VERSION 5.8 ;
BUSBITCHARS "[]" ;
DIVIDERCHAR "/" ;
UNITS
    DATABASE MICRONS 1000 ;
END UNITS

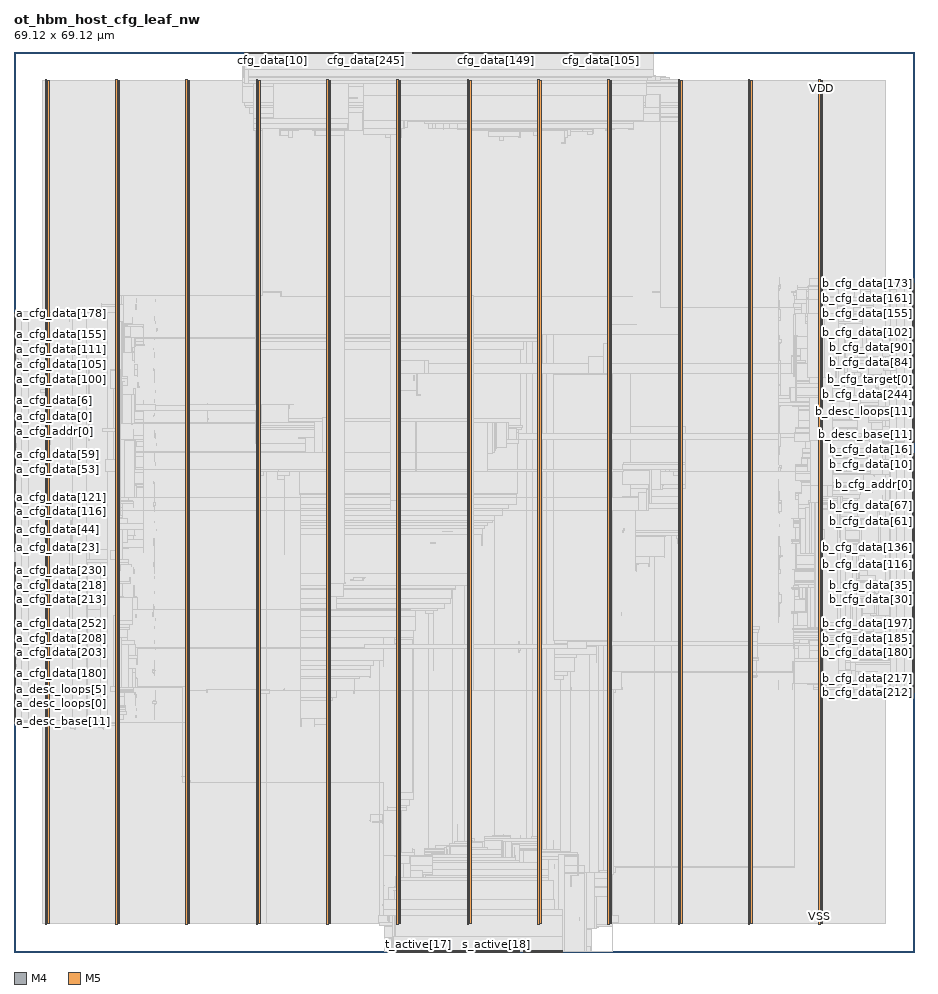
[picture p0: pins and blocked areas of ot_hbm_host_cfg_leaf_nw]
MACRO ot_hbm_host_cfg_leaf_nw
  FOREIGN ot_hbm_host_cfg_leaf_nw 0 0 ;
  CLASS BLOCK ;
  SIZE 69.12 BY 69.12 ;
  PIN a_cfg_addr[0]
    DIRECTION OUTPUT ;
    USE SIGNAL ;
    PORT
      LAYER M4 ;
        RECT  0 39.984 0.084 40.008 ;
    END
  END a_cfg_addr[0]
  PIN a_cfg_addr[10]
    DIRECTION OUTPUT ;
    USE SIGNAL ;
    PORT
      LAYER M4 ;
        RECT  0 40.944 0.084 40.968 ;
    END
  END a_cfg_addr[10]
  PIN a_cfg_addr[11]
    DIRECTION OUTPUT ;
    USE SIGNAL ;
    PORT
      LAYER M4 ;
        RECT  0 41.04 0.084 41.064 ;
    END
  END a_cfg_addr[11]
  PIN a_cfg_addr[1]
    DIRECTION OUTPUT ;
    USE SIGNAL ;
    PORT
      LAYER M4 ;
        RECT  0 40.08 0.084 40.104 ;
    END
  END a_cfg_addr[1]
  PIN a_cfg_addr[2]
    DIRECTION OUTPUT ;
    USE SIGNAL ;
    PORT
      LAYER M4 ;
        RECT  0 40.176 0.084 40.2 ;
    END
  END a_cfg_addr[2]
  PIN a_cfg_addr[3]
    DIRECTION OUTPUT ;
    USE SIGNAL ;
    PORT
      LAYER M4 ;
        RECT  0 40.272 0.084 40.296 ;
    END
  END a_cfg_addr[3]
  PIN a_cfg_addr[4]
    DIRECTION OUTPUT ;
    USE SIGNAL ;
    PORT
      LAYER M4 ;
        RECT  0 40.368 0.084 40.392 ;
    END
  END a_cfg_addr[4]
  PIN a_cfg_addr[5]
    DIRECTION OUTPUT ;
    USE SIGNAL ;
    PORT
      LAYER M4 ;
        RECT  0 40.464 0.084 40.488 ;
    END
  END a_cfg_addr[5]
  PIN a_cfg_addr[6]
    DIRECTION OUTPUT ;
    USE SIGNAL ;
    PORT
      LAYER M4 ;
        RECT  0 40.56 0.084 40.584 ;
    END
  END a_cfg_addr[6]
  PIN a_cfg_addr[7]
    DIRECTION OUTPUT ;
    USE SIGNAL ;
    PORT
      LAYER M4 ;
        RECT  0 40.656 0.084 40.68 ;
    END
  END a_cfg_addr[7]
  PIN a_cfg_addr[8]
    DIRECTION OUTPUT ;
    USE SIGNAL ;
    PORT
      LAYER M4 ;
        RECT  0 40.752 0.084 40.776 ;
    END
  END a_cfg_addr[8]
  PIN a_cfg_addr[9]
    DIRECTION OUTPUT ;
    USE SIGNAL ;
    PORT
      LAYER M4 ;
        RECT  0 40.848 0.084 40.872 ;
    END
  END a_cfg_addr[9]
  PIN a_cfg_data[0]
    DIRECTION OUTPUT ;
    USE SIGNAL ;
    PORT
      LAYER M4 ;
        RECT  0 41.136 0.084 41.16 ;
    END
  END a_cfg_data[0]
  PIN a_cfg_data[100]
    DIRECTION OUTPUT ;
    USE SIGNAL ;
    PORT
      LAYER M4 ;
        RECT  0 44.592 0.084 44.616 ;
    END
  END a_cfg_data[100]
  PIN a_cfg_data[101]
    DIRECTION OUTPUT ;
    USE SIGNAL ;
    PORT
      LAYER M4 ;
        RECT  0 44.688 0.084 44.712 ;
    END
  END a_cfg_data[101]
  PIN a_cfg_data[102]
    DIRECTION OUTPUT ;
    USE SIGNAL ;
    PORT
      LAYER M4 ;
        RECT  0 44.784 0.084 44.808 ;
    END
  END a_cfg_data[102]
  PIN a_cfg_data[103]
    DIRECTION OUTPUT ;
    USE SIGNAL ;
    PORT
      LAYER M4 ;
        RECT  0 44.88 0.084 44.904 ;
    END
  END a_cfg_data[103]
  PIN a_cfg_data[104]
    DIRECTION OUTPUT ;
    USE SIGNAL ;
    PORT
      LAYER M4 ;
        RECT  0 44.976 0.084 45 ;
    END
  END a_cfg_data[104]
  PIN a_cfg_data[105]
    DIRECTION OUTPUT ;
    USE SIGNAL ;
    PORT
      LAYER M4 ;
        RECT  0 45.072 0.084 45.096 ;
    END
  END a_cfg_data[105]
  PIN a_cfg_data[106]
    DIRECTION OUTPUT ;
    USE SIGNAL ;
    PORT
      LAYER M4 ;
        RECT  0 45.168 0.084 45.192 ;
    END
  END a_cfg_data[106]
  PIN a_cfg_data[107]
    DIRECTION OUTPUT ;
    USE SIGNAL ;
    PORT
      LAYER M4 ;
        RECT  0 45.264 0.084 45.288 ;
    END
  END a_cfg_data[107]
  PIN a_cfg_data[108]
    DIRECTION OUTPUT ;
    USE SIGNAL ;
    PORT
      LAYER M4 ;
        RECT  0 45.36 0.084 45.384 ;
    END
  END a_cfg_data[108]
  PIN a_cfg_data[109]
    DIRECTION OUTPUT ;
    USE SIGNAL ;
    PORT
      LAYER M4 ;
        RECT  0 45.456 0.084 45.48 ;
    END
  END a_cfg_data[109]
  PIN a_cfg_data[10]
    DIRECTION OUTPUT ;
    USE SIGNAL ;
    PORT
      LAYER M4 ;
        RECT  0 42.096 0.084 42.12 ;
    END
  END a_cfg_data[10]
  PIN a_cfg_data[110]
    DIRECTION OUTPUT ;
    USE SIGNAL ;
    PORT
      LAYER M4 ;
        RECT  0 45.552 0.084 45.576 ;
    END
  END a_cfg_data[110]
  PIN a_cfg_data[111]
    DIRECTION OUTPUT ;
    USE SIGNAL ;
    PORT
      LAYER M4 ;
        RECT  0 45.648 0.084 45.672 ;
    END
  END a_cfg_data[111]
  PIN a_cfg_data[112]
    DIRECTION OUTPUT ;
    USE SIGNAL ;
    PORT
      LAYER M4 ;
        RECT  0 45.744 0.084 45.768 ;
    END
  END a_cfg_data[112]
  PIN a_cfg_data[113]
    DIRECTION OUTPUT ;
    USE SIGNAL ;
    PORT
      LAYER M4 ;
        RECT  0 45.84 0.084 45.864 ;
    END
  END a_cfg_data[113]
  PIN a_cfg_data[114]
    DIRECTION OUTPUT ;
    USE SIGNAL ;
    PORT
      LAYER M4 ;
        RECT  0 45.936 0.084 45.96 ;
    END
  END a_cfg_data[114]
  PIN a_cfg_data[115]
    DIRECTION OUTPUT ;
    USE SIGNAL ;
    PORT
      LAYER M4 ;
        RECT  0 46.032 0.084 46.056 ;
    END
  END a_cfg_data[115]
  PIN a_cfg_data[116]
    DIRECTION OUTPUT ;
    USE SIGNAL ;
    PORT
      LAYER M4 ;
        RECT  0 33.84 0.084 33.864 ;
    END
  END a_cfg_data[116]
  PIN a_cfg_data[117]
    DIRECTION OUTPUT ;
    USE SIGNAL ;
    PORT
      LAYER M4 ;
        RECT  0 33.936 0.084 33.96 ;
    END
  END a_cfg_data[117]
  PIN a_cfg_data[118]
    DIRECTION OUTPUT ;
    USE SIGNAL ;
    PORT
      LAYER M4 ;
        RECT  0 34.032 0.084 34.056 ;
    END
  END a_cfg_data[118]
  PIN a_cfg_data[119]
    DIRECTION OUTPUT ;
    USE SIGNAL ;
    PORT
      LAYER M4 ;
        RECT  0 34.128 0.084 34.152 ;
    END
  END a_cfg_data[119]
  PIN a_cfg_data[11]
    DIRECTION OUTPUT ;
    USE SIGNAL ;
    PORT
      LAYER M4 ;
        RECT  0 42.192 0.084 42.216 ;
    END
  END a_cfg_data[11]
  PIN a_cfg_data[120]
    DIRECTION OUTPUT ;
    USE SIGNAL ;
    PORT
      LAYER M4 ;
        RECT  0 34.224 0.084 34.248 ;
    END
  END a_cfg_data[120]
  PIN a_cfg_data[121]
    DIRECTION OUTPUT ;
    USE SIGNAL ;
    PORT
      LAYER M4 ;
        RECT  0 34.32 0.084 34.344 ;
    END
  END a_cfg_data[121]
  PIN a_cfg_data[122]
    DIRECTION OUTPUT ;
    USE SIGNAL ;
    PORT
      LAYER M4 ;
        RECT  0 34.416 0.084 34.44 ;
    END
  END a_cfg_data[122]
  PIN a_cfg_data[123]
    DIRECTION OUTPUT ;
    USE SIGNAL ;
    PORT
      LAYER M4 ;
        RECT  0 34.512 0.084 34.536 ;
    END
  END a_cfg_data[123]
  PIN a_cfg_data[124]
    DIRECTION OUTPUT ;
    USE SIGNAL ;
    PORT
      LAYER M4 ;
        RECT  0 34.608 0.084 34.632 ;
    END
  END a_cfg_data[124]
  PIN a_cfg_data[125]
    DIRECTION OUTPUT ;
    USE SIGNAL ;
    PORT
      LAYER M4 ;
        RECT  0 34.704 0.084 34.728 ;
    END
  END a_cfg_data[125]
  PIN a_cfg_data[126]
    DIRECTION OUTPUT ;
    USE SIGNAL ;
    PORT
      LAYER M4 ;
        RECT  0 34.8 0.084 34.824 ;
    END
  END a_cfg_data[126]
  PIN a_cfg_data[127]
    DIRECTION OUTPUT ;
    USE SIGNAL ;
    PORT
      LAYER M4 ;
        RECT  0 34.896 0.084 34.92 ;
    END
  END a_cfg_data[127]
  PIN a_cfg_data[128]
    DIRECTION OUTPUT ;
    USE SIGNAL ;
    PORT
      LAYER M4 ;
        RECT  0 34.992 0.084 35.016 ;
    END
  END a_cfg_data[128]
  PIN a_cfg_data[129]
    DIRECTION OUTPUT ;
    USE SIGNAL ;
    PORT
      LAYER M4 ;
        RECT  0 35.088 0.084 35.112 ;
    END
  END a_cfg_data[129]
  PIN a_cfg_data[12]
    DIRECTION OUTPUT ;
    USE SIGNAL ;
    PORT
      LAYER M4 ;
        RECT  0 42.288 0.084 42.312 ;
    END
  END a_cfg_data[12]
  PIN a_cfg_data[130]
    DIRECTION OUTPUT ;
    USE SIGNAL ;
    PORT
      LAYER M4 ;
        RECT  0 35.184 0.084 35.208 ;
    END
  END a_cfg_data[130]
  PIN a_cfg_data[131]
    DIRECTION OUTPUT ;
    USE SIGNAL ;
    PORT
      LAYER M4 ;
        RECT  0 35.28 0.084 35.304 ;
    END
  END a_cfg_data[131]
  PIN a_cfg_data[132]
    DIRECTION OUTPUT ;
    USE SIGNAL ;
    PORT
      LAYER M4 ;
        RECT  0 35.376 0.084 35.4 ;
    END
  END a_cfg_data[132]
  PIN a_cfg_data[133]
    DIRECTION OUTPUT ;
    USE SIGNAL ;
    PORT
      LAYER M4 ;
        RECT  0 35.472 0.084 35.496 ;
    END
  END a_cfg_data[133]
  PIN a_cfg_data[134]
    DIRECTION OUTPUT ;
    USE SIGNAL ;
    PORT
      LAYER M4 ;
        RECT  0 35.568 0.084 35.592 ;
    END
  END a_cfg_data[134]
  PIN a_cfg_data[135]
    DIRECTION OUTPUT ;
    USE SIGNAL ;
    PORT
      LAYER M4 ;
        RECT  0 35.664 0.084 35.688 ;
    END
  END a_cfg_data[135]
  PIN a_cfg_data[136]
    DIRECTION OUTPUT ;
    USE SIGNAL ;
    PORT
      LAYER M4 ;
        RECT  0 35.76 0.084 35.784 ;
    END
  END a_cfg_data[136]
  PIN a_cfg_data[137]
    DIRECTION OUTPUT ;
    USE SIGNAL ;
    PORT
      LAYER M4 ;
        RECT  0 35.856 0.084 35.88 ;
    END
  END a_cfg_data[137]
  PIN a_cfg_data[138]
    DIRECTION OUTPUT ;
    USE SIGNAL ;
    PORT
      LAYER M4 ;
        RECT  0 35.952 0.084 35.976 ;
    END
  END a_cfg_data[138]
  PIN a_cfg_data[139]
    DIRECTION OUTPUT ;
    USE SIGNAL ;
    PORT
      LAYER M4 ;
        RECT  0 36.048 0.084 36.072 ;
    END
  END a_cfg_data[139]
  PIN a_cfg_data[13]
    DIRECTION OUTPUT ;
    USE SIGNAL ;
    PORT
      LAYER M4 ;
        RECT  0 42.384 0.084 42.408 ;
    END
  END a_cfg_data[13]
  PIN a_cfg_data[140]
    DIRECTION OUTPUT ;
    USE SIGNAL ;
    PORT
      LAYER M4 ;
        RECT  0 36.144 0.084 36.168 ;
    END
  END a_cfg_data[140]
  PIN a_cfg_data[141]
    DIRECTION OUTPUT ;
    USE SIGNAL ;
    PORT
      LAYER M4 ;
        RECT  0 36.24 0.084 36.264 ;
    END
  END a_cfg_data[141]
  PIN a_cfg_data[142]
    DIRECTION OUTPUT ;
    USE SIGNAL ;
    PORT
      LAYER M4 ;
        RECT  0 36.336 0.084 36.36 ;
    END
  END a_cfg_data[142]
  PIN a_cfg_data[143]
    DIRECTION OUTPUT ;
    USE SIGNAL ;
    PORT
      LAYER M4 ;
        RECT  0 36.432 0.084 36.456 ;
    END
  END a_cfg_data[143]
  PIN a_cfg_data[144]
    DIRECTION OUTPUT ;
    USE SIGNAL ;
    PORT
      LAYER M4 ;
        RECT  0 36.528 0.084 36.552 ;
    END
  END a_cfg_data[144]
  PIN a_cfg_data[145]
    DIRECTION OUTPUT ;
    USE SIGNAL ;
    PORT
      LAYER M4 ;
        RECT  0 36.624 0.084 36.648 ;
    END
  END a_cfg_data[145]
  PIN a_cfg_data[146]
    DIRECTION OUTPUT ;
    USE SIGNAL ;
    PORT
      LAYER M4 ;
        RECT  0 36.72 0.084 36.744 ;
    END
  END a_cfg_data[146]
  PIN a_cfg_data[147]
    DIRECTION OUTPUT ;
    USE SIGNAL ;
    PORT
      LAYER M4 ;
        RECT  0 36.816 0.084 36.84 ;
    END
  END a_cfg_data[147]
  PIN a_cfg_data[148]
    DIRECTION OUTPUT ;
    USE SIGNAL ;
    PORT
      LAYER M4 ;
        RECT  0 46.128 0.084 46.152 ;
    END
  END a_cfg_data[148]
  PIN a_cfg_data[149]
    DIRECTION OUTPUT ;
    USE SIGNAL ;
    PORT
      LAYER M4 ;
        RECT  0 46.224 0.084 46.248 ;
    END
  END a_cfg_data[149]
  PIN a_cfg_data[14]
    DIRECTION OUTPUT ;
    USE SIGNAL ;
    PORT
      LAYER M4 ;
        RECT  0 42.48 0.084 42.504 ;
    END
  END a_cfg_data[14]
  PIN a_cfg_data[150]
    DIRECTION OUTPUT ;
    USE SIGNAL ;
    PORT
      LAYER M4 ;
        RECT  0 46.32 0.084 46.344 ;
    END
  END a_cfg_data[150]
  PIN a_cfg_data[151]
    DIRECTION OUTPUT ;
    USE SIGNAL ;
    PORT
      LAYER M4 ;
        RECT  0 46.416 0.084 46.44 ;
    END
  END a_cfg_data[151]
  PIN a_cfg_data[152]
    DIRECTION OUTPUT ;
    USE SIGNAL ;
    PORT
      LAYER M4 ;
        RECT  0 46.512 0.084 46.536 ;
    END
  END a_cfg_data[152]
  PIN a_cfg_data[153]
    DIRECTION OUTPUT ;
    USE SIGNAL ;
    PORT
      LAYER M4 ;
        RECT  0 46.608 0.084 46.632 ;
    END
  END a_cfg_data[153]
  PIN a_cfg_data[154]
    DIRECTION OUTPUT ;
    USE SIGNAL ;
    PORT
      LAYER M4 ;
        RECT  0 46.704 0.084 46.728 ;
    END
  END a_cfg_data[154]
  PIN a_cfg_data[155]
    DIRECTION OUTPUT ;
    USE SIGNAL ;
    PORT
      LAYER M4 ;
        RECT  0 46.8 0.084 46.824 ;
    END
  END a_cfg_data[155]
  PIN a_cfg_data[156]
    DIRECTION OUTPUT ;
    USE SIGNAL ;
    PORT
      LAYER M4 ;
        RECT  0 46.896 0.084 46.92 ;
    END
  END a_cfg_data[156]
  PIN a_cfg_data[157]
    DIRECTION OUTPUT ;
    USE SIGNAL ;
    PORT
      LAYER M4 ;
        RECT  0 46.992 0.084 47.016 ;
    END
  END a_cfg_data[157]
  PIN a_cfg_data[158]
    DIRECTION OUTPUT ;
    USE SIGNAL ;
    PORT
      LAYER M4 ;
        RECT  0 47.088 0.084 47.112 ;
    END
  END a_cfg_data[158]
  PIN a_cfg_data[159]
    DIRECTION OUTPUT ;
    USE SIGNAL ;
    PORT
      LAYER M4 ;
        RECT  0 47.184 0.084 47.208 ;
    END
  END a_cfg_data[159]
  PIN a_cfg_data[15]
    DIRECTION OUTPUT ;
    USE SIGNAL ;
    PORT
      LAYER M4 ;
        RECT  0 42.576 0.084 42.6 ;
    END
  END a_cfg_data[15]
  PIN a_cfg_data[160]
    DIRECTION OUTPUT ;
    USE SIGNAL ;
    PORT
      LAYER M4 ;
        RECT  0 47.28 0.084 47.304 ;
    END
  END a_cfg_data[160]
  PIN a_cfg_data[161]
    DIRECTION OUTPUT ;
    USE SIGNAL ;
    PORT
      LAYER M4 ;
        RECT  0 47.376 0.084 47.4 ;
    END
  END a_cfg_data[161]
  PIN a_cfg_data[162]
    DIRECTION OUTPUT ;
    USE SIGNAL ;
    PORT
      LAYER M4 ;
        RECT  0 47.472 0.084 47.496 ;
    END
  END a_cfg_data[162]
  PIN a_cfg_data[163]
    DIRECTION OUTPUT ;
    USE SIGNAL ;
    PORT
      LAYER M4 ;
        RECT  0 47.568 0.084 47.592 ;
    END
  END a_cfg_data[163]
  PIN a_cfg_data[164]
    DIRECTION OUTPUT ;
    USE SIGNAL ;
    PORT
      LAYER M4 ;
        RECT  0 47.664 0.084 47.688 ;
    END
  END a_cfg_data[164]
  PIN a_cfg_data[165]
    DIRECTION OUTPUT ;
    USE SIGNAL ;
    PORT
      LAYER M4 ;
        RECT  0 47.76 0.084 47.784 ;
    END
  END a_cfg_data[165]
  PIN a_cfg_data[166]
    DIRECTION OUTPUT ;
    USE SIGNAL ;
    PORT
      LAYER M4 ;
        RECT  0 47.856 0.084 47.88 ;
    END
  END a_cfg_data[166]
  PIN a_cfg_data[167]
    DIRECTION OUTPUT ;
    USE SIGNAL ;
    PORT
      LAYER M4 ;
        RECT  0 47.952 0.084 47.976 ;
    END
  END a_cfg_data[167]
  PIN a_cfg_data[168]
    DIRECTION OUTPUT ;
    USE SIGNAL ;
    PORT
      LAYER M4 ;
        RECT  0 48.048 0.084 48.072 ;
    END
  END a_cfg_data[168]
  PIN a_cfg_data[169]
    DIRECTION OUTPUT ;
    USE SIGNAL ;
    PORT
      LAYER M4 ;
        RECT  0 48.144 0.084 48.168 ;
    END
  END a_cfg_data[169]
  PIN a_cfg_data[16]
    DIRECTION OUTPUT ;
    USE SIGNAL ;
    PORT
      LAYER M4 ;
        RECT  0 42.672 0.084 42.696 ;
    END
  END a_cfg_data[16]
  PIN a_cfg_data[170]
    DIRECTION OUTPUT ;
    USE SIGNAL ;
    PORT
      LAYER M4 ;
        RECT  0 48.24 0.084 48.264 ;
    END
  END a_cfg_data[170]
  PIN a_cfg_data[171]
    DIRECTION OUTPUT ;
    USE SIGNAL ;
    PORT
      LAYER M4 ;
        RECT  0 48.336 0.084 48.36 ;
    END
  END a_cfg_data[171]
  PIN a_cfg_data[172]
    DIRECTION OUTPUT ;
    USE SIGNAL ;
    PORT
      LAYER M4 ;
        RECT  0 48.432 0.084 48.456 ;
    END
  END a_cfg_data[172]
  PIN a_cfg_data[173]
    DIRECTION OUTPUT ;
    USE SIGNAL ;
    PORT
      LAYER M4 ;
        RECT  0 48.528 0.084 48.552 ;
    END
  END a_cfg_data[173]
  PIN a_cfg_data[174]
    DIRECTION OUTPUT ;
    USE SIGNAL ;
    PORT
      LAYER M4 ;
        RECT  0 48.624 0.084 48.648 ;
    END
  END a_cfg_data[174]
  PIN a_cfg_data[175]
    DIRECTION OUTPUT ;
    USE SIGNAL ;
    PORT
      LAYER M4 ;
        RECT  0 48.72 0.084 48.744 ;
    END
  END a_cfg_data[175]
  PIN a_cfg_data[176]
    DIRECTION OUTPUT ;
    USE SIGNAL ;
    PORT
      LAYER M4 ;
        RECT  0 48.816 0.084 48.84 ;
    END
  END a_cfg_data[176]
  PIN a_cfg_data[177]
    DIRECTION OUTPUT ;
    USE SIGNAL ;
    PORT
      LAYER M4 ;
        RECT  0 48.912 0.084 48.936 ;
    END
  END a_cfg_data[177]
  PIN a_cfg_data[178]
    DIRECTION OUTPUT ;
    USE SIGNAL ;
    PORT
      LAYER M4 ;
        RECT  0 49.008 0.084 49.032 ;
    END
  END a_cfg_data[178]
  PIN a_cfg_data[179]
    DIRECTION OUTPUT ;
    USE SIGNAL ;
    PORT
      LAYER M4 ;
        RECT  0 49.104 0.084 49.128 ;
    END
  END a_cfg_data[179]
  PIN a_cfg_data[17]
    DIRECTION OUTPUT ;
    USE SIGNAL ;
    PORT
      LAYER M4 ;
        RECT  0 42.768 0.084 42.792 ;
    END
  END a_cfg_data[17]
  PIN a_cfg_data[180]
    DIRECTION OUTPUT ;
    USE SIGNAL ;
    PORT
      LAYER M4 ;
        RECT  0 20.784 0.084 20.808 ;
    END
  END a_cfg_data[180]
  PIN a_cfg_data[181]
    DIRECTION OUTPUT ;
    USE SIGNAL ;
    PORT
      LAYER M4 ;
        RECT  0 20.88 0.084 20.904 ;
    END
  END a_cfg_data[181]
  PIN a_cfg_data[182]
    DIRECTION OUTPUT ;
    USE SIGNAL ;
    PORT
      LAYER M4 ;
        RECT  0 20.976 0.084 21 ;
    END
  END a_cfg_data[182]
  PIN a_cfg_data[183]
    DIRECTION OUTPUT ;
    USE SIGNAL ;
    PORT
      LAYER M4 ;
        RECT  0 21.072 0.084 21.096 ;
    END
  END a_cfg_data[183]
  PIN a_cfg_data[184]
    DIRECTION OUTPUT ;
    USE SIGNAL ;
    PORT
      LAYER M4 ;
        RECT  0 21.168 0.084 21.192 ;
    END
  END a_cfg_data[184]
  PIN a_cfg_data[185]
    DIRECTION OUTPUT ;
    USE SIGNAL ;
    PORT
      LAYER M4 ;
        RECT  0 21.264 0.084 21.288 ;
    END
  END a_cfg_data[185]
  PIN a_cfg_data[186]
    DIRECTION OUTPUT ;
    USE SIGNAL ;
    PORT
      LAYER M4 ;
        RECT  0 21.36 0.084 21.384 ;
    END
  END a_cfg_data[186]
  PIN a_cfg_data[187]
    DIRECTION OUTPUT ;
    USE SIGNAL ;
    PORT
      LAYER M4 ;
        RECT  0 21.456 0.084 21.48 ;
    END
  END a_cfg_data[187]
  PIN a_cfg_data[188]
    DIRECTION OUTPUT ;
    USE SIGNAL ;
    PORT
      LAYER M4 ;
        RECT  0 21.552 0.084 21.576 ;
    END
  END a_cfg_data[188]
  PIN a_cfg_data[189]
    DIRECTION OUTPUT ;
    USE SIGNAL ;
    PORT
      LAYER M4 ;
        RECT  0 21.648 0.084 21.672 ;
    END
  END a_cfg_data[189]
  PIN a_cfg_data[18]
    DIRECTION OUTPUT ;
    USE SIGNAL ;
    PORT
      LAYER M4 ;
        RECT  0 42.864 0.084 42.888 ;
    END
  END a_cfg_data[18]
  PIN a_cfg_data[190]
    DIRECTION OUTPUT ;
    USE SIGNAL ;
    PORT
      LAYER M4 ;
        RECT  0 21.744 0.084 21.768 ;
    END
  END a_cfg_data[190]
  PIN a_cfg_data[191]
    DIRECTION OUTPUT ;
    USE SIGNAL ;
    PORT
      LAYER M4 ;
        RECT  0 21.84 0.084 21.864 ;
    END
  END a_cfg_data[191]
  PIN a_cfg_data[192]
    DIRECTION OUTPUT ;
    USE SIGNAL ;
    PORT
      LAYER M4 ;
        RECT  0 21.936 0.084 21.96 ;
    END
  END a_cfg_data[192]
  PIN a_cfg_data[193]
    DIRECTION OUTPUT ;
    USE SIGNAL ;
    PORT
      LAYER M4 ;
        RECT  0 22.032 0.084 22.056 ;
    END
  END a_cfg_data[193]
  PIN a_cfg_data[194]
    DIRECTION OUTPUT ;
    USE SIGNAL ;
    PORT
      LAYER M4 ;
        RECT  0 22.128 0.084 22.152 ;
    END
  END a_cfg_data[194]
  PIN a_cfg_data[195]
    DIRECTION OUTPUT ;
    USE SIGNAL ;
    PORT
      LAYER M4 ;
        RECT  0 22.224 0.084 22.248 ;
    END
  END a_cfg_data[195]
  PIN a_cfg_data[196]
    DIRECTION OUTPUT ;
    USE SIGNAL ;
    PORT
      LAYER M4 ;
        RECT  0 22.32 0.084 22.344 ;
    END
  END a_cfg_data[196]
  PIN a_cfg_data[197]
    DIRECTION OUTPUT ;
    USE SIGNAL ;
    PORT
      LAYER M4 ;
        RECT  0 22.416 0.084 22.44 ;
    END
  END a_cfg_data[197]
  PIN a_cfg_data[198]
    DIRECTION OUTPUT ;
    USE SIGNAL ;
    PORT
      LAYER M4 ;
        RECT  0 22.512 0.084 22.536 ;
    END
  END a_cfg_data[198]
  PIN a_cfg_data[199]
    DIRECTION OUTPUT ;
    USE SIGNAL ;
    PORT
      LAYER M4 ;
        RECT  0 22.608 0.084 22.632 ;
    END
  END a_cfg_data[199]
  PIN a_cfg_data[19]
    DIRECTION OUTPUT ;
    USE SIGNAL ;
    PORT
      LAYER M4 ;
        RECT  0 42.96 0.084 42.984 ;
    END
  END a_cfg_data[19]
  PIN a_cfg_data[1]
    DIRECTION OUTPUT ;
    USE SIGNAL ;
    PORT
      LAYER M4 ;
        RECT  0 41.232 0.084 41.256 ;
    END
  END a_cfg_data[1]
  PIN a_cfg_data[200]
    DIRECTION OUTPUT ;
    USE SIGNAL ;
    PORT
      LAYER M4 ;
        RECT  0 22.704 0.084 22.728 ;
    END
  END a_cfg_data[200]
  PIN a_cfg_data[201]
    DIRECTION OUTPUT ;
    USE SIGNAL ;
    PORT
      LAYER M4 ;
        RECT  0 22.8 0.084 22.824 ;
    END
  END a_cfg_data[201]
  PIN a_cfg_data[202]
    DIRECTION OUTPUT ;
    USE SIGNAL ;
    PORT
      LAYER M4 ;
        RECT  0 22.896 0.084 22.92 ;
    END
  END a_cfg_data[202]
  PIN a_cfg_data[203]
    DIRECTION OUTPUT ;
    USE SIGNAL ;
    PORT
      LAYER M4 ;
        RECT  0 22.992 0.084 23.016 ;
    END
  END a_cfg_data[203]
  PIN a_cfg_data[204]
    DIRECTION OUTPUT ;
    USE SIGNAL ;
    PORT
      LAYER M4 ;
        RECT  0 23.088 0.084 23.112 ;
    END
  END a_cfg_data[204]
  PIN a_cfg_data[205]
    DIRECTION OUTPUT ;
    USE SIGNAL ;
    PORT
      LAYER M4 ;
        RECT  0 23.184 0.084 23.208 ;
    END
  END a_cfg_data[205]
  PIN a_cfg_data[206]
    DIRECTION OUTPUT ;
    USE SIGNAL ;
    PORT
      LAYER M4 ;
        RECT  0 23.28 0.084 23.304 ;
    END
  END a_cfg_data[206]
  PIN a_cfg_data[207]
    DIRECTION OUTPUT ;
    USE SIGNAL ;
    PORT
      LAYER M4 ;
        RECT  0 23.376 0.084 23.4 ;
    END
  END a_cfg_data[207]
  PIN a_cfg_data[208]
    DIRECTION OUTPUT ;
    USE SIGNAL ;
    PORT
      LAYER M4 ;
        RECT  0 23.472 0.084 23.496 ;
    END
  END a_cfg_data[208]
  PIN a_cfg_data[209]
    DIRECTION OUTPUT ;
    USE SIGNAL ;
    PORT
      LAYER M4 ;
        RECT  0 23.568 0.084 23.592 ;
    END
  END a_cfg_data[209]
  PIN a_cfg_data[20]
    DIRECTION OUTPUT ;
    USE SIGNAL ;
    PORT
      LAYER M4 ;
        RECT  0 30.768 0.084 30.792 ;
    END
  END a_cfg_data[20]
  PIN a_cfg_data[210]
    DIRECTION OUTPUT ;
    USE SIGNAL ;
    PORT
      LAYER M4 ;
        RECT  0 23.664 0.084 23.688 ;
    END
  END a_cfg_data[210]
  PIN a_cfg_data[211]
    DIRECTION OUTPUT ;
    USE SIGNAL ;
    PORT
      LAYER M4 ;
        RECT  0 23.76 0.084 23.784 ;
    END
  END a_cfg_data[211]
  PIN a_cfg_data[212]
    DIRECTION OUTPUT ;
    USE SIGNAL ;
    PORT
      LAYER M4 ;
        RECT  0 26.928 0.084 26.952 ;
    END
  END a_cfg_data[212]
  PIN a_cfg_data[213]
    DIRECTION OUTPUT ;
    USE SIGNAL ;
    PORT
      LAYER M4 ;
        RECT  0 27.024 0.084 27.048 ;
    END
  END a_cfg_data[213]
  PIN a_cfg_data[214]
    DIRECTION OUTPUT ;
    USE SIGNAL ;
    PORT
      LAYER M4 ;
        RECT  0 27.12 0.084 27.144 ;
    END
  END a_cfg_data[214]
  PIN a_cfg_data[215]
    DIRECTION OUTPUT ;
    USE SIGNAL ;
    PORT
      LAYER M4 ;
        RECT  0 27.216 0.084 27.24 ;
    END
  END a_cfg_data[215]
  PIN a_cfg_data[216]
    DIRECTION OUTPUT ;
    USE SIGNAL ;
    PORT
      LAYER M4 ;
        RECT  0 27.312 0.084 27.336 ;
    END
  END a_cfg_data[216]
  PIN a_cfg_data[217]
    DIRECTION OUTPUT ;
    USE SIGNAL ;
    PORT
      LAYER M4 ;
        RECT  0 27.408 0.084 27.432 ;
    END
  END a_cfg_data[217]
  PIN a_cfg_data[218]
    DIRECTION OUTPUT ;
    USE SIGNAL ;
    PORT
      LAYER M4 ;
        RECT  0 27.504 0.084 27.528 ;
    END
  END a_cfg_data[218]
  PIN a_cfg_data[219]
    DIRECTION OUTPUT ;
    USE SIGNAL ;
    PORT
      LAYER M4 ;
        RECT  0 27.6 0.084 27.624 ;
    END
  END a_cfg_data[219]
  PIN a_cfg_data[21]
    DIRECTION OUTPUT ;
    USE SIGNAL ;
    PORT
      LAYER M4 ;
        RECT  0 30.864 0.084 30.888 ;
    END
  END a_cfg_data[21]
  PIN a_cfg_data[220]
    DIRECTION OUTPUT ;
    USE SIGNAL ;
    PORT
      LAYER M4 ;
        RECT  0 27.696 0.084 27.72 ;
    END
  END a_cfg_data[220]
  PIN a_cfg_data[221]
    DIRECTION OUTPUT ;
    USE SIGNAL ;
    PORT
      LAYER M4 ;
        RECT  0 27.792 0.084 27.816 ;
    END
  END a_cfg_data[221]
  PIN a_cfg_data[222]
    DIRECTION OUTPUT ;
    USE SIGNAL ;
    PORT
      LAYER M4 ;
        RECT  0 27.888 0.084 27.912 ;
    END
  END a_cfg_data[222]
  PIN a_cfg_data[223]
    DIRECTION OUTPUT ;
    USE SIGNAL ;
    PORT
      LAYER M4 ;
        RECT  0 27.984 0.084 28.008 ;
    END
  END a_cfg_data[223]
  PIN a_cfg_data[224]
    DIRECTION OUTPUT ;
    USE SIGNAL ;
    PORT
      LAYER M4 ;
        RECT  0 28.08 0.084 28.104 ;
    END
  END a_cfg_data[224]
  PIN a_cfg_data[225]
    DIRECTION OUTPUT ;
    USE SIGNAL ;
    PORT
      LAYER M4 ;
        RECT  0 28.176 0.084 28.2 ;
    END
  END a_cfg_data[225]
  PIN a_cfg_data[226]
    DIRECTION OUTPUT ;
    USE SIGNAL ;
    PORT
      LAYER M4 ;
        RECT  0 28.272 0.084 28.296 ;
    END
  END a_cfg_data[226]
  PIN a_cfg_data[227]
    DIRECTION OUTPUT ;
    USE SIGNAL ;
    PORT
      LAYER M4 ;
        RECT  0 28.368 0.084 28.392 ;
    END
  END a_cfg_data[227]
  PIN a_cfg_data[228]
    DIRECTION OUTPUT ;
    USE SIGNAL ;
    PORT
      LAYER M4 ;
        RECT  0 28.464 0.084 28.488 ;
    END
  END a_cfg_data[228]
  PIN a_cfg_data[229]
    DIRECTION OUTPUT ;
    USE SIGNAL ;
    PORT
      LAYER M4 ;
        RECT  0 28.56 0.084 28.584 ;
    END
  END a_cfg_data[229]
  PIN a_cfg_data[22]
    DIRECTION OUTPUT ;
    USE SIGNAL ;
    PORT
      LAYER M4 ;
        RECT  0 30.96 0.084 30.984 ;
    END
  END a_cfg_data[22]
  PIN a_cfg_data[230]
    DIRECTION OUTPUT ;
    USE SIGNAL ;
    PORT
      LAYER M4 ;
        RECT  0 28.656 0.084 28.68 ;
    END
  END a_cfg_data[230]
  PIN a_cfg_data[231]
    DIRECTION OUTPUT ;
    USE SIGNAL ;
    PORT
      LAYER M4 ;
        RECT  0 28.752 0.084 28.776 ;
    END
  END a_cfg_data[231]
  PIN a_cfg_data[232]
    DIRECTION OUTPUT ;
    USE SIGNAL ;
    PORT
      LAYER M4 ;
        RECT  0 28.848 0.084 28.872 ;
    END
  END a_cfg_data[232]
  PIN a_cfg_data[233]
    DIRECTION OUTPUT ;
    USE SIGNAL ;
    PORT
      LAYER M4 ;
        RECT  0 28.944 0.084 28.968 ;
    END
  END a_cfg_data[233]
  PIN a_cfg_data[234]
    DIRECTION OUTPUT ;
    USE SIGNAL ;
    PORT
      LAYER M4 ;
        RECT  0 29.04 0.084 29.064 ;
    END
  END a_cfg_data[234]
  PIN a_cfg_data[235]
    DIRECTION OUTPUT ;
    USE SIGNAL ;
    PORT
      LAYER M4 ;
        RECT  0 29.136 0.084 29.16 ;
    END
  END a_cfg_data[235]
  PIN a_cfg_data[236]
    DIRECTION OUTPUT ;
    USE SIGNAL ;
    PORT
      LAYER M4 ;
        RECT  0 29.232 0.084 29.256 ;
    END
  END a_cfg_data[236]
  PIN a_cfg_data[237]
    DIRECTION OUTPUT ;
    USE SIGNAL ;
    PORT
      LAYER M4 ;
        RECT  0 29.328 0.084 29.352 ;
    END
  END a_cfg_data[237]
  PIN a_cfg_data[238]
    DIRECTION OUTPUT ;
    USE SIGNAL ;
    PORT
      LAYER M4 ;
        RECT  0 29.424 0.084 29.448 ;
    END
  END a_cfg_data[238]
  PIN a_cfg_data[239]
    DIRECTION OUTPUT ;
    USE SIGNAL ;
    PORT
      LAYER M4 ;
        RECT  0 29.52 0.084 29.544 ;
    END
  END a_cfg_data[239]
  PIN a_cfg_data[23]
    DIRECTION OUTPUT ;
    USE SIGNAL ;
    PORT
      LAYER M4 ;
        RECT  0 31.056 0.084 31.08 ;
    END
  END a_cfg_data[23]
  PIN a_cfg_data[240]
    DIRECTION OUTPUT ;
    USE SIGNAL ;
    PORT
      LAYER M4 ;
        RECT  0 29.616 0.084 29.64 ;
    END
  END a_cfg_data[240]
  PIN a_cfg_data[241]
    DIRECTION OUTPUT ;
    USE SIGNAL ;
    PORT
      LAYER M4 ;
        RECT  0 29.712 0.084 29.736 ;
    END
  END a_cfg_data[241]
  PIN a_cfg_data[242]
    DIRECTION OUTPUT ;
    USE SIGNAL ;
    PORT
      LAYER M4 ;
        RECT  0 29.808 0.084 29.832 ;
    END
  END a_cfg_data[242]
  PIN a_cfg_data[243]
    DIRECTION OUTPUT ;
    USE SIGNAL ;
    PORT
      LAYER M4 ;
        RECT  0 29.904 0.084 29.928 ;
    END
  END a_cfg_data[243]
  PIN a_cfg_data[244]
    DIRECTION OUTPUT ;
    USE SIGNAL ;
    PORT
      LAYER M4 ;
        RECT  0 23.856 0.084 23.88 ;
    END
  END a_cfg_data[244]
  PIN a_cfg_data[245]
    DIRECTION OUTPUT ;
    USE SIGNAL ;
    PORT
      LAYER M4 ;
        RECT  0 23.952 0.084 23.976 ;
    END
  END a_cfg_data[245]
  PIN a_cfg_data[246]
    DIRECTION OUTPUT ;
    USE SIGNAL ;
    PORT
      LAYER M4 ;
        RECT  0 24.048 0.084 24.072 ;
    END
  END a_cfg_data[246]
  PIN a_cfg_data[247]
    DIRECTION OUTPUT ;
    USE SIGNAL ;
    PORT
      LAYER M4 ;
        RECT  0 24.144 0.084 24.168 ;
    END
  END a_cfg_data[247]
  PIN a_cfg_data[248]
    DIRECTION OUTPUT ;
    USE SIGNAL ;
    PORT
      LAYER M4 ;
        RECT  0 24.24 0.084 24.264 ;
    END
  END a_cfg_data[248]
  PIN a_cfg_data[249]
    DIRECTION OUTPUT ;
    USE SIGNAL ;
    PORT
      LAYER M4 ;
        RECT  0 24.336 0.084 24.36 ;
    END
  END a_cfg_data[249]
  PIN a_cfg_data[24]
    DIRECTION OUTPUT ;
    USE SIGNAL ;
    PORT
      LAYER M4 ;
        RECT  0 31.152 0.084 31.176 ;
    END
  END a_cfg_data[24]
  PIN a_cfg_data[250]
    DIRECTION OUTPUT ;
    USE SIGNAL ;
    PORT
      LAYER M4 ;
        RECT  0 24.432 0.084 24.456 ;
    END
  END a_cfg_data[250]
  PIN a_cfg_data[251]
    DIRECTION OUTPUT ;
    USE SIGNAL ;
    PORT
      LAYER M4 ;
        RECT  0 24.528 0.084 24.552 ;
    END
  END a_cfg_data[251]
  PIN a_cfg_data[252]
    DIRECTION OUTPUT ;
    USE SIGNAL ;
    PORT
      LAYER M4 ;
        RECT  0 24.624 0.084 24.648 ;
    END
  END a_cfg_data[252]
  PIN a_cfg_data[253]
    DIRECTION OUTPUT ;
    USE SIGNAL ;
    PORT
      LAYER M4 ;
        RECT  0 24.72 0.084 24.744 ;
    END
  END a_cfg_data[253]
  PIN a_cfg_data[254]
    DIRECTION OUTPUT ;
    USE SIGNAL ;
    PORT
      LAYER M4 ;
        RECT  0 24.816 0.084 24.84 ;
    END
  END a_cfg_data[254]
  PIN a_cfg_data[255]
    DIRECTION OUTPUT ;
    USE SIGNAL ;
    PORT
      LAYER M4 ;
        RECT  0 24.912 0.084 24.936 ;
    END
  END a_cfg_data[255]
  PIN a_cfg_data[25]
    DIRECTION OUTPUT ;
    USE SIGNAL ;
    PORT
      LAYER M4 ;
        RECT  0 31.248 0.084 31.272 ;
    END
  END a_cfg_data[25]
  PIN a_cfg_data[26]
    DIRECTION OUTPUT ;
    USE SIGNAL ;
    PORT
      LAYER M4 ;
        RECT  0 31.344 0.084 31.368 ;
    END
  END a_cfg_data[26]
  PIN a_cfg_data[27]
    DIRECTION OUTPUT ;
    USE SIGNAL ;
    PORT
      LAYER M4 ;
        RECT  0 31.44 0.084 31.464 ;
    END
  END a_cfg_data[27]
  PIN a_cfg_data[28]
    DIRECTION OUTPUT ;
    USE SIGNAL ;
    PORT
      LAYER M4 ;
        RECT  0 31.536 0.084 31.56 ;
    END
  END a_cfg_data[28]
  PIN a_cfg_data[29]
    DIRECTION OUTPUT ;
    USE SIGNAL ;
    PORT
      LAYER M4 ;
        RECT  0 31.632 0.084 31.656 ;
    END
  END a_cfg_data[29]
  PIN a_cfg_data[2]
    DIRECTION OUTPUT ;
    USE SIGNAL ;
    PORT
      LAYER M4 ;
        RECT  0 41.328 0.084 41.352 ;
    END
  END a_cfg_data[2]
  PIN a_cfg_data[30]
    DIRECTION OUTPUT ;
    USE SIGNAL ;
    PORT
      LAYER M4 ;
        RECT  0 31.728 0.084 31.752 ;
    END
  END a_cfg_data[30]
  PIN a_cfg_data[31]
    DIRECTION OUTPUT ;
    USE SIGNAL ;
    PORT
      LAYER M4 ;
        RECT  0 31.824 0.084 31.848 ;
    END
  END a_cfg_data[31]
  PIN a_cfg_data[32]
    DIRECTION OUTPUT ;
    USE SIGNAL ;
    PORT
      LAYER M4 ;
        RECT  0 31.92 0.084 31.944 ;
    END
  END a_cfg_data[32]
  PIN a_cfg_data[33]
    DIRECTION OUTPUT ;
    USE SIGNAL ;
    PORT
      LAYER M4 ;
        RECT  0 32.016 0.084 32.04 ;
    END
  END a_cfg_data[33]
  PIN a_cfg_data[34]
    DIRECTION OUTPUT ;
    USE SIGNAL ;
    PORT
      LAYER M4 ;
        RECT  0 32.112 0.084 32.136 ;
    END
  END a_cfg_data[34]
  PIN a_cfg_data[35]
    DIRECTION OUTPUT ;
    USE SIGNAL ;
    PORT
      LAYER M4 ;
        RECT  0 32.208 0.084 32.232 ;
    END
  END a_cfg_data[35]
  PIN a_cfg_data[36]
    DIRECTION OUTPUT ;
    USE SIGNAL ;
    PORT
      LAYER M4 ;
        RECT  0 32.304 0.084 32.328 ;
    END
  END a_cfg_data[36]
  PIN a_cfg_data[37]
    DIRECTION OUTPUT ;
    USE SIGNAL ;
    PORT
      LAYER M4 ;
        RECT  0 32.4 0.084 32.424 ;
    END
  END a_cfg_data[37]
  PIN a_cfg_data[38]
    DIRECTION OUTPUT ;
    USE SIGNAL ;
    PORT
      LAYER M4 ;
        RECT  0 32.496 0.084 32.52 ;
    END
  END a_cfg_data[38]
  PIN a_cfg_data[39]
    DIRECTION OUTPUT ;
    USE SIGNAL ;
    PORT
      LAYER M4 ;
        RECT  0 32.592 0.084 32.616 ;
    END
  END a_cfg_data[39]
  PIN a_cfg_data[3]
    DIRECTION OUTPUT ;
    USE SIGNAL ;
    PORT
      LAYER M4 ;
        RECT  0 41.424 0.084 41.448 ;
    END
  END a_cfg_data[3]
  PIN a_cfg_data[40]
    DIRECTION OUTPUT ;
    USE SIGNAL ;
    PORT
      LAYER M4 ;
        RECT  0 32.688 0.084 32.712 ;
    END
  END a_cfg_data[40]
  PIN a_cfg_data[41]
    DIRECTION OUTPUT ;
    USE SIGNAL ;
    PORT
      LAYER M4 ;
        RECT  0 32.784 0.084 32.808 ;
    END
  END a_cfg_data[41]
  PIN a_cfg_data[42]
    DIRECTION OUTPUT ;
    USE SIGNAL ;
    PORT
      LAYER M4 ;
        RECT  0 32.88 0.084 32.904 ;
    END
  END a_cfg_data[42]
  PIN a_cfg_data[43]
    DIRECTION OUTPUT ;
    USE SIGNAL ;
    PORT
      LAYER M4 ;
        RECT  0 32.976 0.084 33 ;
    END
  END a_cfg_data[43]
  PIN a_cfg_data[44]
    DIRECTION OUTPUT ;
    USE SIGNAL ;
    PORT
      LAYER M4 ;
        RECT  0 33.072 0.084 33.096 ;
    END
  END a_cfg_data[44]
  PIN a_cfg_data[45]
    DIRECTION OUTPUT ;
    USE SIGNAL ;
    PORT
      LAYER M4 ;
        RECT  0 33.168 0.084 33.192 ;
    END
  END a_cfg_data[45]
  PIN a_cfg_data[46]
    DIRECTION OUTPUT ;
    USE SIGNAL ;
    PORT
      LAYER M4 ;
        RECT  0 33.264 0.084 33.288 ;
    END
  END a_cfg_data[46]
  PIN a_cfg_data[47]
    DIRECTION OUTPUT ;
    USE SIGNAL ;
    PORT
      LAYER M4 ;
        RECT  0 33.36 0.084 33.384 ;
    END
  END a_cfg_data[47]
  PIN a_cfg_data[48]
    DIRECTION OUTPUT ;
    USE SIGNAL ;
    PORT
      LAYER M4 ;
        RECT  0 33.456 0.084 33.48 ;
    END
  END a_cfg_data[48]
  PIN a_cfg_data[49]
    DIRECTION OUTPUT ;
    USE SIGNAL ;
    PORT
      LAYER M4 ;
        RECT  0 33.552 0.084 33.576 ;
    END
  END a_cfg_data[49]
  PIN a_cfg_data[4]
    DIRECTION OUTPUT ;
    USE SIGNAL ;
    PORT
      LAYER M4 ;
        RECT  0 41.52 0.084 41.544 ;
    END
  END a_cfg_data[4]
  PIN a_cfg_data[50]
    DIRECTION OUTPUT ;
    USE SIGNAL ;
    PORT
      LAYER M4 ;
        RECT  0 33.648 0.084 33.672 ;
    END
  END a_cfg_data[50]
  PIN a_cfg_data[51]
    DIRECTION OUTPUT ;
    USE SIGNAL ;
    PORT
      LAYER M4 ;
        RECT  0 33.744 0.084 33.768 ;
    END
  END a_cfg_data[51]
  PIN a_cfg_data[52]
    DIRECTION OUTPUT ;
    USE SIGNAL ;
    PORT
      LAYER M4 ;
        RECT  0 36.912 0.084 36.936 ;
    END
  END a_cfg_data[52]
  PIN a_cfg_data[53]
    DIRECTION OUTPUT ;
    USE SIGNAL ;
    PORT
      LAYER M4 ;
        RECT  0 37.008 0.084 37.032 ;
    END
  END a_cfg_data[53]
  PIN a_cfg_data[54]
    DIRECTION OUTPUT ;
    USE SIGNAL ;
    PORT
      LAYER M4 ;
        RECT  0 37.104 0.084 37.128 ;
    END
  END a_cfg_data[54]
  PIN a_cfg_data[55]
    DIRECTION OUTPUT ;
    USE SIGNAL ;
    PORT
      LAYER M4 ;
        RECT  0 37.2 0.084 37.224 ;
    END
  END a_cfg_data[55]
  PIN a_cfg_data[56]
    DIRECTION OUTPUT ;
    USE SIGNAL ;
    PORT
      LAYER M4 ;
        RECT  0 37.296 0.084 37.32 ;
    END
  END a_cfg_data[56]
  PIN a_cfg_data[57]
    DIRECTION OUTPUT ;
    USE SIGNAL ;
    PORT
      LAYER M4 ;
        RECT  0 37.392 0.084 37.416 ;
    END
  END a_cfg_data[57]
  PIN a_cfg_data[58]
    DIRECTION OUTPUT ;
    USE SIGNAL ;
    PORT
      LAYER M4 ;
        RECT  0 37.488 0.084 37.512 ;
    END
  END a_cfg_data[58]
  PIN a_cfg_data[59]
    DIRECTION OUTPUT ;
    USE SIGNAL ;
    PORT
      LAYER M4 ;
        RECT  0 37.584 0.084 37.608 ;
    END
  END a_cfg_data[59]
  PIN a_cfg_data[5]
    DIRECTION OUTPUT ;
    USE SIGNAL ;
    PORT
      LAYER M4 ;
        RECT  0 41.616 0.084 41.64 ;
    END
  END a_cfg_data[5]
  PIN a_cfg_data[60]
    DIRECTION OUTPUT ;
    USE SIGNAL ;
    PORT
      LAYER M4 ;
        RECT  0 37.68 0.084 37.704 ;
    END
  END a_cfg_data[60]
  PIN a_cfg_data[61]
    DIRECTION OUTPUT ;
    USE SIGNAL ;
    PORT
      LAYER M4 ;
        RECT  0 37.776 0.084 37.8 ;
    END
  END a_cfg_data[61]
  PIN a_cfg_data[62]
    DIRECTION OUTPUT ;
    USE SIGNAL ;
    PORT
      LAYER M4 ;
        RECT  0 37.872 0.084 37.896 ;
    END
  END a_cfg_data[62]
  PIN a_cfg_data[63]
    DIRECTION OUTPUT ;
    USE SIGNAL ;
    PORT
      LAYER M4 ;
        RECT  0 37.968 0.084 37.992 ;
    END
  END a_cfg_data[63]
  PIN a_cfg_data[64]
    DIRECTION OUTPUT ;
    USE SIGNAL ;
    PORT
      LAYER M4 ;
        RECT  0 38.064 0.084 38.088 ;
    END
  END a_cfg_data[64]
  PIN a_cfg_data[65]
    DIRECTION OUTPUT ;
    USE SIGNAL ;
    PORT
      LAYER M4 ;
        RECT  0 38.16 0.084 38.184 ;
    END
  END a_cfg_data[65]
  PIN a_cfg_data[66]
    DIRECTION OUTPUT ;
    USE SIGNAL ;
    PORT
      LAYER M4 ;
        RECT  0 38.256 0.084 38.28 ;
    END
  END a_cfg_data[66]
  PIN a_cfg_data[67]
    DIRECTION OUTPUT ;
    USE SIGNAL ;
    PORT
      LAYER M4 ;
        RECT  0 38.352 0.084 38.376 ;
    END
  END a_cfg_data[67]
  PIN a_cfg_data[68]
    DIRECTION OUTPUT ;
    USE SIGNAL ;
    PORT
      LAYER M4 ;
        RECT  0 38.448 0.084 38.472 ;
    END
  END a_cfg_data[68]
  PIN a_cfg_data[69]
    DIRECTION OUTPUT ;
    USE SIGNAL ;
    PORT
      LAYER M4 ;
        RECT  0 38.544 0.084 38.568 ;
    END
  END a_cfg_data[69]
  PIN a_cfg_data[6]
    DIRECTION OUTPUT ;
    USE SIGNAL ;
    PORT
      LAYER M4 ;
        RECT  0 41.712 0.084 41.736 ;
    END
  END a_cfg_data[6]
  PIN a_cfg_data[70]
    DIRECTION OUTPUT ;
    USE SIGNAL ;
    PORT
      LAYER M4 ;
        RECT  0 38.64 0.084 38.664 ;
    END
  END a_cfg_data[70]
  PIN a_cfg_data[71]
    DIRECTION OUTPUT ;
    USE SIGNAL ;
    PORT
      LAYER M4 ;
        RECT  0 38.736 0.084 38.76 ;
    END
  END a_cfg_data[71]
  PIN a_cfg_data[72]
    DIRECTION OUTPUT ;
    USE SIGNAL ;
    PORT
      LAYER M4 ;
        RECT  0 38.832 0.084 38.856 ;
    END
  END a_cfg_data[72]
  PIN a_cfg_data[73]
    DIRECTION OUTPUT ;
    USE SIGNAL ;
    PORT
      LAYER M4 ;
        RECT  0 38.928 0.084 38.952 ;
    END
  END a_cfg_data[73]
  PIN a_cfg_data[74]
    DIRECTION OUTPUT ;
    USE SIGNAL ;
    PORT
      LAYER M4 ;
        RECT  0 39.024 0.084 39.048 ;
    END
  END a_cfg_data[74]
  PIN a_cfg_data[75]
    DIRECTION OUTPUT ;
    USE SIGNAL ;
    PORT
      LAYER M4 ;
        RECT  0 39.12 0.084 39.144 ;
    END
  END a_cfg_data[75]
  PIN a_cfg_data[76]
    DIRECTION OUTPUT ;
    USE SIGNAL ;
    PORT
      LAYER M4 ;
        RECT  0 39.216 0.084 39.24 ;
    END
  END a_cfg_data[76]
  PIN a_cfg_data[77]
    DIRECTION OUTPUT ;
    USE SIGNAL ;
    PORT
      LAYER M4 ;
        RECT  0 39.312 0.084 39.336 ;
    END
  END a_cfg_data[77]
  PIN a_cfg_data[78]
    DIRECTION OUTPUT ;
    USE SIGNAL ;
    PORT
      LAYER M4 ;
        RECT  0 39.408 0.084 39.432 ;
    END
  END a_cfg_data[78]
  PIN a_cfg_data[79]
    DIRECTION OUTPUT ;
    USE SIGNAL ;
    PORT
      LAYER M4 ;
        RECT  0 39.504 0.084 39.528 ;
    END
  END a_cfg_data[79]
  PIN a_cfg_data[7]
    DIRECTION OUTPUT ;
    USE SIGNAL ;
    PORT
      LAYER M4 ;
        RECT  0 41.808 0.084 41.832 ;
    END
  END a_cfg_data[7]
  PIN a_cfg_data[80]
    DIRECTION OUTPUT ;
    USE SIGNAL ;
    PORT
      LAYER M4 ;
        RECT  0 39.6 0.084 39.624 ;
    END
  END a_cfg_data[80]
  PIN a_cfg_data[81]
    DIRECTION OUTPUT ;
    USE SIGNAL ;
    PORT
      LAYER M4 ;
        RECT  0 39.696 0.084 39.72 ;
    END
  END a_cfg_data[81]
  PIN a_cfg_data[82]
    DIRECTION OUTPUT ;
    USE SIGNAL ;
    PORT
      LAYER M4 ;
        RECT  0 39.792 0.084 39.816 ;
    END
  END a_cfg_data[82]
  PIN a_cfg_data[83]
    DIRECTION OUTPUT ;
    USE SIGNAL ;
    PORT
      LAYER M4 ;
        RECT  0 39.888 0.084 39.912 ;
    END
  END a_cfg_data[83]
  PIN a_cfg_data[84]
    DIRECTION OUTPUT ;
    USE SIGNAL ;
    PORT
      LAYER M4 ;
        RECT  0 43.056 0.084 43.08 ;
    END
  END a_cfg_data[84]
  PIN a_cfg_data[85]
    DIRECTION OUTPUT ;
    USE SIGNAL ;
    PORT
      LAYER M4 ;
        RECT  0 43.152 0.084 43.176 ;
    END
  END a_cfg_data[85]
  PIN a_cfg_data[86]
    DIRECTION OUTPUT ;
    USE SIGNAL ;
    PORT
      LAYER M4 ;
        RECT  0 43.248 0.084 43.272 ;
    END
  END a_cfg_data[86]
  PIN a_cfg_data[87]
    DIRECTION OUTPUT ;
    USE SIGNAL ;
    PORT
      LAYER M4 ;
        RECT  0 43.344 0.084 43.368 ;
    END
  END a_cfg_data[87]
  PIN a_cfg_data[88]
    DIRECTION OUTPUT ;
    USE SIGNAL ;
    PORT
      LAYER M4 ;
        RECT  0 43.44 0.084 43.464 ;
    END
  END a_cfg_data[88]
  PIN a_cfg_data[89]
    DIRECTION OUTPUT ;
    USE SIGNAL ;
    PORT
      LAYER M4 ;
        RECT  0 43.536 0.084 43.56 ;
    END
  END a_cfg_data[89]
  PIN a_cfg_data[8]
    DIRECTION OUTPUT ;
    USE SIGNAL ;
    PORT
      LAYER M4 ;
        RECT  0 41.904 0.084 41.928 ;
    END
  END a_cfg_data[8]
  PIN a_cfg_data[90]
    DIRECTION OUTPUT ;
    USE SIGNAL ;
    PORT
      LAYER M4 ;
        RECT  0 43.632 0.084 43.656 ;
    END
  END a_cfg_data[90]
  PIN a_cfg_data[91]
    DIRECTION OUTPUT ;
    USE SIGNAL ;
    PORT
      LAYER M4 ;
        RECT  0 43.728 0.084 43.752 ;
    END
  END a_cfg_data[91]
  PIN a_cfg_data[92]
    DIRECTION OUTPUT ;
    USE SIGNAL ;
    PORT
      LAYER M4 ;
        RECT  0 43.824 0.084 43.848 ;
    END
  END a_cfg_data[92]
  PIN a_cfg_data[93]
    DIRECTION OUTPUT ;
    USE SIGNAL ;
    PORT
      LAYER M4 ;
        RECT  0 43.92 0.084 43.944 ;
    END
  END a_cfg_data[93]
  PIN a_cfg_data[94]
    DIRECTION OUTPUT ;
    USE SIGNAL ;
    PORT
      LAYER M4 ;
        RECT  0 44.016 0.084 44.04 ;
    END
  END a_cfg_data[94]
  PIN a_cfg_data[95]
    DIRECTION OUTPUT ;
    USE SIGNAL ;
    PORT
      LAYER M4 ;
        RECT  0 44.112 0.084 44.136 ;
    END
  END a_cfg_data[95]
  PIN a_cfg_data[96]
    DIRECTION OUTPUT ;
    USE SIGNAL ;
    PORT
      LAYER M4 ;
        RECT  0 44.208 0.084 44.232 ;
    END
  END a_cfg_data[96]
  PIN a_cfg_data[97]
    DIRECTION OUTPUT ;
    USE SIGNAL ;
    PORT
      LAYER M4 ;
        RECT  0 44.304 0.084 44.328 ;
    END
  END a_cfg_data[97]
  PIN a_cfg_data[98]
    DIRECTION OUTPUT ;
    USE SIGNAL ;
    PORT
      LAYER M4 ;
        RECT  0 44.4 0.084 44.424 ;
    END
  END a_cfg_data[98]
  PIN a_cfg_data[99]
    DIRECTION OUTPUT ;
    USE SIGNAL ;
    PORT
      LAYER M4 ;
        RECT  0 44.496 0.084 44.52 ;
    END
  END a_cfg_data[99]
  PIN a_cfg_data[9]
    DIRECTION OUTPUT ;
    USE SIGNAL ;
    PORT
      LAYER M4 ;
        RECT  0 42 0.084 42.024 ;
    END
  END a_cfg_data[9]
  PIN a_cfg_target[0]
    DIRECTION OUTPUT ;
    USE SIGNAL ;
    PORT
      LAYER M4 ;
        RECT  0 25.008 0.084 25.032 ;
    END
  END a_cfg_target[0]
  PIN a_cfg_target[1]
    DIRECTION OUTPUT ;
    USE SIGNAL ;
    PORT
      LAYER M4 ;
        RECT  0 25.104 0.084 25.128 ;
    END
  END a_cfg_target[1]
  PIN a_cfg_target[2]
    DIRECTION OUTPUT ;
    USE SIGNAL ;
    PORT
      LAYER M4 ;
        RECT  0 25.2 0.084 25.224 ;
    END
  END a_cfg_target[2]
  PIN a_cfg_target[3]
    DIRECTION OUTPUT ;
    USE SIGNAL ;
    PORT
      LAYER M4 ;
        RECT  0 25.296 0.084 25.32 ;
    END
  END a_cfg_target[3]
  PIN a_cfg_target[4]
    DIRECTION OUTPUT ;
    USE SIGNAL ;
    PORT
      LAYER M4 ;
        RECT  0 25.392 0.084 25.416 ;
    END
  END a_cfg_target[4]
  PIN a_cfg_target[5]
    DIRECTION OUTPUT ;
    USE SIGNAL ;
    PORT
      LAYER M4 ;
        RECT  0 25.488 0.084 25.512 ;
    END
  END a_cfg_target[5]
  PIN a_cfg_target[6]
    DIRECTION OUTPUT ;
    USE SIGNAL ;
    PORT
      LAYER M4 ;
        RECT  0 25.584 0.084 25.608 ;
    END
  END a_cfg_target[6]
  PIN a_cfg_target[7]
    DIRECTION OUTPUT ;
    USE SIGNAL ;
    PORT
      LAYER M4 ;
        RECT  0 25.68 0.084 25.704 ;
    END
  END a_cfg_target[7]
  PIN a_cfg_v
    DIRECTION OUTPUT ;
    USE SIGNAL ;
    PORT
      LAYER M4 ;
        RECT  0 25.776 0.084 25.8 ;
    END
  END a_cfg_v
  PIN a_desc_base[0]
    DIRECTION OUTPUT ;
    USE SIGNAL ;
    PORT
      LAYER M4 ;
        RECT  0 25.872 0.084 25.896 ;
    END
  END a_desc_base[0]
  PIN a_desc_base[10]
    DIRECTION OUTPUT ;
    USE SIGNAL ;
    PORT
      LAYER M4 ;
        RECT  0 26.832 0.084 26.856 ;
    END
  END a_desc_base[10]
  PIN a_desc_base[11]
    DIRECTION OUTPUT ;
    USE SIGNAL ;
    PORT
      LAYER M4 ;
        RECT  0 17.712 0.084 17.736 ;
    END
  END a_desc_base[11]
  PIN a_desc_base[1]
    DIRECTION OUTPUT ;
    USE SIGNAL ;
    PORT
      LAYER M4 ;
        RECT  0 25.968 0.084 25.992 ;
    END
  END a_desc_base[1]
  PIN a_desc_base[2]
    DIRECTION OUTPUT ;
    USE SIGNAL ;
    PORT
      LAYER M4 ;
        RECT  0 26.064 0.084 26.088 ;
    END
  END a_desc_base[2]
  PIN a_desc_base[3]
    DIRECTION OUTPUT ;
    USE SIGNAL ;
    PORT
      LAYER M4 ;
        RECT  0 26.16 0.084 26.184 ;
    END
  END a_desc_base[3]
  PIN a_desc_base[4]
    DIRECTION OUTPUT ;
    USE SIGNAL ;
    PORT
      LAYER M4 ;
        RECT  0 26.256 0.084 26.28 ;
    END
  END a_desc_base[4]
  PIN a_desc_base[5]
    DIRECTION OUTPUT ;
    USE SIGNAL ;
    PORT
      LAYER M4 ;
        RECT  0 26.352 0.084 26.376 ;
    END
  END a_desc_base[5]
  PIN a_desc_base[6]
    DIRECTION OUTPUT ;
    USE SIGNAL ;
    PORT
      LAYER M4 ;
        RECT  0 26.448 0.084 26.472 ;
    END
  END a_desc_base[6]
  PIN a_desc_base[7]
    DIRECTION OUTPUT ;
    USE SIGNAL ;
    PORT
      LAYER M4 ;
        RECT  0 26.544 0.084 26.568 ;
    END
  END a_desc_base[7]
  PIN a_desc_base[8]
    DIRECTION OUTPUT ;
    USE SIGNAL ;
    PORT
      LAYER M4 ;
        RECT  0 26.64 0.084 26.664 ;
    END
  END a_desc_base[8]
  PIN a_desc_base[9]
    DIRECTION OUTPUT ;
    USE SIGNAL ;
    PORT
      LAYER M4 ;
        RECT  0 26.736 0.084 26.76 ;
    END
  END a_desc_base[9]
  PIN a_desc_limit[0]
    DIRECTION OUTPUT ;
    USE SIGNAL ;
    PORT
      LAYER M4 ;
        RECT  0 17.808 0.084 17.832 ;
    END
  END a_desc_limit[0]
  PIN a_desc_limit[10]
    DIRECTION OUTPUT ;
    USE SIGNAL ;
    PORT
      LAYER M4 ;
        RECT  0 18.768 0.084 18.792 ;
    END
  END a_desc_limit[10]
  PIN a_desc_limit[11]
    DIRECTION OUTPUT ;
    USE SIGNAL ;
    PORT
      LAYER M4 ;
        RECT  0 18.864 0.084 18.888 ;
    END
  END a_desc_limit[11]
  PIN a_desc_limit[12]
    DIRECTION OUTPUT ;
    USE SIGNAL ;
    PORT
      LAYER M4 ;
        RECT  0 18.96 0.084 18.984 ;
    END
  END a_desc_limit[12]
  PIN a_desc_limit[1]
    DIRECTION OUTPUT ;
    USE SIGNAL ;
    PORT
      LAYER M4 ;
        RECT  0 17.904 0.084 17.928 ;
    END
  END a_desc_limit[1]
  PIN a_desc_limit[2]
    DIRECTION OUTPUT ;
    USE SIGNAL ;
    PORT
      LAYER M4 ;
        RECT  0 18 0.084 18.024 ;
    END
  END a_desc_limit[2]
  PIN a_desc_limit[3]
    DIRECTION OUTPUT ;
    USE SIGNAL ;
    PORT
      LAYER M4 ;
        RECT  0 18.096 0.084 18.12 ;
    END
  END a_desc_limit[3]
  PIN a_desc_limit[4]
    DIRECTION OUTPUT ;
    USE SIGNAL ;
    PORT
      LAYER M4 ;
        RECT  0 18.192 0.084 18.216 ;
    END
  END a_desc_limit[4]
  PIN a_desc_limit[5]
    DIRECTION OUTPUT ;
    USE SIGNAL ;
    PORT
      LAYER M4 ;
        RECT  0 18.288 0.084 18.312 ;
    END
  END a_desc_limit[5]
  PIN a_desc_limit[6]
    DIRECTION OUTPUT ;
    USE SIGNAL ;
    PORT
      LAYER M4 ;
        RECT  0 18.384 0.084 18.408 ;
    END
  END a_desc_limit[6]
  PIN a_desc_limit[7]
    DIRECTION OUTPUT ;
    USE SIGNAL ;
    PORT
      LAYER M4 ;
        RECT  0 18.48 0.084 18.504 ;
    END
  END a_desc_limit[7]
  PIN a_desc_limit[8]
    DIRECTION OUTPUT ;
    USE SIGNAL ;
    PORT
      LAYER M4 ;
        RECT  0 18.576 0.084 18.6 ;
    END
  END a_desc_limit[8]
  PIN a_desc_limit[9]
    DIRECTION OUTPUT ;
    USE SIGNAL ;
    PORT
      LAYER M4 ;
        RECT  0 18.672 0.084 18.696 ;
    END
  END a_desc_limit[9]
  PIN a_desc_loops[0]
    DIRECTION OUTPUT ;
    USE SIGNAL ;
    PORT
      LAYER M4 ;
        RECT  0 19.056 0.084 19.08 ;
    END
  END a_desc_loops[0]
  PIN a_desc_loops[10]
    DIRECTION OUTPUT ;
    USE SIGNAL ;
    PORT
      LAYER M4 ;
        RECT  0 20.016 0.084 20.04 ;
    END
  END a_desc_loops[10]
  PIN a_desc_loops[11]
    DIRECTION OUTPUT ;
    USE SIGNAL ;
    PORT
      LAYER M4 ;
        RECT  0 20.112 0.084 20.136 ;
    END
  END a_desc_loops[11]
  PIN a_desc_loops[12]
    DIRECTION OUTPUT ;
    USE SIGNAL ;
    PORT
      LAYER M4 ;
        RECT  0 20.208 0.084 20.232 ;
    END
  END a_desc_loops[12]
  PIN a_desc_loops[13]
    DIRECTION OUTPUT ;
    USE SIGNAL ;
    PORT
      LAYER M4 ;
        RECT  0 20.304 0.084 20.328 ;
    END
  END a_desc_loops[13]
  PIN a_desc_loops[14]
    DIRECTION OUTPUT ;
    USE SIGNAL ;
    PORT
      LAYER M4 ;
        RECT  0 20.4 0.084 20.424 ;
    END
  END a_desc_loops[14]
  PIN a_desc_loops[15]
    DIRECTION OUTPUT ;
    USE SIGNAL ;
    PORT
      LAYER M4 ;
        RECT  0 20.496 0.084 20.52 ;
    END
  END a_desc_loops[15]
  PIN a_desc_loops[1]
    DIRECTION OUTPUT ;
    USE SIGNAL ;
    PORT
      LAYER M4 ;
        RECT  0 19.152 0.084 19.176 ;
    END
  END a_desc_loops[1]
  PIN a_desc_loops[2]
    DIRECTION OUTPUT ;
    USE SIGNAL ;
    PORT
      LAYER M4 ;
        RECT  0 19.248 0.084 19.272 ;
    END
  END a_desc_loops[2]
  PIN a_desc_loops[3]
    DIRECTION OUTPUT ;
    USE SIGNAL ;
    PORT
      LAYER M4 ;
        RECT  0 19.344 0.084 19.368 ;
    END
  END a_desc_loops[3]
  PIN a_desc_loops[4]
    DIRECTION OUTPUT ;
    USE SIGNAL ;
    PORT
      LAYER M4 ;
        RECT  0 19.44 0.084 19.464 ;
    END
  END a_desc_loops[4]
  PIN a_desc_loops[5]
    DIRECTION OUTPUT ;
    USE SIGNAL ;
    PORT
      LAYER M4 ;
        RECT  0 19.536 0.084 19.56 ;
    END
  END a_desc_loops[5]
  PIN a_desc_loops[6]
    DIRECTION OUTPUT ;
    USE SIGNAL ;
    PORT
      LAYER M4 ;
        RECT  0 19.632 0.084 19.656 ;
    END
  END a_desc_loops[6]
  PIN a_desc_loops[7]
    DIRECTION OUTPUT ;
    USE SIGNAL ;
    PORT
      LAYER M4 ;
        RECT  0 19.728 0.084 19.752 ;
    END
  END a_desc_loops[7]
  PIN a_desc_loops[8]
    DIRECTION OUTPUT ;
    USE SIGNAL ;
    PORT
      LAYER M4 ;
        RECT  0 19.824 0.084 19.848 ;
    END
  END a_desc_loops[8]
  PIN a_desc_loops[9]
    DIRECTION OUTPUT ;
    USE SIGNAL ;
    PORT
      LAYER M4 ;
        RECT  0 19.92 0.084 19.944 ;
    END
  END a_desc_loops[9]
  PIN a_desc_v
    DIRECTION OUTPUT ;
    USE SIGNAL ;
    PORT
      LAYER M4 ;
        RECT  0 20.592 0.084 20.616 ;
    END
  END a_desc_v
  PIN a_launch_v
    DIRECTION OUTPUT ;
    USE SIGNAL ;
    PORT
      LAYER M4 ;
        RECT  0 20.688 0.084 20.712 ;
    END
  END a_launch_v
  PIN b_cfg_addr[0]
    DIRECTION OUTPUT ;
    USE SIGNAL ;
    PORT
      LAYER M4 ;
        RECT  69.036 35.28 69.12 35.304 ;
    END
  END b_cfg_addr[0]
  PIN b_cfg_addr[10]
    DIRECTION OUTPUT ;
    USE SIGNAL ;
    PORT
      LAYER M4 ;
        RECT  69.036 36.24 69.12 36.264 ;
    END
  END b_cfg_addr[10]
  PIN b_cfg_addr[11]
    DIRECTION OUTPUT ;
    USE SIGNAL ;
    PORT
      LAYER M4 ;
        RECT  69.036 36.336 69.12 36.36 ;
    END
  END b_cfg_addr[11]
  PIN b_cfg_addr[1]
    DIRECTION OUTPUT ;
    USE SIGNAL ;
    PORT
      LAYER M4 ;
        RECT  69.036 35.376 69.12 35.4 ;
    END
  END b_cfg_addr[1]
  PIN b_cfg_addr[2]
    DIRECTION OUTPUT ;
    USE SIGNAL ;
    PORT
      LAYER M4 ;
        RECT  69.036 35.472 69.12 35.496 ;
    END
  END b_cfg_addr[2]
  PIN b_cfg_addr[3]
    DIRECTION OUTPUT ;
    USE SIGNAL ;
    PORT
      LAYER M4 ;
        RECT  69.036 35.568 69.12 35.592 ;
    END
  END b_cfg_addr[3]
  PIN b_cfg_addr[4]
    DIRECTION OUTPUT ;
    USE SIGNAL ;
    PORT
      LAYER M4 ;
        RECT  69.036 35.664 69.12 35.688 ;
    END
  END b_cfg_addr[4]
  PIN b_cfg_addr[5]
    DIRECTION OUTPUT ;
    USE SIGNAL ;
    PORT
      LAYER M4 ;
        RECT  69.036 35.76 69.12 35.784 ;
    END
  END b_cfg_addr[5]
  PIN b_cfg_addr[6]
    DIRECTION OUTPUT ;
    USE SIGNAL ;
    PORT
      LAYER M4 ;
        RECT  69.036 35.856 69.12 35.88 ;
    END
  END b_cfg_addr[6]
  PIN b_cfg_addr[7]
    DIRECTION OUTPUT ;
    USE SIGNAL ;
    PORT
      LAYER M4 ;
        RECT  69.036 35.952 69.12 35.976 ;
    END
  END b_cfg_addr[7]
  PIN b_cfg_addr[8]
    DIRECTION OUTPUT ;
    USE SIGNAL ;
    PORT
      LAYER M4 ;
        RECT  69.036 36.048 69.12 36.072 ;
    END
  END b_cfg_addr[8]
  PIN b_cfg_addr[9]
    DIRECTION OUTPUT ;
    USE SIGNAL ;
    PORT
      LAYER M4 ;
        RECT  69.036 36.144 69.12 36.168 ;
    END
  END b_cfg_addr[9]
  PIN b_cfg_data[0]
    DIRECTION OUTPUT ;
    USE SIGNAL ;
    PORT
      LAYER M4 ;
        RECT  69.036 36.432 69.12 36.456 ;
    END
  END b_cfg_data[0]
  PIN b_cfg_data[100]
    DIRECTION OUTPUT ;
    USE SIGNAL ;
    PORT
      LAYER M4 ;
        RECT  69.036 46.8 69.12 46.824 ;
    END
  END b_cfg_data[100]
  PIN b_cfg_data[101]
    DIRECTION OUTPUT ;
    USE SIGNAL ;
    PORT
      LAYER M4 ;
        RECT  69.036 46.896 69.12 46.92 ;
    END
  END b_cfg_data[101]
  PIN b_cfg_data[102]
    DIRECTION OUTPUT ;
    USE SIGNAL ;
    PORT
      LAYER M4 ;
        RECT  69.036 46.992 69.12 47.016 ;
    END
  END b_cfg_data[102]
  PIN b_cfg_data[103]
    DIRECTION OUTPUT ;
    USE SIGNAL ;
    PORT
      LAYER M4 ;
        RECT  69.036 47.088 69.12 47.112 ;
    END
  END b_cfg_data[103]
  PIN b_cfg_data[104]
    DIRECTION OUTPUT ;
    USE SIGNAL ;
    PORT
      LAYER M4 ;
        RECT  69.036 47.184 69.12 47.208 ;
    END
  END b_cfg_data[104]
  PIN b_cfg_data[105]
    DIRECTION OUTPUT ;
    USE SIGNAL ;
    PORT
      LAYER M4 ;
        RECT  69.036 47.28 69.12 47.304 ;
    END
  END b_cfg_data[105]
  PIN b_cfg_data[106]
    DIRECTION OUTPUT ;
    USE SIGNAL ;
    PORT
      LAYER M4 ;
        RECT  69.036 47.376 69.12 47.4 ;
    END
  END b_cfg_data[106]
  PIN b_cfg_data[107]
    DIRECTION OUTPUT ;
    USE SIGNAL ;
    PORT
      LAYER M4 ;
        RECT  69.036 47.472 69.12 47.496 ;
    END
  END b_cfg_data[107]
  PIN b_cfg_data[108]
    DIRECTION OUTPUT ;
    USE SIGNAL ;
    PORT
      LAYER M4 ;
        RECT  69.036 47.568 69.12 47.592 ;
    END
  END b_cfg_data[108]
  PIN b_cfg_data[109]
    DIRECTION OUTPUT ;
    USE SIGNAL ;
    PORT
      LAYER M4 ;
        RECT  69.036 47.664 69.12 47.688 ;
    END
  END b_cfg_data[109]
  PIN b_cfg_data[10]
    DIRECTION OUTPUT ;
    USE SIGNAL ;
    PORT
      LAYER M4 ;
        RECT  69.036 37.392 69.12 37.416 ;
    END
  END b_cfg_data[10]
  PIN b_cfg_data[110]
    DIRECTION OUTPUT ;
    USE SIGNAL ;
    PORT
      LAYER M4 ;
        RECT  69.036 47.76 69.12 47.784 ;
    END
  END b_cfg_data[110]
  PIN b_cfg_data[111]
    DIRECTION OUTPUT ;
    USE SIGNAL ;
    PORT
      LAYER M4 ;
        RECT  69.036 47.856 69.12 47.88 ;
    END
  END b_cfg_data[111]
  PIN b_cfg_data[112]
    DIRECTION OUTPUT ;
    USE SIGNAL ;
    PORT
      LAYER M4 ;
        RECT  69.036 47.952 69.12 47.976 ;
    END
  END b_cfg_data[112]
  PIN b_cfg_data[113]
    DIRECTION OUTPUT ;
    USE SIGNAL ;
    PORT
      LAYER M4 ;
        RECT  69.036 48.048 69.12 48.072 ;
    END
  END b_cfg_data[113]
  PIN b_cfg_data[114]
    DIRECTION OUTPUT ;
    USE SIGNAL ;
    PORT
      LAYER M4 ;
        RECT  69.036 48.144 69.12 48.168 ;
    END
  END b_cfg_data[114]
  PIN b_cfg_data[115]
    DIRECTION OUTPUT ;
    USE SIGNAL ;
    PORT
      LAYER M4 ;
        RECT  69.036 48.24 69.12 48.264 ;
    END
  END b_cfg_data[115]
  PIN b_cfg_data[116]
    DIRECTION OUTPUT ;
    USE SIGNAL ;
    PORT
      LAYER M4 ;
        RECT  69.036 29.136 69.12 29.16 ;
    END
  END b_cfg_data[116]
  PIN b_cfg_data[117]
    DIRECTION OUTPUT ;
    USE SIGNAL ;
    PORT
      LAYER M4 ;
        RECT  69.036 29.232 69.12 29.256 ;
    END
  END b_cfg_data[117]
  PIN b_cfg_data[118]
    DIRECTION OUTPUT ;
    USE SIGNAL ;
    PORT
      LAYER M4 ;
        RECT  69.036 29.328 69.12 29.352 ;
    END
  END b_cfg_data[118]
  PIN b_cfg_data[119]
    DIRECTION OUTPUT ;
    USE SIGNAL ;
    PORT
      LAYER M4 ;
        RECT  69.036 29.424 69.12 29.448 ;
    END
  END b_cfg_data[119]
  PIN b_cfg_data[11]
    DIRECTION OUTPUT ;
    USE SIGNAL ;
    PORT
      LAYER M4 ;
        RECT  69.036 37.488 69.12 37.512 ;
    END
  END b_cfg_data[11]
  PIN b_cfg_data[120]
    DIRECTION OUTPUT ;
    USE SIGNAL ;
    PORT
      LAYER M4 ;
        RECT  69.036 29.52 69.12 29.544 ;
    END
  END b_cfg_data[120]
  PIN b_cfg_data[121]
    DIRECTION OUTPUT ;
    USE SIGNAL ;
    PORT
      LAYER M4 ;
        RECT  69.036 29.616 69.12 29.64 ;
    END
  END b_cfg_data[121]
  PIN b_cfg_data[122]
    DIRECTION OUTPUT ;
    USE SIGNAL ;
    PORT
      LAYER M4 ;
        RECT  69.036 29.712 69.12 29.736 ;
    END
  END b_cfg_data[122]
  PIN b_cfg_data[123]
    DIRECTION OUTPUT ;
    USE SIGNAL ;
    PORT
      LAYER M4 ;
        RECT  69.036 29.808 69.12 29.832 ;
    END
  END b_cfg_data[123]
  PIN b_cfg_data[124]
    DIRECTION OUTPUT ;
    USE SIGNAL ;
    PORT
      LAYER M4 ;
        RECT  69.036 29.904 69.12 29.928 ;
    END
  END b_cfg_data[124]
  PIN b_cfg_data[125]
    DIRECTION OUTPUT ;
    USE SIGNAL ;
    PORT
      LAYER M4 ;
        RECT  69.036 30 69.12 30.024 ;
    END
  END b_cfg_data[125]
  PIN b_cfg_data[126]
    DIRECTION OUTPUT ;
    USE SIGNAL ;
    PORT
      LAYER M4 ;
        RECT  69.036 30.096 69.12 30.12 ;
    END
  END b_cfg_data[126]
  PIN b_cfg_data[127]
    DIRECTION OUTPUT ;
    USE SIGNAL ;
    PORT
      LAYER M4 ;
        RECT  69.036 30.192 69.12 30.216 ;
    END
  END b_cfg_data[127]
  PIN b_cfg_data[128]
    DIRECTION OUTPUT ;
    USE SIGNAL ;
    PORT
      LAYER M4 ;
        RECT  69.036 30.288 69.12 30.312 ;
    END
  END b_cfg_data[128]
  PIN b_cfg_data[129]
    DIRECTION OUTPUT ;
    USE SIGNAL ;
    PORT
      LAYER M4 ;
        RECT  69.036 30.384 69.12 30.408 ;
    END
  END b_cfg_data[129]
  PIN b_cfg_data[12]
    DIRECTION OUTPUT ;
    USE SIGNAL ;
    PORT
      LAYER M4 ;
        RECT  69.036 37.584 69.12 37.608 ;
    END
  END b_cfg_data[12]
  PIN b_cfg_data[130]
    DIRECTION OUTPUT ;
    USE SIGNAL ;
    PORT
      LAYER M4 ;
        RECT  69.036 30.48 69.12 30.504 ;
    END
  END b_cfg_data[130]
  PIN b_cfg_data[131]
    DIRECTION OUTPUT ;
    USE SIGNAL ;
    PORT
      LAYER M4 ;
        RECT  69.036 30.576 69.12 30.6 ;
    END
  END b_cfg_data[131]
  PIN b_cfg_data[132]
    DIRECTION OUTPUT ;
    USE SIGNAL ;
    PORT
      LAYER M4 ;
        RECT  69.036 30.672 69.12 30.696 ;
    END
  END b_cfg_data[132]
  PIN b_cfg_data[133]
    DIRECTION OUTPUT ;
    USE SIGNAL ;
    PORT
      LAYER M4 ;
        RECT  69.036 30.768 69.12 30.792 ;
    END
  END b_cfg_data[133]
  PIN b_cfg_data[134]
    DIRECTION OUTPUT ;
    USE SIGNAL ;
    PORT
      LAYER M4 ;
        RECT  69.036 30.864 69.12 30.888 ;
    END
  END b_cfg_data[134]
  PIN b_cfg_data[135]
    DIRECTION OUTPUT ;
    USE SIGNAL ;
    PORT
      LAYER M4 ;
        RECT  69.036 30.96 69.12 30.984 ;
    END
  END b_cfg_data[135]
  PIN b_cfg_data[136]
    DIRECTION OUTPUT ;
    USE SIGNAL ;
    PORT
      LAYER M4 ;
        RECT  69.036 31.056 69.12 31.08 ;
    END
  END b_cfg_data[136]
  PIN b_cfg_data[137]
    DIRECTION OUTPUT ;
    USE SIGNAL ;
    PORT
      LAYER M4 ;
        RECT  69.036 31.152 69.12 31.176 ;
    END
  END b_cfg_data[137]
  PIN b_cfg_data[138]
    DIRECTION OUTPUT ;
    USE SIGNAL ;
    PORT
      LAYER M4 ;
        RECT  69.036 31.248 69.12 31.272 ;
    END
  END b_cfg_data[138]
  PIN b_cfg_data[139]
    DIRECTION OUTPUT ;
    USE SIGNAL ;
    PORT
      LAYER M4 ;
        RECT  69.036 31.344 69.12 31.368 ;
    END
  END b_cfg_data[139]
  PIN b_cfg_data[13]
    DIRECTION OUTPUT ;
    USE SIGNAL ;
    PORT
      LAYER M4 ;
        RECT  69.036 37.68 69.12 37.704 ;
    END
  END b_cfg_data[13]
  PIN b_cfg_data[140]
    DIRECTION OUTPUT ;
    USE SIGNAL ;
    PORT
      LAYER M4 ;
        RECT  69.036 31.44 69.12 31.464 ;
    END
  END b_cfg_data[140]
  PIN b_cfg_data[141]
    DIRECTION OUTPUT ;
    USE SIGNAL ;
    PORT
      LAYER M4 ;
        RECT  69.036 31.536 69.12 31.56 ;
    END
  END b_cfg_data[141]
  PIN b_cfg_data[142]
    DIRECTION OUTPUT ;
    USE SIGNAL ;
    PORT
      LAYER M4 ;
        RECT  69.036 31.632 69.12 31.656 ;
    END
  END b_cfg_data[142]
  PIN b_cfg_data[143]
    DIRECTION OUTPUT ;
    USE SIGNAL ;
    PORT
      LAYER M4 ;
        RECT  69.036 31.728 69.12 31.752 ;
    END
  END b_cfg_data[143]
  PIN b_cfg_data[144]
    DIRECTION OUTPUT ;
    USE SIGNAL ;
    PORT
      LAYER M4 ;
        RECT  69.036 31.824 69.12 31.848 ;
    END
  END b_cfg_data[144]
  PIN b_cfg_data[145]
    DIRECTION OUTPUT ;
    USE SIGNAL ;
    PORT
      LAYER M4 ;
        RECT  69.036 31.92 69.12 31.944 ;
    END
  END b_cfg_data[145]
  PIN b_cfg_data[146]
    DIRECTION OUTPUT ;
    USE SIGNAL ;
    PORT
      LAYER M4 ;
        RECT  69.036 32.016 69.12 32.04 ;
    END
  END b_cfg_data[146]
  PIN b_cfg_data[147]
    DIRECTION OUTPUT ;
    USE SIGNAL ;
    PORT
      LAYER M4 ;
        RECT  69.036 32.112 69.12 32.136 ;
    END
  END b_cfg_data[147]
  PIN b_cfg_data[148]
    DIRECTION OUTPUT ;
    USE SIGNAL ;
    PORT
      LAYER M4 ;
        RECT  69.036 48.336 69.12 48.36 ;
    END
  END b_cfg_data[148]
  PIN b_cfg_data[149]
    DIRECTION OUTPUT ;
    USE SIGNAL ;
    PORT
      LAYER M4 ;
        RECT  69.036 48.432 69.12 48.456 ;
    END
  END b_cfg_data[149]
  PIN b_cfg_data[14]
    DIRECTION OUTPUT ;
    USE SIGNAL ;
    PORT
      LAYER M4 ;
        RECT  69.036 37.776 69.12 37.8 ;
    END
  END b_cfg_data[14]
  PIN b_cfg_data[150]
    DIRECTION OUTPUT ;
    USE SIGNAL ;
    PORT
      LAYER M4 ;
        RECT  69.036 48.528 69.12 48.552 ;
    END
  END b_cfg_data[150]
  PIN b_cfg_data[151]
    DIRECTION OUTPUT ;
    USE SIGNAL ;
    PORT
      LAYER M4 ;
        RECT  69.036 48.624 69.12 48.648 ;
    END
  END b_cfg_data[151]
  PIN b_cfg_data[152]
    DIRECTION OUTPUT ;
    USE SIGNAL ;
    PORT
      LAYER M4 ;
        RECT  69.036 48.72 69.12 48.744 ;
    END
  END b_cfg_data[152]
  PIN b_cfg_data[153]
    DIRECTION OUTPUT ;
    USE SIGNAL ;
    PORT
      LAYER M4 ;
        RECT  69.036 48.816 69.12 48.84 ;
    END
  END b_cfg_data[153]
  PIN b_cfg_data[154]
    DIRECTION OUTPUT ;
    USE SIGNAL ;
    PORT
      LAYER M4 ;
        RECT  69.036 48.912 69.12 48.936 ;
    END
  END b_cfg_data[154]
  PIN b_cfg_data[155]
    DIRECTION OUTPUT ;
    USE SIGNAL ;
    PORT
      LAYER M4 ;
        RECT  69.036 49.008 69.12 49.032 ;
    END
  END b_cfg_data[155]
  PIN b_cfg_data[156]
    DIRECTION OUTPUT ;
    USE SIGNAL ;
    PORT
      LAYER M4 ;
        RECT  69.036 49.104 69.12 49.128 ;
    END
  END b_cfg_data[156]
  PIN b_cfg_data[157]
    DIRECTION OUTPUT ;
    USE SIGNAL ;
    PORT
      LAYER M4 ;
        RECT  69.036 49.2 69.12 49.224 ;
    END
  END b_cfg_data[157]
  PIN b_cfg_data[158]
    DIRECTION OUTPUT ;
    USE SIGNAL ;
    PORT
      LAYER M4 ;
        RECT  69.036 49.296 69.12 49.32 ;
    END
  END b_cfg_data[158]
  PIN b_cfg_data[159]
    DIRECTION OUTPUT ;
    USE SIGNAL ;
    PORT
      LAYER M4 ;
        RECT  69.036 49.392 69.12 49.416 ;
    END
  END b_cfg_data[159]
  PIN b_cfg_data[15]
    DIRECTION OUTPUT ;
    USE SIGNAL ;
    PORT
      LAYER M4 ;
        RECT  69.036 37.872 69.12 37.896 ;
    END
  END b_cfg_data[15]
  PIN b_cfg_data[160]
    DIRECTION OUTPUT ;
    USE SIGNAL ;
    PORT
      LAYER M4 ;
        RECT  69.036 49.488 69.12 49.512 ;
    END
  END b_cfg_data[160]
  PIN b_cfg_data[161]
    DIRECTION OUTPUT ;
    USE SIGNAL ;
    PORT
      LAYER M4 ;
        RECT  69.036 49.584 69.12 49.608 ;
    END
  END b_cfg_data[161]
  PIN b_cfg_data[162]
    DIRECTION OUTPUT ;
    USE SIGNAL ;
    PORT
      LAYER M4 ;
        RECT  69.036 49.68 69.12 49.704 ;
    END
  END b_cfg_data[162]
  PIN b_cfg_data[163]
    DIRECTION OUTPUT ;
    USE SIGNAL ;
    PORT
      LAYER M4 ;
        RECT  69.036 49.776 69.12 49.8 ;
    END
  END b_cfg_data[163]
  PIN b_cfg_data[164]
    DIRECTION OUTPUT ;
    USE SIGNAL ;
    PORT
      LAYER M4 ;
        RECT  69.036 49.872 69.12 49.896 ;
    END
  END b_cfg_data[164]
  PIN b_cfg_data[165]
    DIRECTION OUTPUT ;
    USE SIGNAL ;
    PORT
      LAYER M4 ;
        RECT  69.036 49.968 69.12 49.992 ;
    END
  END b_cfg_data[165]
  PIN b_cfg_data[166]
    DIRECTION OUTPUT ;
    USE SIGNAL ;
    PORT
      LAYER M4 ;
        RECT  69.036 50.064 69.12 50.088 ;
    END
  END b_cfg_data[166]
  PIN b_cfg_data[167]
    DIRECTION OUTPUT ;
    USE SIGNAL ;
    PORT
      LAYER M4 ;
        RECT  69.036 50.16 69.12 50.184 ;
    END
  END b_cfg_data[167]
  PIN b_cfg_data[168]
    DIRECTION OUTPUT ;
    USE SIGNAL ;
    PORT
      LAYER M4 ;
        RECT  69.036 50.256 69.12 50.28 ;
    END
  END b_cfg_data[168]
  PIN b_cfg_data[169]
    DIRECTION OUTPUT ;
    USE SIGNAL ;
    PORT
      LAYER M4 ;
        RECT  69.036 50.352 69.12 50.376 ;
    END
  END b_cfg_data[169]
  PIN b_cfg_data[16]
    DIRECTION OUTPUT ;
    USE SIGNAL ;
    PORT
      LAYER M4 ;
        RECT  69.036 37.968 69.12 37.992 ;
    END
  END b_cfg_data[16]
  PIN b_cfg_data[170]
    DIRECTION OUTPUT ;
    USE SIGNAL ;
    PORT
      LAYER M4 ;
        RECT  69.036 50.448 69.12 50.472 ;
    END
  END b_cfg_data[170]
  PIN b_cfg_data[171]
    DIRECTION OUTPUT ;
    USE SIGNAL ;
    PORT
      LAYER M4 ;
        RECT  69.036 50.544 69.12 50.568 ;
    END
  END b_cfg_data[171]
  PIN b_cfg_data[172]
    DIRECTION OUTPUT ;
    USE SIGNAL ;
    PORT
      LAYER M4 ;
        RECT  69.036 50.64 69.12 50.664 ;
    END
  END b_cfg_data[172]
  PIN b_cfg_data[173]
    DIRECTION OUTPUT ;
    USE SIGNAL ;
    PORT
      LAYER M4 ;
        RECT  69.036 50.736 69.12 50.76 ;
    END
  END b_cfg_data[173]
  PIN b_cfg_data[174]
    DIRECTION OUTPUT ;
    USE SIGNAL ;
    PORT
      LAYER M4 ;
        RECT  69.036 50.832 69.12 50.856 ;
    END
  END b_cfg_data[174]
  PIN b_cfg_data[175]
    DIRECTION OUTPUT ;
    USE SIGNAL ;
    PORT
      LAYER M4 ;
        RECT  69.036 50.928 69.12 50.952 ;
    END
  END b_cfg_data[175]
  PIN b_cfg_data[176]
    DIRECTION OUTPUT ;
    USE SIGNAL ;
    PORT
      LAYER M4 ;
        RECT  69.036 51.024 69.12 51.048 ;
    END
  END b_cfg_data[176]
  PIN b_cfg_data[177]
    DIRECTION OUTPUT ;
    USE SIGNAL ;
    PORT
      LAYER M4 ;
        RECT  69.036 51.12 69.12 51.144 ;
    END
  END b_cfg_data[177]
  PIN b_cfg_data[178]
    DIRECTION OUTPUT ;
    USE SIGNAL ;
    PORT
      LAYER M4 ;
        RECT  69.036 51.216 69.12 51.24 ;
    END
  END b_cfg_data[178]
  PIN b_cfg_data[179]
    DIRECTION OUTPUT ;
    USE SIGNAL ;
    PORT
      LAYER M4 ;
        RECT  69.036 51.312 69.12 51.336 ;
    END
  END b_cfg_data[179]
  PIN b_cfg_data[17]
    DIRECTION OUTPUT ;
    USE SIGNAL ;
    PORT
      LAYER M4 ;
        RECT  69.036 38.064 69.12 38.088 ;
    END
  END b_cfg_data[17]
  PIN b_cfg_data[180]
    DIRECTION OUTPUT ;
    USE SIGNAL ;
    PORT
      LAYER M4 ;
        RECT  69.036 22.992 69.12 23.016 ;
    END
  END b_cfg_data[180]
  PIN b_cfg_data[181]
    DIRECTION OUTPUT ;
    USE SIGNAL ;
    PORT
      LAYER M4 ;
        RECT  69.036 23.088 69.12 23.112 ;
    END
  END b_cfg_data[181]
  PIN b_cfg_data[182]
    DIRECTION OUTPUT ;
    USE SIGNAL ;
    PORT
      LAYER M4 ;
        RECT  69.036 23.184 69.12 23.208 ;
    END
  END b_cfg_data[182]
  PIN b_cfg_data[183]
    DIRECTION OUTPUT ;
    USE SIGNAL ;
    PORT
      LAYER M4 ;
        RECT  69.036 23.28 69.12 23.304 ;
    END
  END b_cfg_data[183]
  PIN b_cfg_data[184]
    DIRECTION OUTPUT ;
    USE SIGNAL ;
    PORT
      LAYER M4 ;
        RECT  69.036 23.376 69.12 23.4 ;
    END
  END b_cfg_data[184]
  PIN b_cfg_data[185]
    DIRECTION OUTPUT ;
    USE SIGNAL ;
    PORT
      LAYER M4 ;
        RECT  69.036 23.472 69.12 23.496 ;
    END
  END b_cfg_data[185]
  PIN b_cfg_data[186]
    DIRECTION OUTPUT ;
    USE SIGNAL ;
    PORT
      LAYER M4 ;
        RECT  69.036 23.568 69.12 23.592 ;
    END
  END b_cfg_data[186]
  PIN b_cfg_data[187]
    DIRECTION OUTPUT ;
    USE SIGNAL ;
    PORT
      LAYER M4 ;
        RECT  69.036 23.664 69.12 23.688 ;
    END
  END b_cfg_data[187]
  PIN b_cfg_data[188]
    DIRECTION OUTPUT ;
    USE SIGNAL ;
    PORT
      LAYER M4 ;
        RECT  69.036 23.76 69.12 23.784 ;
    END
  END b_cfg_data[188]
  PIN b_cfg_data[189]
    DIRECTION OUTPUT ;
    USE SIGNAL ;
    PORT
      LAYER M4 ;
        RECT  69.036 23.856 69.12 23.88 ;
    END
  END b_cfg_data[189]
  PIN b_cfg_data[18]
    DIRECTION OUTPUT ;
    USE SIGNAL ;
    PORT
      LAYER M4 ;
        RECT  69.036 38.16 69.12 38.184 ;
    END
  END b_cfg_data[18]
  PIN b_cfg_data[190]
    DIRECTION OUTPUT ;
    USE SIGNAL ;
    PORT
      LAYER M4 ;
        RECT  69.036 23.952 69.12 23.976 ;
    END
  END b_cfg_data[190]
  PIN b_cfg_data[191]
    DIRECTION OUTPUT ;
    USE SIGNAL ;
    PORT
      LAYER M4 ;
        RECT  69.036 24.048 69.12 24.072 ;
    END
  END b_cfg_data[191]
  PIN b_cfg_data[192]
    DIRECTION OUTPUT ;
    USE SIGNAL ;
    PORT
      LAYER M4 ;
        RECT  69.036 24.144 69.12 24.168 ;
    END
  END b_cfg_data[192]
  PIN b_cfg_data[193]
    DIRECTION OUTPUT ;
    USE SIGNAL ;
    PORT
      LAYER M4 ;
        RECT  69.036 24.24 69.12 24.264 ;
    END
  END b_cfg_data[193]
  PIN b_cfg_data[194]
    DIRECTION OUTPUT ;
    USE SIGNAL ;
    PORT
      LAYER M4 ;
        RECT  69.036 24.336 69.12 24.36 ;
    END
  END b_cfg_data[194]
  PIN b_cfg_data[195]
    DIRECTION OUTPUT ;
    USE SIGNAL ;
    PORT
      LAYER M4 ;
        RECT  69.036 24.432 69.12 24.456 ;
    END
  END b_cfg_data[195]
  PIN b_cfg_data[196]
    DIRECTION OUTPUT ;
    USE SIGNAL ;
    PORT
      LAYER M4 ;
        RECT  69.036 24.528 69.12 24.552 ;
    END
  END b_cfg_data[196]
  PIN b_cfg_data[197]
    DIRECTION OUTPUT ;
    USE SIGNAL ;
    PORT
      LAYER M4 ;
        RECT  69.036 24.624 69.12 24.648 ;
    END
  END b_cfg_data[197]
  PIN b_cfg_data[198]
    DIRECTION OUTPUT ;
    USE SIGNAL ;
    PORT
      LAYER M4 ;
        RECT  69.036 24.72 69.12 24.744 ;
    END
  END b_cfg_data[198]
  PIN b_cfg_data[199]
    DIRECTION OUTPUT ;
    USE SIGNAL ;
    PORT
      LAYER M4 ;
        RECT  69.036 24.816 69.12 24.84 ;
    END
  END b_cfg_data[199]
  PIN b_cfg_data[19]
    DIRECTION OUTPUT ;
    USE SIGNAL ;
    PORT
      LAYER M4 ;
        RECT  69.036 38.256 69.12 38.28 ;
    END
  END b_cfg_data[19]
  PIN b_cfg_data[1]
    DIRECTION OUTPUT ;
    USE SIGNAL ;
    PORT
      LAYER M4 ;
        RECT  69.036 36.528 69.12 36.552 ;
    END
  END b_cfg_data[1]
  PIN b_cfg_data[200]
    DIRECTION OUTPUT ;
    USE SIGNAL ;
    PORT
      LAYER M4 ;
        RECT  69.036 24.912 69.12 24.936 ;
    END
  END b_cfg_data[200]
  PIN b_cfg_data[201]
    DIRECTION OUTPUT ;
    USE SIGNAL ;
    PORT
      LAYER M4 ;
        RECT  69.036 25.008 69.12 25.032 ;
    END
  END b_cfg_data[201]
  PIN b_cfg_data[202]
    DIRECTION OUTPUT ;
    USE SIGNAL ;
    PORT
      LAYER M4 ;
        RECT  69.036 25.104 69.12 25.128 ;
    END
  END b_cfg_data[202]
  PIN b_cfg_data[203]
    DIRECTION OUTPUT ;
    USE SIGNAL ;
    PORT
      LAYER M4 ;
        RECT  69.036 25.2 69.12 25.224 ;
    END
  END b_cfg_data[203]
  PIN b_cfg_data[204]
    DIRECTION OUTPUT ;
    USE SIGNAL ;
    PORT
      LAYER M4 ;
        RECT  69.036 25.296 69.12 25.32 ;
    END
  END b_cfg_data[204]
  PIN b_cfg_data[205]
    DIRECTION OUTPUT ;
    USE SIGNAL ;
    PORT
      LAYER M4 ;
        RECT  69.036 25.392 69.12 25.416 ;
    END
  END b_cfg_data[205]
  PIN b_cfg_data[206]
    DIRECTION OUTPUT ;
    USE SIGNAL ;
    PORT
      LAYER M4 ;
        RECT  69.036 25.488 69.12 25.512 ;
    END
  END b_cfg_data[206]
  PIN b_cfg_data[207]
    DIRECTION OUTPUT ;
    USE SIGNAL ;
    PORT
      LAYER M4 ;
        RECT  69.036 25.584 69.12 25.608 ;
    END
  END b_cfg_data[207]
  PIN b_cfg_data[208]
    DIRECTION OUTPUT ;
    USE SIGNAL ;
    PORT
      LAYER M4 ;
        RECT  69.036 25.68 69.12 25.704 ;
    END
  END b_cfg_data[208]
  PIN b_cfg_data[209]
    DIRECTION OUTPUT ;
    USE SIGNAL ;
    PORT
      LAYER M4 ;
        RECT  69.036 25.776 69.12 25.8 ;
    END
  END b_cfg_data[209]
  PIN b_cfg_data[20]
    DIRECTION OUTPUT ;
    USE SIGNAL ;
    PORT
      LAYER M4 ;
        RECT  69.036 26.064 69.12 26.088 ;
    END
  END b_cfg_data[20]
  PIN b_cfg_data[210]
    DIRECTION OUTPUT ;
    USE SIGNAL ;
    PORT
      LAYER M4 ;
        RECT  69.036 25.872 69.12 25.896 ;
    END
  END b_cfg_data[210]
  PIN b_cfg_data[211]
    DIRECTION OUTPUT ;
    USE SIGNAL ;
    PORT
      LAYER M4 ;
        RECT  69.036 25.968 69.12 25.992 ;
    END
  END b_cfg_data[211]
  PIN b_cfg_data[212]
    DIRECTION OUTPUT ;
    USE SIGNAL ;
    PORT
      LAYER M4 ;
        RECT  69.036 19.92 69.12 19.944 ;
    END
  END b_cfg_data[212]
  PIN b_cfg_data[213]
    DIRECTION OUTPUT ;
    USE SIGNAL ;
    PORT
      LAYER M4 ;
        RECT  69.036 20.016 69.12 20.04 ;
    END
  END b_cfg_data[213]
  PIN b_cfg_data[214]
    DIRECTION OUTPUT ;
    USE SIGNAL ;
    PORT
      LAYER M4 ;
        RECT  69.036 20.112 69.12 20.136 ;
    END
  END b_cfg_data[214]
  PIN b_cfg_data[215]
    DIRECTION OUTPUT ;
    USE SIGNAL ;
    PORT
      LAYER M4 ;
        RECT  69.036 20.208 69.12 20.232 ;
    END
  END b_cfg_data[215]
  PIN b_cfg_data[216]
    DIRECTION OUTPUT ;
    USE SIGNAL ;
    PORT
      LAYER M4 ;
        RECT  69.036 20.304 69.12 20.328 ;
    END
  END b_cfg_data[216]
  PIN b_cfg_data[217]
    DIRECTION OUTPUT ;
    USE SIGNAL ;
    PORT
      LAYER M4 ;
        RECT  69.036 20.4 69.12 20.424 ;
    END
  END b_cfg_data[217]
  PIN b_cfg_data[218]
    DIRECTION OUTPUT ;
    USE SIGNAL ;
    PORT
      LAYER M4 ;
        RECT  69.036 20.496 69.12 20.52 ;
    END
  END b_cfg_data[218]
  PIN b_cfg_data[219]
    DIRECTION OUTPUT ;
    USE SIGNAL ;
    PORT
      LAYER M4 ;
        RECT  69.036 20.592 69.12 20.616 ;
    END
  END b_cfg_data[219]
  PIN b_cfg_data[21]
    DIRECTION OUTPUT ;
    USE SIGNAL ;
    PORT
      LAYER M4 ;
        RECT  69.036 26.16 69.12 26.184 ;
    END
  END b_cfg_data[21]
  PIN b_cfg_data[220]
    DIRECTION OUTPUT ;
    USE SIGNAL ;
    PORT
      LAYER M4 ;
        RECT  69.036 20.688 69.12 20.712 ;
    END
  END b_cfg_data[220]
  PIN b_cfg_data[221]
    DIRECTION OUTPUT ;
    USE SIGNAL ;
    PORT
      LAYER M4 ;
        RECT  69.036 20.784 69.12 20.808 ;
    END
  END b_cfg_data[221]
  PIN b_cfg_data[222]
    DIRECTION OUTPUT ;
    USE SIGNAL ;
    PORT
      LAYER M4 ;
        RECT  69.036 20.88 69.12 20.904 ;
    END
  END b_cfg_data[222]
  PIN b_cfg_data[223]
    DIRECTION OUTPUT ;
    USE SIGNAL ;
    PORT
      LAYER M4 ;
        RECT  69.036 20.976 69.12 21 ;
    END
  END b_cfg_data[223]
  PIN b_cfg_data[224]
    DIRECTION OUTPUT ;
    USE SIGNAL ;
    PORT
      LAYER M4 ;
        RECT  69.036 21.072 69.12 21.096 ;
    END
  END b_cfg_data[224]
  PIN b_cfg_data[225]
    DIRECTION OUTPUT ;
    USE SIGNAL ;
    PORT
      LAYER M4 ;
        RECT  69.036 21.168 69.12 21.192 ;
    END
  END b_cfg_data[225]
  PIN b_cfg_data[226]
    DIRECTION OUTPUT ;
    USE SIGNAL ;
    PORT
      LAYER M4 ;
        RECT  69.036 21.264 69.12 21.288 ;
    END
  END b_cfg_data[226]
  PIN b_cfg_data[227]
    DIRECTION OUTPUT ;
    USE SIGNAL ;
    PORT
      LAYER M4 ;
        RECT  69.036 21.36 69.12 21.384 ;
    END
  END b_cfg_data[227]
  PIN b_cfg_data[228]
    DIRECTION OUTPUT ;
    USE SIGNAL ;
    PORT
      LAYER M4 ;
        RECT  69.036 21.456 69.12 21.48 ;
    END
  END b_cfg_data[228]
  PIN b_cfg_data[229]
    DIRECTION OUTPUT ;
    USE SIGNAL ;
    PORT
      LAYER M4 ;
        RECT  69.036 21.552 69.12 21.576 ;
    END
  END b_cfg_data[229]
  PIN b_cfg_data[22]
    DIRECTION OUTPUT ;
    USE SIGNAL ;
    PORT
      LAYER M4 ;
        RECT  69.036 26.256 69.12 26.28 ;
    END
  END b_cfg_data[22]
  PIN b_cfg_data[230]
    DIRECTION OUTPUT ;
    USE SIGNAL ;
    PORT
      LAYER M4 ;
        RECT  69.036 21.648 69.12 21.672 ;
    END
  END b_cfg_data[230]
  PIN b_cfg_data[231]
    DIRECTION OUTPUT ;
    USE SIGNAL ;
    PORT
      LAYER M4 ;
        RECT  69.036 21.744 69.12 21.768 ;
    END
  END b_cfg_data[231]
  PIN b_cfg_data[232]
    DIRECTION OUTPUT ;
    USE SIGNAL ;
    PORT
      LAYER M4 ;
        RECT  69.036 21.84 69.12 21.864 ;
    END
  END b_cfg_data[232]
  PIN b_cfg_data[233]
    DIRECTION OUTPUT ;
    USE SIGNAL ;
    PORT
      LAYER M4 ;
        RECT  69.036 21.936 69.12 21.96 ;
    END
  END b_cfg_data[233]
  PIN b_cfg_data[234]
    DIRECTION OUTPUT ;
    USE SIGNAL ;
    PORT
      LAYER M4 ;
        RECT  69.036 22.032 69.12 22.056 ;
    END
  END b_cfg_data[234]
  PIN b_cfg_data[235]
    DIRECTION OUTPUT ;
    USE SIGNAL ;
    PORT
      LAYER M4 ;
        RECT  69.036 22.128 69.12 22.152 ;
    END
  END b_cfg_data[235]
  PIN b_cfg_data[236]
    DIRECTION OUTPUT ;
    USE SIGNAL ;
    PORT
      LAYER M4 ;
        RECT  69.036 22.224 69.12 22.248 ;
    END
  END b_cfg_data[236]
  PIN b_cfg_data[237]
    DIRECTION OUTPUT ;
    USE SIGNAL ;
    PORT
      LAYER M4 ;
        RECT  69.036 22.32 69.12 22.344 ;
    END
  END b_cfg_data[237]
  PIN b_cfg_data[238]
    DIRECTION OUTPUT ;
    USE SIGNAL ;
    PORT
      LAYER M4 ;
        RECT  69.036 22.416 69.12 22.44 ;
    END
  END b_cfg_data[238]
  PIN b_cfg_data[239]
    DIRECTION OUTPUT ;
    USE SIGNAL ;
    PORT
      LAYER M4 ;
        RECT  69.036 22.512 69.12 22.536 ;
    END
  END b_cfg_data[239]
  PIN b_cfg_data[23]
    DIRECTION OUTPUT ;
    USE SIGNAL ;
    PORT
      LAYER M4 ;
        RECT  69.036 26.352 69.12 26.376 ;
    END
  END b_cfg_data[23]
  PIN b_cfg_data[240]
    DIRECTION OUTPUT ;
    USE SIGNAL ;
    PORT
      LAYER M4 ;
        RECT  69.036 22.608 69.12 22.632 ;
    END
  END b_cfg_data[240]
  PIN b_cfg_data[241]
    DIRECTION OUTPUT ;
    USE SIGNAL ;
    PORT
      LAYER M4 ;
        RECT  69.036 22.704 69.12 22.728 ;
    END
  END b_cfg_data[241]
  PIN b_cfg_data[242]
    DIRECTION OUTPUT ;
    USE SIGNAL ;
    PORT
      LAYER M4 ;
        RECT  69.036 22.8 69.12 22.824 ;
    END
  END b_cfg_data[242]
  PIN b_cfg_data[243]
    DIRECTION OUTPUT ;
    USE SIGNAL ;
    PORT
      LAYER M4 ;
        RECT  69.036 22.896 69.12 22.92 ;
    END
  END b_cfg_data[243]
  PIN b_cfg_data[244]
    DIRECTION OUTPUT ;
    USE SIGNAL ;
    PORT
      LAYER M4 ;
        RECT  69.036 42.192 69.12 42.216 ;
    END
  END b_cfg_data[244]
  PIN b_cfg_data[245]
    DIRECTION OUTPUT ;
    USE SIGNAL ;
    PORT
      LAYER M4 ;
        RECT  69.036 42.288 69.12 42.312 ;
    END
  END b_cfg_data[245]
  PIN b_cfg_data[246]
    DIRECTION OUTPUT ;
    USE SIGNAL ;
    PORT
      LAYER M4 ;
        RECT  69.036 42.384 69.12 42.408 ;
    END
  END b_cfg_data[246]
  PIN b_cfg_data[247]
    DIRECTION OUTPUT ;
    USE SIGNAL ;
    PORT
      LAYER M4 ;
        RECT  69.036 42.48 69.12 42.504 ;
    END
  END b_cfg_data[247]
  PIN b_cfg_data[248]
    DIRECTION OUTPUT ;
    USE SIGNAL ;
    PORT
      LAYER M4 ;
        RECT  69.036 42.576 69.12 42.6 ;
    END
  END b_cfg_data[248]
  PIN b_cfg_data[249]
    DIRECTION OUTPUT ;
    USE SIGNAL ;
    PORT
      LAYER M4 ;
        RECT  69.036 42.672 69.12 42.696 ;
    END
  END b_cfg_data[249]
  PIN b_cfg_data[24]
    DIRECTION OUTPUT ;
    USE SIGNAL ;
    PORT
      LAYER M4 ;
        RECT  69.036 26.448 69.12 26.472 ;
    END
  END b_cfg_data[24]
  PIN b_cfg_data[250]
    DIRECTION OUTPUT ;
    USE SIGNAL ;
    PORT
      LAYER M4 ;
        RECT  69.036 42.768 69.12 42.792 ;
    END
  END b_cfg_data[250]
  PIN b_cfg_data[251]
    DIRECTION OUTPUT ;
    USE SIGNAL ;
    PORT
      LAYER M4 ;
        RECT  69.036 42.864 69.12 42.888 ;
    END
  END b_cfg_data[251]
  PIN b_cfg_data[252]
    DIRECTION OUTPUT ;
    USE SIGNAL ;
    PORT
      LAYER M4 ;
        RECT  69.036 42.96 69.12 42.984 ;
    END
  END b_cfg_data[252]
  PIN b_cfg_data[253]
    DIRECTION OUTPUT ;
    USE SIGNAL ;
    PORT
      LAYER M4 ;
        RECT  69.036 43.056 69.12 43.08 ;
    END
  END b_cfg_data[253]
  PIN b_cfg_data[254]
    DIRECTION OUTPUT ;
    USE SIGNAL ;
    PORT
      LAYER M4 ;
        RECT  69.036 43.152 69.12 43.176 ;
    END
  END b_cfg_data[254]
  PIN b_cfg_data[255]
    DIRECTION OUTPUT ;
    USE SIGNAL ;
    PORT
      LAYER M4 ;
        RECT  69.036 43.248 69.12 43.272 ;
    END
  END b_cfg_data[255]
  PIN b_cfg_data[25]
    DIRECTION OUTPUT ;
    USE SIGNAL ;
    PORT
      LAYER M4 ;
        RECT  69.036 26.544 69.12 26.568 ;
    END
  END b_cfg_data[25]
  PIN b_cfg_data[26]
    DIRECTION OUTPUT ;
    USE SIGNAL ;
    PORT
      LAYER M4 ;
        RECT  69.036 26.64 69.12 26.664 ;
    END
  END b_cfg_data[26]
  PIN b_cfg_data[27]
    DIRECTION OUTPUT ;
    USE SIGNAL ;
    PORT
      LAYER M4 ;
        RECT  69.036 26.736 69.12 26.76 ;
    END
  END b_cfg_data[27]
  PIN b_cfg_data[28]
    DIRECTION OUTPUT ;
    USE SIGNAL ;
    PORT
      LAYER M4 ;
        RECT  69.036 26.832 69.12 26.856 ;
    END
  END b_cfg_data[28]
  PIN b_cfg_data[29]
    DIRECTION OUTPUT ;
    USE SIGNAL ;
    PORT
      LAYER M4 ;
        RECT  69.036 26.928 69.12 26.952 ;
    END
  END b_cfg_data[29]
  PIN b_cfg_data[2]
    DIRECTION OUTPUT ;
    USE SIGNAL ;
    PORT
      LAYER M4 ;
        RECT  69.036 36.624 69.12 36.648 ;
    END
  END b_cfg_data[2]
  PIN b_cfg_data[30]
    DIRECTION OUTPUT ;
    USE SIGNAL ;
    PORT
      LAYER M4 ;
        RECT  69.036 27.024 69.12 27.048 ;
    END
  END b_cfg_data[30]
  PIN b_cfg_data[31]
    DIRECTION OUTPUT ;
    USE SIGNAL ;
    PORT
      LAYER M4 ;
        RECT  69.036 27.12 69.12 27.144 ;
    END
  END b_cfg_data[31]
  PIN b_cfg_data[32]
    DIRECTION OUTPUT ;
    USE SIGNAL ;
    PORT
      LAYER M4 ;
        RECT  69.036 27.216 69.12 27.24 ;
    END
  END b_cfg_data[32]
  PIN b_cfg_data[33]
    DIRECTION OUTPUT ;
    USE SIGNAL ;
    PORT
      LAYER M4 ;
        RECT  69.036 27.312 69.12 27.336 ;
    END
  END b_cfg_data[33]
  PIN b_cfg_data[34]
    DIRECTION OUTPUT ;
    USE SIGNAL ;
    PORT
      LAYER M4 ;
        RECT  69.036 27.408 69.12 27.432 ;
    END
  END b_cfg_data[34]
  PIN b_cfg_data[35]
    DIRECTION OUTPUT ;
    USE SIGNAL ;
    PORT
      LAYER M4 ;
        RECT  69.036 27.504 69.12 27.528 ;
    END
  END b_cfg_data[35]
  PIN b_cfg_data[36]
    DIRECTION OUTPUT ;
    USE SIGNAL ;
    PORT
      LAYER M4 ;
        RECT  69.036 27.6 69.12 27.624 ;
    END
  END b_cfg_data[36]
  PIN b_cfg_data[37]
    DIRECTION OUTPUT ;
    USE SIGNAL ;
    PORT
      LAYER M4 ;
        RECT  69.036 27.696 69.12 27.72 ;
    END
  END b_cfg_data[37]
  PIN b_cfg_data[38]
    DIRECTION OUTPUT ;
    USE SIGNAL ;
    PORT
      LAYER M4 ;
        RECT  69.036 27.792 69.12 27.816 ;
    END
  END b_cfg_data[38]
  PIN b_cfg_data[39]
    DIRECTION OUTPUT ;
    USE SIGNAL ;
    PORT
      LAYER M4 ;
        RECT  69.036 27.888 69.12 27.912 ;
    END
  END b_cfg_data[39]
  PIN b_cfg_data[3]
    DIRECTION OUTPUT ;
    USE SIGNAL ;
    PORT
      LAYER M4 ;
        RECT  69.036 36.72 69.12 36.744 ;
    END
  END b_cfg_data[3]
  PIN b_cfg_data[40]
    DIRECTION OUTPUT ;
    USE SIGNAL ;
    PORT
      LAYER M4 ;
        RECT  69.036 27.984 69.12 28.008 ;
    END
  END b_cfg_data[40]
  PIN b_cfg_data[41]
    DIRECTION OUTPUT ;
    USE SIGNAL ;
    PORT
      LAYER M4 ;
        RECT  69.036 28.08 69.12 28.104 ;
    END
  END b_cfg_data[41]
  PIN b_cfg_data[42]
    DIRECTION OUTPUT ;
    USE SIGNAL ;
    PORT
      LAYER M4 ;
        RECT  69.036 28.176 69.12 28.2 ;
    END
  END b_cfg_data[42]
  PIN b_cfg_data[43]
    DIRECTION OUTPUT ;
    USE SIGNAL ;
    PORT
      LAYER M4 ;
        RECT  69.036 28.272 69.12 28.296 ;
    END
  END b_cfg_data[43]
  PIN b_cfg_data[44]
    DIRECTION OUTPUT ;
    USE SIGNAL ;
    PORT
      LAYER M4 ;
        RECT  69.036 28.368 69.12 28.392 ;
    END
  END b_cfg_data[44]
  PIN b_cfg_data[45]
    DIRECTION OUTPUT ;
    USE SIGNAL ;
    PORT
      LAYER M4 ;
        RECT  69.036 28.464 69.12 28.488 ;
    END
  END b_cfg_data[45]
  PIN b_cfg_data[46]
    DIRECTION OUTPUT ;
    USE SIGNAL ;
    PORT
      LAYER M4 ;
        RECT  69.036 28.56 69.12 28.584 ;
    END
  END b_cfg_data[46]
  PIN b_cfg_data[47]
    DIRECTION OUTPUT ;
    USE SIGNAL ;
    PORT
      LAYER M4 ;
        RECT  69.036 28.656 69.12 28.68 ;
    END
  END b_cfg_data[47]
  PIN b_cfg_data[48]
    DIRECTION OUTPUT ;
    USE SIGNAL ;
    PORT
      LAYER M4 ;
        RECT  69.036 28.752 69.12 28.776 ;
    END
  END b_cfg_data[48]
  PIN b_cfg_data[49]
    DIRECTION OUTPUT ;
    USE SIGNAL ;
    PORT
      LAYER M4 ;
        RECT  69.036 28.848 69.12 28.872 ;
    END
  END b_cfg_data[49]
  PIN b_cfg_data[4]
    DIRECTION OUTPUT ;
    USE SIGNAL ;
    PORT
      LAYER M4 ;
        RECT  69.036 36.816 69.12 36.84 ;
    END
  END b_cfg_data[4]
  PIN b_cfg_data[50]
    DIRECTION OUTPUT ;
    USE SIGNAL ;
    PORT
      LAYER M4 ;
        RECT  69.036 28.944 69.12 28.968 ;
    END
  END b_cfg_data[50]
  PIN b_cfg_data[51]
    DIRECTION OUTPUT ;
    USE SIGNAL ;
    PORT
      LAYER M4 ;
        RECT  69.036 29.04 69.12 29.064 ;
    END
  END b_cfg_data[51]
  PIN b_cfg_data[52]
    DIRECTION OUTPUT ;
    USE SIGNAL ;
    PORT
      LAYER M4 ;
        RECT  69.036 32.208 69.12 32.232 ;
    END
  END b_cfg_data[52]
  PIN b_cfg_data[53]
    DIRECTION OUTPUT ;
    USE SIGNAL ;
    PORT
      LAYER M4 ;
        RECT  69.036 32.304 69.12 32.328 ;
    END
  END b_cfg_data[53]
  PIN b_cfg_data[54]
    DIRECTION OUTPUT ;
    USE SIGNAL ;
    PORT
      LAYER M4 ;
        RECT  69.036 32.4 69.12 32.424 ;
    END
  END b_cfg_data[54]
  PIN b_cfg_data[55]
    DIRECTION OUTPUT ;
    USE SIGNAL ;
    PORT
      LAYER M4 ;
        RECT  69.036 32.496 69.12 32.52 ;
    END
  END b_cfg_data[55]
  PIN b_cfg_data[56]
    DIRECTION OUTPUT ;
    USE SIGNAL ;
    PORT
      LAYER M4 ;
        RECT  69.036 32.592 69.12 32.616 ;
    END
  END b_cfg_data[56]
  PIN b_cfg_data[57]
    DIRECTION OUTPUT ;
    USE SIGNAL ;
    PORT
      LAYER M4 ;
        RECT  69.036 32.688 69.12 32.712 ;
    END
  END b_cfg_data[57]
  PIN b_cfg_data[58]
    DIRECTION OUTPUT ;
    USE SIGNAL ;
    PORT
      LAYER M4 ;
        RECT  69.036 32.784 69.12 32.808 ;
    END
  END b_cfg_data[58]
  PIN b_cfg_data[59]
    DIRECTION OUTPUT ;
    USE SIGNAL ;
    PORT
      LAYER M4 ;
        RECT  69.036 32.88 69.12 32.904 ;
    END
  END b_cfg_data[59]
  PIN b_cfg_data[5]
    DIRECTION OUTPUT ;
    USE SIGNAL ;
    PORT
      LAYER M4 ;
        RECT  69.036 36.912 69.12 36.936 ;
    END
  END b_cfg_data[5]
  PIN b_cfg_data[60]
    DIRECTION OUTPUT ;
    USE SIGNAL ;
    PORT
      LAYER M4 ;
        RECT  69.036 32.976 69.12 33 ;
    END
  END b_cfg_data[60]
  PIN b_cfg_data[61]
    DIRECTION OUTPUT ;
    USE SIGNAL ;
    PORT
      LAYER M4 ;
        RECT  69.036 33.072 69.12 33.096 ;
    END
  END b_cfg_data[61]
  PIN b_cfg_data[62]
    DIRECTION OUTPUT ;
    USE SIGNAL ;
    PORT
      LAYER M4 ;
        RECT  69.036 33.168 69.12 33.192 ;
    END
  END b_cfg_data[62]
  PIN b_cfg_data[63]
    DIRECTION OUTPUT ;
    USE SIGNAL ;
    PORT
      LAYER M4 ;
        RECT  69.036 33.264 69.12 33.288 ;
    END
  END b_cfg_data[63]
  PIN b_cfg_data[64]
    DIRECTION OUTPUT ;
    USE SIGNAL ;
    PORT
      LAYER M4 ;
        RECT  69.036 33.36 69.12 33.384 ;
    END
  END b_cfg_data[64]
  PIN b_cfg_data[65]
    DIRECTION OUTPUT ;
    USE SIGNAL ;
    PORT
      LAYER M4 ;
        RECT  69.036 33.456 69.12 33.48 ;
    END
  END b_cfg_data[65]
  PIN b_cfg_data[66]
    DIRECTION OUTPUT ;
    USE SIGNAL ;
    PORT
      LAYER M4 ;
        RECT  69.036 33.552 69.12 33.576 ;
    END
  END b_cfg_data[66]
  PIN b_cfg_data[67]
    DIRECTION OUTPUT ;
    USE SIGNAL ;
    PORT
      LAYER M4 ;
        RECT  69.036 33.648 69.12 33.672 ;
    END
  END b_cfg_data[67]
  PIN b_cfg_data[68]
    DIRECTION OUTPUT ;
    USE SIGNAL ;
    PORT
      LAYER M4 ;
        RECT  69.036 33.744 69.12 33.768 ;
    END
  END b_cfg_data[68]
  PIN b_cfg_data[69]
    DIRECTION OUTPUT ;
    USE SIGNAL ;
    PORT
      LAYER M4 ;
        RECT  69.036 33.84 69.12 33.864 ;
    END
  END b_cfg_data[69]
  PIN b_cfg_data[6]
    DIRECTION OUTPUT ;
    USE SIGNAL ;
    PORT
      LAYER M4 ;
        RECT  69.036 37.008 69.12 37.032 ;
    END
  END b_cfg_data[6]
  PIN b_cfg_data[70]
    DIRECTION OUTPUT ;
    USE SIGNAL ;
    PORT
      LAYER M4 ;
        RECT  69.036 33.936 69.12 33.96 ;
    END
  END b_cfg_data[70]
  PIN b_cfg_data[71]
    DIRECTION OUTPUT ;
    USE SIGNAL ;
    PORT
      LAYER M4 ;
        RECT  69.036 34.032 69.12 34.056 ;
    END
  END b_cfg_data[71]
  PIN b_cfg_data[72]
    DIRECTION OUTPUT ;
    USE SIGNAL ;
    PORT
      LAYER M4 ;
        RECT  69.036 34.128 69.12 34.152 ;
    END
  END b_cfg_data[72]
  PIN b_cfg_data[73]
    DIRECTION OUTPUT ;
    USE SIGNAL ;
    PORT
      LAYER M4 ;
        RECT  69.036 34.224 69.12 34.248 ;
    END
  END b_cfg_data[73]
  PIN b_cfg_data[74]
    DIRECTION OUTPUT ;
    USE SIGNAL ;
    PORT
      LAYER M4 ;
        RECT  69.036 34.32 69.12 34.344 ;
    END
  END b_cfg_data[74]
  PIN b_cfg_data[75]
    DIRECTION OUTPUT ;
    USE SIGNAL ;
    PORT
      LAYER M4 ;
        RECT  69.036 34.416 69.12 34.44 ;
    END
  END b_cfg_data[75]
  PIN b_cfg_data[76]
    DIRECTION OUTPUT ;
    USE SIGNAL ;
    PORT
      LAYER M4 ;
        RECT  69.036 34.512 69.12 34.536 ;
    END
  END b_cfg_data[76]
  PIN b_cfg_data[77]
    DIRECTION OUTPUT ;
    USE SIGNAL ;
    PORT
      LAYER M4 ;
        RECT  69.036 34.608 69.12 34.632 ;
    END
  END b_cfg_data[77]
  PIN b_cfg_data[78]
    DIRECTION OUTPUT ;
    USE SIGNAL ;
    PORT
      LAYER M4 ;
        RECT  69.036 34.704 69.12 34.728 ;
    END
  END b_cfg_data[78]
  PIN b_cfg_data[79]
    DIRECTION OUTPUT ;
    USE SIGNAL ;
    PORT
      LAYER M4 ;
        RECT  69.036 34.8 69.12 34.824 ;
    END
  END b_cfg_data[79]
  PIN b_cfg_data[7]
    DIRECTION OUTPUT ;
    USE SIGNAL ;
    PORT
      LAYER M4 ;
        RECT  69.036 37.104 69.12 37.128 ;
    END
  END b_cfg_data[7]
  PIN b_cfg_data[80]
    DIRECTION OUTPUT ;
    USE SIGNAL ;
    PORT
      LAYER M4 ;
        RECT  69.036 34.896 69.12 34.92 ;
    END
  END b_cfg_data[80]
  PIN b_cfg_data[81]
    DIRECTION OUTPUT ;
    USE SIGNAL ;
    PORT
      LAYER M4 ;
        RECT  69.036 34.992 69.12 35.016 ;
    END
  END b_cfg_data[81]
  PIN b_cfg_data[82]
    DIRECTION OUTPUT ;
    USE SIGNAL ;
    PORT
      LAYER M4 ;
        RECT  69.036 35.088 69.12 35.112 ;
    END
  END b_cfg_data[82]
  PIN b_cfg_data[83]
    DIRECTION OUTPUT ;
    USE SIGNAL ;
    PORT
      LAYER M4 ;
        RECT  69.036 35.184 69.12 35.208 ;
    END
  END b_cfg_data[83]
  PIN b_cfg_data[84]
    DIRECTION OUTPUT ;
    USE SIGNAL ;
    PORT
      LAYER M4 ;
        RECT  69.036 45.264 69.12 45.288 ;
    END
  END b_cfg_data[84]
  PIN b_cfg_data[85]
    DIRECTION OUTPUT ;
    USE SIGNAL ;
    PORT
      LAYER M4 ;
        RECT  69.036 45.36 69.12 45.384 ;
    END
  END b_cfg_data[85]
  PIN b_cfg_data[86]
    DIRECTION OUTPUT ;
    USE SIGNAL ;
    PORT
      LAYER M4 ;
        RECT  69.036 45.456 69.12 45.48 ;
    END
  END b_cfg_data[86]
  PIN b_cfg_data[87]
    DIRECTION OUTPUT ;
    USE SIGNAL ;
    PORT
      LAYER M4 ;
        RECT  69.036 45.552 69.12 45.576 ;
    END
  END b_cfg_data[87]
  PIN b_cfg_data[88]
    DIRECTION OUTPUT ;
    USE SIGNAL ;
    PORT
      LAYER M4 ;
        RECT  69.036 45.648 69.12 45.672 ;
    END
  END b_cfg_data[88]
  PIN b_cfg_data[89]
    DIRECTION OUTPUT ;
    USE SIGNAL ;
    PORT
      LAYER M4 ;
        RECT  69.036 45.744 69.12 45.768 ;
    END
  END b_cfg_data[89]
  PIN b_cfg_data[8]
    DIRECTION OUTPUT ;
    USE SIGNAL ;
    PORT
      LAYER M4 ;
        RECT  69.036 37.2 69.12 37.224 ;
    END
  END b_cfg_data[8]
  PIN b_cfg_data[90]
    DIRECTION OUTPUT ;
    USE SIGNAL ;
    PORT
      LAYER M4 ;
        RECT  69.036 45.84 69.12 45.864 ;
    END
  END b_cfg_data[90]
  PIN b_cfg_data[91]
    DIRECTION OUTPUT ;
    USE SIGNAL ;
    PORT
      LAYER M4 ;
        RECT  69.036 45.936 69.12 45.96 ;
    END
  END b_cfg_data[91]
  PIN b_cfg_data[92]
    DIRECTION OUTPUT ;
    USE SIGNAL ;
    PORT
      LAYER M4 ;
        RECT  69.036 46.032 69.12 46.056 ;
    END
  END b_cfg_data[92]
  PIN b_cfg_data[93]
    DIRECTION OUTPUT ;
    USE SIGNAL ;
    PORT
      LAYER M4 ;
        RECT  69.036 46.128 69.12 46.152 ;
    END
  END b_cfg_data[93]
  PIN b_cfg_data[94]
    DIRECTION OUTPUT ;
    USE SIGNAL ;
    PORT
      LAYER M4 ;
        RECT  69.036 46.224 69.12 46.248 ;
    END
  END b_cfg_data[94]
  PIN b_cfg_data[95]
    DIRECTION OUTPUT ;
    USE SIGNAL ;
    PORT
      LAYER M4 ;
        RECT  69.036 46.32 69.12 46.344 ;
    END
  END b_cfg_data[95]
  PIN b_cfg_data[96]
    DIRECTION OUTPUT ;
    USE SIGNAL ;
    PORT
      LAYER M4 ;
        RECT  69.036 46.416 69.12 46.44 ;
    END
  END b_cfg_data[96]
  PIN b_cfg_data[97]
    DIRECTION OUTPUT ;
    USE SIGNAL ;
    PORT
      LAYER M4 ;
        RECT  69.036 46.512 69.12 46.536 ;
    END
  END b_cfg_data[97]
  PIN b_cfg_data[98]
    DIRECTION OUTPUT ;
    USE SIGNAL ;
    PORT
      LAYER M4 ;
        RECT  69.036 46.608 69.12 46.632 ;
    END
  END b_cfg_data[98]
  PIN b_cfg_data[99]
    DIRECTION OUTPUT ;
    USE SIGNAL ;
    PORT
      LAYER M4 ;
        RECT  69.036 46.704 69.12 46.728 ;
    END
  END b_cfg_data[99]
  PIN b_cfg_data[9]
    DIRECTION OUTPUT ;
    USE SIGNAL ;
    PORT
      LAYER M4 ;
        RECT  69.036 37.296 69.12 37.32 ;
    END
  END b_cfg_data[9]
  PIN b_cfg_target[0]
    DIRECTION OUTPUT ;
    USE SIGNAL ;
    PORT
      LAYER M4 ;
        RECT  69.036 43.344 69.12 43.368 ;
    END
  END b_cfg_target[0]
  PIN b_cfg_target[1]
    DIRECTION OUTPUT ;
    USE SIGNAL ;
    PORT
      LAYER M4 ;
        RECT  69.036 43.44 69.12 43.464 ;
    END
  END b_cfg_target[1]
  PIN b_cfg_target[2]
    DIRECTION OUTPUT ;
    USE SIGNAL ;
    PORT
      LAYER M4 ;
        RECT  69.036 43.536 69.12 43.56 ;
    END
  END b_cfg_target[2]
  PIN b_cfg_target[3]
    DIRECTION OUTPUT ;
    USE SIGNAL ;
    PORT
      LAYER M4 ;
        RECT  69.036 43.632 69.12 43.656 ;
    END
  END b_cfg_target[3]
  PIN b_cfg_target[4]
    DIRECTION OUTPUT ;
    USE SIGNAL ;
    PORT
      LAYER M4 ;
        RECT  69.036 43.728 69.12 43.752 ;
    END
  END b_cfg_target[4]
  PIN b_cfg_target[5]
    DIRECTION OUTPUT ;
    USE SIGNAL ;
    PORT
      LAYER M4 ;
        RECT  69.036 43.824 69.12 43.848 ;
    END
  END b_cfg_target[5]
  PIN b_cfg_target[6]
    DIRECTION OUTPUT ;
    USE SIGNAL ;
    PORT
      LAYER M4 ;
        RECT  69.036 43.92 69.12 43.944 ;
    END
  END b_cfg_target[6]
  PIN b_cfg_target[7]
    DIRECTION OUTPUT ;
    USE SIGNAL ;
    PORT
      LAYER M4 ;
        RECT  69.036 44.016 69.12 44.04 ;
    END
  END b_cfg_target[7]
  PIN b_cfg_v
    DIRECTION OUTPUT ;
    USE SIGNAL ;
    PORT
      LAYER M4 ;
        RECT  69.036 44.112 69.12 44.136 ;
    END
  END b_cfg_v
  PIN b_desc_base[0]
    DIRECTION OUTPUT ;
    USE SIGNAL ;
    PORT
      LAYER M4 ;
        RECT  69.036 44.208 69.12 44.232 ;
    END
  END b_desc_base[0]
  PIN b_desc_base[10]
    DIRECTION OUTPUT ;
    USE SIGNAL ;
    PORT
      LAYER M4 ;
        RECT  69.036 45.168 69.12 45.192 ;
    END
  END b_desc_base[10]
  PIN b_desc_base[11]
    DIRECTION OUTPUT ;
    USE SIGNAL ;
    PORT
      LAYER M4 ;
        RECT  69.036 39.12 69.12 39.144 ;
    END
  END b_desc_base[11]
  PIN b_desc_base[1]
    DIRECTION OUTPUT ;
    USE SIGNAL ;
    PORT
      LAYER M4 ;
        RECT  69.036 44.304 69.12 44.328 ;
    END
  END b_desc_base[1]
  PIN b_desc_base[2]
    DIRECTION OUTPUT ;
    USE SIGNAL ;
    PORT
      LAYER M4 ;
        RECT  69.036 44.4 69.12 44.424 ;
    END
  END b_desc_base[2]
  PIN b_desc_base[3]
    DIRECTION OUTPUT ;
    USE SIGNAL ;
    PORT
      LAYER M4 ;
        RECT  69.036 44.496 69.12 44.52 ;
    END
  END b_desc_base[3]
  PIN b_desc_base[4]
    DIRECTION OUTPUT ;
    USE SIGNAL ;
    PORT
      LAYER M4 ;
        RECT  69.036 44.592 69.12 44.616 ;
    END
  END b_desc_base[4]
  PIN b_desc_base[5]
    DIRECTION OUTPUT ;
    USE SIGNAL ;
    PORT
      LAYER M4 ;
        RECT  69.036 44.688 69.12 44.712 ;
    END
  END b_desc_base[5]
  PIN b_desc_base[6]
    DIRECTION OUTPUT ;
    USE SIGNAL ;
    PORT
      LAYER M4 ;
        RECT  69.036 44.784 69.12 44.808 ;
    END
  END b_desc_base[6]
  PIN b_desc_base[7]
    DIRECTION OUTPUT ;
    USE SIGNAL ;
    PORT
      LAYER M4 ;
        RECT  69.036 44.88 69.12 44.904 ;
    END
  END b_desc_base[7]
  PIN b_desc_base[8]
    DIRECTION OUTPUT ;
    USE SIGNAL ;
    PORT
      LAYER M4 ;
        RECT  69.036 44.976 69.12 45 ;
    END
  END b_desc_base[8]
  PIN b_desc_base[9]
    DIRECTION OUTPUT ;
    USE SIGNAL ;
    PORT
      LAYER M4 ;
        RECT  69.036 45.072 69.12 45.096 ;
    END
  END b_desc_base[9]
  PIN b_desc_limit[0]
    DIRECTION OUTPUT ;
    USE SIGNAL ;
    PORT
      LAYER M4 ;
        RECT  69.036 39.216 69.12 39.24 ;
    END
  END b_desc_limit[0]
  PIN b_desc_limit[10]
    DIRECTION OUTPUT ;
    USE SIGNAL ;
    PORT
      LAYER M4 ;
        RECT  69.036 40.176 69.12 40.2 ;
    END
  END b_desc_limit[10]
  PIN b_desc_limit[11]
    DIRECTION OUTPUT ;
    USE SIGNAL ;
    PORT
      LAYER M4 ;
        RECT  69.036 40.272 69.12 40.296 ;
    END
  END b_desc_limit[11]
  PIN b_desc_limit[12]
    DIRECTION OUTPUT ;
    USE SIGNAL ;
    PORT
      LAYER M4 ;
        RECT  69.036 40.368 69.12 40.392 ;
    END
  END b_desc_limit[12]
  PIN b_desc_limit[1]
    DIRECTION OUTPUT ;
    USE SIGNAL ;
    PORT
      LAYER M4 ;
        RECT  69.036 39.312 69.12 39.336 ;
    END
  END b_desc_limit[1]
  PIN b_desc_limit[2]
    DIRECTION OUTPUT ;
    USE SIGNAL ;
    PORT
      LAYER M4 ;
        RECT  69.036 39.408 69.12 39.432 ;
    END
  END b_desc_limit[2]
  PIN b_desc_limit[3]
    DIRECTION OUTPUT ;
    USE SIGNAL ;
    PORT
      LAYER M4 ;
        RECT  69.036 39.504 69.12 39.528 ;
    END
  END b_desc_limit[3]
  PIN b_desc_limit[4]
    DIRECTION OUTPUT ;
    USE SIGNAL ;
    PORT
      LAYER M4 ;
        RECT  69.036 39.6 69.12 39.624 ;
    END
  END b_desc_limit[4]
  PIN b_desc_limit[5]
    DIRECTION OUTPUT ;
    USE SIGNAL ;
    PORT
      LAYER M4 ;
        RECT  69.036 39.696 69.12 39.72 ;
    END
  END b_desc_limit[5]
  PIN b_desc_limit[6]
    DIRECTION OUTPUT ;
    USE SIGNAL ;
    PORT
      LAYER M4 ;
        RECT  69.036 39.792 69.12 39.816 ;
    END
  END b_desc_limit[6]
  PIN b_desc_limit[7]
    DIRECTION OUTPUT ;
    USE SIGNAL ;
    PORT
      LAYER M4 ;
        RECT  69.036 39.888 69.12 39.912 ;
    END
  END b_desc_limit[7]
  PIN b_desc_limit[8]
    DIRECTION OUTPUT ;
    USE SIGNAL ;
    PORT
      LAYER M4 ;
        RECT  69.036 39.984 69.12 40.008 ;
    END
  END b_desc_limit[8]
  PIN b_desc_limit[9]
    DIRECTION OUTPUT ;
    USE SIGNAL ;
    PORT
      LAYER M4 ;
        RECT  69.036 40.08 69.12 40.104 ;
    END
  END b_desc_limit[9]
  PIN b_desc_loops[0]
    DIRECTION OUTPUT ;
    USE SIGNAL ;
    PORT
      LAYER M4 ;
        RECT  69.036 40.464 69.12 40.488 ;
    END
  END b_desc_loops[0]
  PIN b_desc_loops[10]
    DIRECTION OUTPUT ;
    USE SIGNAL ;
    PORT
      LAYER M4 ;
        RECT  69.036 41.424 69.12 41.448 ;
    END
  END b_desc_loops[10]
  PIN b_desc_loops[11]
    DIRECTION OUTPUT ;
    USE SIGNAL ;
    PORT
      LAYER M4 ;
        RECT  69.036 41.52 69.12 41.544 ;
    END
  END b_desc_loops[11]
  PIN b_desc_loops[12]
    DIRECTION OUTPUT ;
    USE SIGNAL ;
    PORT
      LAYER M4 ;
        RECT  69.036 41.616 69.12 41.64 ;
    END
  END b_desc_loops[12]
  PIN b_desc_loops[13]
    DIRECTION OUTPUT ;
    USE SIGNAL ;
    PORT
      LAYER M4 ;
        RECT  69.036 41.712 69.12 41.736 ;
    END
  END b_desc_loops[13]
  PIN b_desc_loops[14]
    DIRECTION OUTPUT ;
    USE SIGNAL ;
    PORT
      LAYER M4 ;
        RECT  69.036 41.808 69.12 41.832 ;
    END
  END b_desc_loops[14]
  PIN b_desc_loops[15]
    DIRECTION OUTPUT ;
    USE SIGNAL ;
    PORT
      LAYER M4 ;
        RECT  69.036 41.904 69.12 41.928 ;
    END
  END b_desc_loops[15]
  PIN b_desc_loops[1]
    DIRECTION OUTPUT ;
    USE SIGNAL ;
    PORT
      LAYER M4 ;
        RECT  69.036 40.56 69.12 40.584 ;
    END
  END b_desc_loops[1]
  PIN b_desc_loops[2]
    DIRECTION OUTPUT ;
    USE SIGNAL ;
    PORT
      LAYER M4 ;
        RECT  69.036 40.656 69.12 40.68 ;
    END
  END b_desc_loops[2]
  PIN b_desc_loops[3]
    DIRECTION OUTPUT ;
    USE SIGNAL ;
    PORT
      LAYER M4 ;
        RECT  69.036 40.752 69.12 40.776 ;
    END
  END b_desc_loops[3]
  PIN b_desc_loops[4]
    DIRECTION OUTPUT ;
    USE SIGNAL ;
    PORT
      LAYER M4 ;
        RECT  69.036 40.848 69.12 40.872 ;
    END
  END b_desc_loops[4]
  PIN b_desc_loops[5]
    DIRECTION OUTPUT ;
    USE SIGNAL ;
    PORT
      LAYER M4 ;
        RECT  69.036 40.944 69.12 40.968 ;
    END
  END b_desc_loops[5]
  PIN b_desc_loops[6]
    DIRECTION OUTPUT ;
    USE SIGNAL ;
    PORT
      LAYER M4 ;
        RECT  69.036 41.04 69.12 41.064 ;
    END
  END b_desc_loops[6]
  PIN b_desc_loops[7]
    DIRECTION OUTPUT ;
    USE SIGNAL ;
    PORT
      LAYER M4 ;
        RECT  69.036 41.136 69.12 41.16 ;
    END
  END b_desc_loops[7]
  PIN b_desc_loops[8]
    DIRECTION OUTPUT ;
    USE SIGNAL ;
    PORT
      LAYER M4 ;
        RECT  69.036 41.232 69.12 41.256 ;
    END
  END b_desc_loops[8]
  PIN b_desc_loops[9]
    DIRECTION OUTPUT ;
    USE SIGNAL ;
    PORT
      LAYER M4 ;
        RECT  69.036 41.328 69.12 41.352 ;
    END
  END b_desc_loops[9]
  PIN b_desc_v
    DIRECTION OUTPUT ;
    USE SIGNAL ;
    PORT
      LAYER M4 ;
        RECT  69.036 42 69.12 42.024 ;
    END
  END b_desc_v
  PIN b_launch_v
    DIRECTION OUTPUT ;
    USE SIGNAL ;
    PORT
      LAYER M4 ;
        RECT  69.036 42.096 69.12 42.12 ;
    END
  END b_launch_v
  PIN cfg_addr[0]
    DIRECTION INPUT ;
    USE SIGNAL ;
    PORT
      LAYER M5 ;
        RECT  17.712 69.036 17.736 69.12 ;
    END
  END cfg_addr[0]
  PIN cfg_addr[10]
    DIRECTION INPUT ;
    USE SIGNAL ;
    PORT
      LAYER M5 ;
        RECT  18.672 69.036 18.696 69.12 ;
    END
  END cfg_addr[10]
  PIN cfg_addr[11]
    DIRECTION INPUT ;
    USE SIGNAL ;
    PORT
      LAYER M5 ;
        RECT  18.768 69.036 18.792 69.12 ;
    END
  END cfg_addr[11]
  PIN cfg_addr[1]
    DIRECTION INPUT ;
    USE SIGNAL ;
    PORT
      LAYER M5 ;
        RECT  17.808 69.036 17.832 69.12 ;
    END
  END cfg_addr[1]
  PIN cfg_addr[2]
    DIRECTION INPUT ;
    USE SIGNAL ;
    PORT
      LAYER M5 ;
        RECT  17.904 69.036 17.928 69.12 ;
    END
  END cfg_addr[2]
  PIN cfg_addr[3]
    DIRECTION INPUT ;
    USE SIGNAL ;
    PORT
      LAYER M5 ;
        RECT  18 69.036 18.024 69.12 ;
    END
  END cfg_addr[3]
  PIN cfg_addr[4]
    DIRECTION INPUT ;
    USE SIGNAL ;
    PORT
      LAYER M5 ;
        RECT  18.096 69.036 18.12 69.12 ;
    END
  END cfg_addr[4]
  PIN cfg_addr[5]
    DIRECTION INPUT ;
    USE SIGNAL ;
    PORT
      LAYER M5 ;
        RECT  18.192 69.036 18.216 69.12 ;
    END
  END cfg_addr[5]
  PIN cfg_addr[6]
    DIRECTION INPUT ;
    USE SIGNAL ;
    PORT
      LAYER M5 ;
        RECT  18.288 69.036 18.312 69.12 ;
    END
  END cfg_addr[6]
  PIN cfg_addr[7]
    DIRECTION INPUT ;
    USE SIGNAL ;
    PORT
      LAYER M5 ;
        RECT  18.384 69.036 18.408 69.12 ;
    END
  END cfg_addr[7]
  PIN cfg_addr[8]
    DIRECTION INPUT ;
    USE SIGNAL ;
    PORT
      LAYER M5 ;
        RECT  18.48 69.036 18.504 69.12 ;
    END
  END cfg_addr[8]
  PIN cfg_addr[9]
    DIRECTION INPUT ;
    USE SIGNAL ;
    PORT
      LAYER M5 ;
        RECT  18.576 69.036 18.6 69.12 ;
    END
  END cfg_addr[9]
  PIN cfg_data[0]
    DIRECTION INPUT ;
    USE SIGNAL ;
    PORT
      LAYER M5 ;
        RECT  18.864 69.036 18.888 69.12 ;
    END
  END cfg_data[0]
  PIN cfg_data[100]
    DIRECTION INPUT ;
    USE SIGNAL ;
    PORT
      LAYER M5 ;
        RECT  44.592 69.036 44.616 69.12 ;
    END
  END cfg_data[100]
  PIN cfg_data[101]
    DIRECTION INPUT ;
    USE SIGNAL ;
    PORT
      LAYER M5 ;
        RECT  44.688 69.036 44.712 69.12 ;
    END
  END cfg_data[101]
  PIN cfg_data[102]
    DIRECTION INPUT ;
    USE SIGNAL ;
    PORT
      LAYER M5 ;
        RECT  44.784 69.036 44.808 69.12 ;
    END
  END cfg_data[102]
  PIN cfg_data[103]
    DIRECTION INPUT ;
    USE SIGNAL ;
    PORT
      LAYER M5 ;
        RECT  44.88 69.036 44.904 69.12 ;
    END
  END cfg_data[103]
  PIN cfg_data[104]
    DIRECTION INPUT ;
    USE SIGNAL ;
    PORT
      LAYER M5 ;
        RECT  44.976 69.036 45 69.12 ;
    END
  END cfg_data[104]
  PIN cfg_data[105]
    DIRECTION INPUT ;
    USE SIGNAL ;
    PORT
      LAYER M5 ;
        RECT  45.072 69.036 45.096 69.12 ;
    END
  END cfg_data[105]
  PIN cfg_data[106]
    DIRECTION INPUT ;
    USE SIGNAL ;
    PORT
      LAYER M5 ;
        RECT  45.168 69.036 45.192 69.12 ;
    END
  END cfg_data[106]
  PIN cfg_data[107]
    DIRECTION INPUT ;
    USE SIGNAL ;
    PORT
      LAYER M5 ;
        RECT  45.264 69.036 45.288 69.12 ;
    END
  END cfg_data[107]
  PIN cfg_data[108]
    DIRECTION INPUT ;
    USE SIGNAL ;
    PORT
      LAYER M5 ;
        RECT  45.36 69.036 45.384 69.12 ;
    END
  END cfg_data[108]
  PIN cfg_data[109]
    DIRECTION INPUT ;
    USE SIGNAL ;
    PORT
      LAYER M5 ;
        RECT  45.456 69.036 45.48 69.12 ;
    END
  END cfg_data[109]
  PIN cfg_data[10]
    DIRECTION INPUT ;
    USE SIGNAL ;
    PORT
      LAYER M5 ;
        RECT  19.824 69.036 19.848 69.12 ;
    END
  END cfg_data[10]
  PIN cfg_data[110]
    DIRECTION INPUT ;
    USE SIGNAL ;
    PORT
      LAYER M5 ;
        RECT  45.552 69.036 45.576 69.12 ;
    END
  END cfg_data[110]
  PIN cfg_data[111]
    DIRECTION INPUT ;
    USE SIGNAL ;
    PORT
      LAYER M5 ;
        RECT  45.648 69.036 45.672 69.12 ;
    END
  END cfg_data[111]
  PIN cfg_data[112]
    DIRECTION INPUT ;
    USE SIGNAL ;
    PORT
      LAYER M5 ;
        RECT  45.744 69.036 45.768 69.12 ;
    END
  END cfg_data[112]
  PIN cfg_data[113]
    DIRECTION INPUT ;
    USE SIGNAL ;
    PORT
      LAYER M5 ;
        RECT  45.84 69.036 45.864 69.12 ;
    END
  END cfg_data[113]
  PIN cfg_data[114]
    DIRECTION INPUT ;
    USE SIGNAL ;
    PORT
      LAYER M5 ;
        RECT  45.936 69.036 45.96 69.12 ;
    END
  END cfg_data[114]
  PIN cfg_data[115]
    DIRECTION INPUT ;
    USE SIGNAL ;
    PORT
      LAYER M5 ;
        RECT  46.032 69.036 46.056 69.12 ;
    END
  END cfg_data[115]
  PIN cfg_data[116]
    DIRECTION INPUT ;
    USE SIGNAL ;
    PORT
      LAYER M5 ;
        RECT  46.128 69.036 46.152 69.12 ;
    END
  END cfg_data[116]
  PIN cfg_data[117]
    DIRECTION INPUT ;
    USE SIGNAL ;
    PORT
      LAYER M5 ;
        RECT  46.224 69.036 46.248 69.12 ;
    END
  END cfg_data[117]
  PIN cfg_data[118]
    DIRECTION INPUT ;
    USE SIGNAL ;
    PORT
      LAYER M5 ;
        RECT  46.32 69.036 46.344 69.12 ;
    END
  END cfg_data[118]
  PIN cfg_data[119]
    DIRECTION INPUT ;
    USE SIGNAL ;
    PORT
      LAYER M5 ;
        RECT  46.416 69.036 46.44 69.12 ;
    END
  END cfg_data[119]
  PIN cfg_data[11]
    DIRECTION INPUT ;
    USE SIGNAL ;
    PORT
      LAYER M5 ;
        RECT  19.92 69.036 19.944 69.12 ;
    END
  END cfg_data[11]
  PIN cfg_data[120]
    DIRECTION INPUT ;
    USE SIGNAL ;
    PORT
      LAYER M5 ;
        RECT  46.512 69.036 46.536 69.12 ;
    END
  END cfg_data[120]
  PIN cfg_data[121]
    DIRECTION INPUT ;
    USE SIGNAL ;
    PORT
      LAYER M5 ;
        RECT  46.608 69.036 46.632 69.12 ;
    END
  END cfg_data[121]
  PIN cfg_data[122]
    DIRECTION INPUT ;
    USE SIGNAL ;
    PORT
      LAYER M5 ;
        RECT  46.704 69.036 46.728 69.12 ;
    END
  END cfg_data[122]
  PIN cfg_data[123]
    DIRECTION INPUT ;
    USE SIGNAL ;
    PORT
      LAYER M5 ;
        RECT  46.8 69.036 46.824 69.12 ;
    END
  END cfg_data[123]
  PIN cfg_data[124]
    DIRECTION INPUT ;
    USE SIGNAL ;
    PORT
      LAYER M5 ;
        RECT  46.896 69.036 46.92 69.12 ;
    END
  END cfg_data[124]
  PIN cfg_data[125]
    DIRECTION INPUT ;
    USE SIGNAL ;
    PORT
      LAYER M5 ;
        RECT  46.992 69.036 47.016 69.12 ;
    END
  END cfg_data[125]
  PIN cfg_data[126]
    DIRECTION INPUT ;
    USE SIGNAL ;
    PORT
      LAYER M5 ;
        RECT  47.088 69.036 47.112 69.12 ;
    END
  END cfg_data[126]
  PIN cfg_data[127]
    DIRECTION INPUT ;
    USE SIGNAL ;
    PORT
      LAYER M5 ;
        RECT  47.184 69.036 47.208 69.12 ;
    END
  END cfg_data[127]
  PIN cfg_data[128]
    DIRECTION INPUT ;
    USE SIGNAL ;
    PORT
      LAYER M5 ;
        RECT  47.28 69.036 47.304 69.12 ;
    END
  END cfg_data[128]
  PIN cfg_data[129]
    DIRECTION INPUT ;
    USE SIGNAL ;
    PORT
      LAYER M5 ;
        RECT  47.376 69.036 47.4 69.12 ;
    END
  END cfg_data[129]
  PIN cfg_data[12]
    DIRECTION INPUT ;
    USE SIGNAL ;
    PORT
      LAYER M5 ;
        RECT  20.016 69.036 20.04 69.12 ;
    END
  END cfg_data[12]
  PIN cfg_data[130]
    DIRECTION INPUT ;
    USE SIGNAL ;
    PORT
      LAYER M5 ;
        RECT  47.472 69.036 47.496 69.12 ;
    END
  END cfg_data[130]
  PIN cfg_data[131]
    DIRECTION INPUT ;
    USE SIGNAL ;
    PORT
      LAYER M5 ;
        RECT  47.568 69.036 47.592 69.12 ;
    END
  END cfg_data[131]
  PIN cfg_data[132]
    DIRECTION INPUT ;
    USE SIGNAL ;
    PORT
      LAYER M5 ;
        RECT  47.664 69.036 47.688 69.12 ;
    END
  END cfg_data[132]
  PIN cfg_data[133]
    DIRECTION INPUT ;
    USE SIGNAL ;
    PORT
      LAYER M5 ;
        RECT  47.76 69.036 47.784 69.12 ;
    END
  END cfg_data[133]
  PIN cfg_data[134]
    DIRECTION INPUT ;
    USE SIGNAL ;
    PORT
      LAYER M5 ;
        RECT  47.856 69.036 47.88 69.12 ;
    END
  END cfg_data[134]
  PIN cfg_data[135]
    DIRECTION INPUT ;
    USE SIGNAL ;
    PORT
      LAYER M5 ;
        RECT  47.952 69.036 47.976 69.12 ;
    END
  END cfg_data[135]
  PIN cfg_data[136]
    DIRECTION INPUT ;
    USE SIGNAL ;
    PORT
      LAYER M5 ;
        RECT  48.048 69.036 48.072 69.12 ;
    END
  END cfg_data[136]
  PIN cfg_data[137]
    DIRECTION INPUT ;
    USE SIGNAL ;
    PORT
      LAYER M5 ;
        RECT  48.144 69.036 48.168 69.12 ;
    END
  END cfg_data[137]
  PIN cfg_data[138]
    DIRECTION INPUT ;
    USE SIGNAL ;
    PORT
      LAYER M5 ;
        RECT  48.24 69.036 48.264 69.12 ;
    END
  END cfg_data[138]
  PIN cfg_data[139]
    DIRECTION INPUT ;
    USE SIGNAL ;
    PORT
      LAYER M5 ;
        RECT  48.336 69.036 48.36 69.12 ;
    END
  END cfg_data[139]
  PIN cfg_data[13]
    DIRECTION INPUT ;
    USE SIGNAL ;
    PORT
      LAYER M5 ;
        RECT  20.112 69.036 20.136 69.12 ;
    END
  END cfg_data[13]
  PIN cfg_data[140]
    DIRECTION INPUT ;
    USE SIGNAL ;
    PORT
      LAYER M5 ;
        RECT  48.432 69.036 48.456 69.12 ;
    END
  END cfg_data[140]
  PIN cfg_data[141]
    DIRECTION INPUT ;
    USE SIGNAL ;
    PORT
      LAYER M5 ;
        RECT  48.528 69.036 48.552 69.12 ;
    END
  END cfg_data[141]
  PIN cfg_data[142]
    DIRECTION INPUT ;
    USE SIGNAL ;
    PORT
      LAYER M5 ;
        RECT  48.624 69.036 48.648 69.12 ;
    END
  END cfg_data[142]
  PIN cfg_data[143]
    DIRECTION INPUT ;
    USE SIGNAL ;
    PORT
      LAYER M5 ;
        RECT  48.72 69.036 48.744 69.12 ;
    END
  END cfg_data[143]
  PIN cfg_data[144]
    DIRECTION INPUT ;
    USE SIGNAL ;
    PORT
      LAYER M5 ;
        RECT  48.816 69.036 48.84 69.12 ;
    END
  END cfg_data[144]
  PIN cfg_data[145]
    DIRECTION INPUT ;
    USE SIGNAL ;
    PORT
      LAYER M5 ;
        RECT  48.912 69.036 48.936 69.12 ;
    END
  END cfg_data[145]
  PIN cfg_data[146]
    DIRECTION INPUT ;
    USE SIGNAL ;
    PORT
      LAYER M5 ;
        RECT  49.008 69.036 49.032 69.12 ;
    END
  END cfg_data[146]
  PIN cfg_data[147]
    DIRECTION INPUT ;
    USE SIGNAL ;
    PORT
      LAYER M5 ;
        RECT  49.104 69.036 49.128 69.12 ;
    END
  END cfg_data[147]
  PIN cfg_data[148]
    DIRECTION INPUT ;
    USE SIGNAL ;
    PORT
      LAYER M5 ;
        RECT  36.912 69.036 36.936 69.12 ;
    END
  END cfg_data[148]
  PIN cfg_data[149]
    DIRECTION INPUT ;
    USE SIGNAL ;
    PORT
      LAYER M5 ;
        RECT  37.008 69.036 37.032 69.12 ;
    END
  END cfg_data[149]
  PIN cfg_data[14]
    DIRECTION INPUT ;
    USE SIGNAL ;
    PORT
      LAYER M5 ;
        RECT  20.208 69.036 20.232 69.12 ;
    END
  END cfg_data[14]
  PIN cfg_data[150]
    DIRECTION INPUT ;
    USE SIGNAL ;
    PORT
      LAYER M5 ;
        RECT  37.104 69.036 37.128 69.12 ;
    END
  END cfg_data[150]
  PIN cfg_data[151]
    DIRECTION INPUT ;
    USE SIGNAL ;
    PORT
      LAYER M5 ;
        RECT  37.2 69.036 37.224 69.12 ;
    END
  END cfg_data[151]
  PIN cfg_data[152]
    DIRECTION INPUT ;
    USE SIGNAL ;
    PORT
      LAYER M5 ;
        RECT  37.296 69.036 37.32 69.12 ;
    END
  END cfg_data[152]
  PIN cfg_data[153]
    DIRECTION INPUT ;
    USE SIGNAL ;
    PORT
      LAYER M5 ;
        RECT  37.392 69.036 37.416 69.12 ;
    END
  END cfg_data[153]
  PIN cfg_data[154]
    DIRECTION INPUT ;
    USE SIGNAL ;
    PORT
      LAYER M5 ;
        RECT  37.488 69.036 37.512 69.12 ;
    END
  END cfg_data[154]
  PIN cfg_data[155]
    DIRECTION INPUT ;
    USE SIGNAL ;
    PORT
      LAYER M5 ;
        RECT  37.584 69.036 37.608 69.12 ;
    END
  END cfg_data[155]
  PIN cfg_data[156]
    DIRECTION INPUT ;
    USE SIGNAL ;
    PORT
      LAYER M5 ;
        RECT  37.68 69.036 37.704 69.12 ;
    END
  END cfg_data[156]
  PIN cfg_data[157]
    DIRECTION INPUT ;
    USE SIGNAL ;
    PORT
      LAYER M5 ;
        RECT  37.776 69.036 37.8 69.12 ;
    END
  END cfg_data[157]
  PIN cfg_data[158]
    DIRECTION INPUT ;
    USE SIGNAL ;
    PORT
      LAYER M5 ;
        RECT  37.872 69.036 37.896 69.12 ;
    END
  END cfg_data[158]
  PIN cfg_data[159]
    DIRECTION INPUT ;
    USE SIGNAL ;
    PORT
      LAYER M5 ;
        RECT  37.968 69.036 37.992 69.12 ;
    END
  END cfg_data[159]
  PIN cfg_data[15]
    DIRECTION INPUT ;
    USE SIGNAL ;
    PORT
      LAYER M5 ;
        RECT  20.304 69.036 20.328 69.12 ;
    END
  END cfg_data[15]
  PIN cfg_data[160]
    DIRECTION INPUT ;
    USE SIGNAL ;
    PORT
      LAYER M5 ;
        RECT  38.064 69.036 38.088 69.12 ;
    END
  END cfg_data[160]
  PIN cfg_data[161]
    DIRECTION INPUT ;
    USE SIGNAL ;
    PORT
      LAYER M5 ;
        RECT  38.16 69.036 38.184 69.12 ;
    END
  END cfg_data[161]
  PIN cfg_data[162]
    DIRECTION INPUT ;
    USE SIGNAL ;
    PORT
      LAYER M5 ;
        RECT  38.256 69.036 38.28 69.12 ;
    END
  END cfg_data[162]
  PIN cfg_data[163]
    DIRECTION INPUT ;
    USE SIGNAL ;
    PORT
      LAYER M5 ;
        RECT  38.352 69.036 38.376 69.12 ;
    END
  END cfg_data[163]
  PIN cfg_data[164]
    DIRECTION INPUT ;
    USE SIGNAL ;
    PORT
      LAYER M5 ;
        RECT  38.448 69.036 38.472 69.12 ;
    END
  END cfg_data[164]
  PIN cfg_data[165]
    DIRECTION INPUT ;
    USE SIGNAL ;
    PORT
      LAYER M5 ;
        RECT  38.544 69.036 38.568 69.12 ;
    END
  END cfg_data[165]
  PIN cfg_data[166]
    DIRECTION INPUT ;
    USE SIGNAL ;
    PORT
      LAYER M5 ;
        RECT  38.64 69.036 38.664 69.12 ;
    END
  END cfg_data[166]
  PIN cfg_data[167]
    DIRECTION INPUT ;
    USE SIGNAL ;
    PORT
      LAYER M5 ;
        RECT  38.736 69.036 38.76 69.12 ;
    END
  END cfg_data[167]
  PIN cfg_data[168]
    DIRECTION INPUT ;
    USE SIGNAL ;
    PORT
      LAYER M5 ;
        RECT  38.832 69.036 38.856 69.12 ;
    END
  END cfg_data[168]
  PIN cfg_data[169]
    DIRECTION INPUT ;
    USE SIGNAL ;
    PORT
      LAYER M5 ;
        RECT  38.928 69.036 38.952 69.12 ;
    END
  END cfg_data[169]
  PIN cfg_data[16]
    DIRECTION INPUT ;
    USE SIGNAL ;
    PORT
      LAYER M5 ;
        RECT  20.4 69.036 20.424 69.12 ;
    END
  END cfg_data[16]
  PIN cfg_data[170]
    DIRECTION INPUT ;
    USE SIGNAL ;
    PORT
      LAYER M5 ;
        RECT  39.024 69.036 39.048 69.12 ;
    END
  END cfg_data[170]
  PIN cfg_data[171]
    DIRECTION INPUT ;
    USE SIGNAL ;
    PORT
      LAYER M5 ;
        RECT  39.12 69.036 39.144 69.12 ;
    END
  END cfg_data[171]
  PIN cfg_data[172]
    DIRECTION INPUT ;
    USE SIGNAL ;
    PORT
      LAYER M5 ;
        RECT  39.216 69.036 39.24 69.12 ;
    END
  END cfg_data[172]
  PIN cfg_data[173]
    DIRECTION INPUT ;
    USE SIGNAL ;
    PORT
      LAYER M5 ;
        RECT  39.312 69.036 39.336 69.12 ;
    END
  END cfg_data[173]
  PIN cfg_data[174]
    DIRECTION INPUT ;
    USE SIGNAL ;
    PORT
      LAYER M5 ;
        RECT  39.408 69.036 39.432 69.12 ;
    END
  END cfg_data[174]
  PIN cfg_data[175]
    DIRECTION INPUT ;
    USE SIGNAL ;
    PORT
      LAYER M5 ;
        RECT  39.504 69.036 39.528 69.12 ;
    END
  END cfg_data[175]
  PIN cfg_data[176]
    DIRECTION INPUT ;
    USE SIGNAL ;
    PORT
      LAYER M5 ;
        RECT  39.6 69.036 39.624 69.12 ;
    END
  END cfg_data[176]
  PIN cfg_data[177]
    DIRECTION INPUT ;
    USE SIGNAL ;
    PORT
      LAYER M5 ;
        RECT  39.696 69.036 39.72 69.12 ;
    END
  END cfg_data[177]
  PIN cfg_data[178]
    DIRECTION INPUT ;
    USE SIGNAL ;
    PORT
      LAYER M5 ;
        RECT  39.792 69.036 39.816 69.12 ;
    END
  END cfg_data[178]
  PIN cfg_data[179]
    DIRECTION INPUT ;
    USE SIGNAL ;
    PORT
      LAYER M5 ;
        RECT  39.888 69.036 39.912 69.12 ;
    END
  END cfg_data[179]
  PIN cfg_data[17]
    DIRECTION INPUT ;
    USE SIGNAL ;
    PORT
      LAYER M5 ;
        RECT  20.496 69.036 20.52 69.12 ;
    END
  END cfg_data[17]
  PIN cfg_data[180]
    DIRECTION INPUT ;
    USE SIGNAL ;
    PORT
      LAYER M5 ;
        RECT  39.984 69.036 40.008 69.12 ;
    END
  END cfg_data[180]
  PIN cfg_data[181]
    DIRECTION INPUT ;
    USE SIGNAL ;
    PORT
      LAYER M5 ;
        RECT  40.08 69.036 40.104 69.12 ;
    END
  END cfg_data[181]
  PIN cfg_data[182]
    DIRECTION INPUT ;
    USE SIGNAL ;
    PORT
      LAYER M5 ;
        RECT  40.176 69.036 40.2 69.12 ;
    END
  END cfg_data[182]
  PIN cfg_data[183]
    DIRECTION INPUT ;
    USE SIGNAL ;
    PORT
      LAYER M5 ;
        RECT  40.272 69.036 40.296 69.12 ;
    END
  END cfg_data[183]
  PIN cfg_data[184]
    DIRECTION INPUT ;
    USE SIGNAL ;
    PORT
      LAYER M5 ;
        RECT  40.368 69.036 40.392 69.12 ;
    END
  END cfg_data[184]
  PIN cfg_data[185]
    DIRECTION INPUT ;
    USE SIGNAL ;
    PORT
      LAYER M5 ;
        RECT  40.464 69.036 40.488 69.12 ;
    END
  END cfg_data[185]
  PIN cfg_data[186]
    DIRECTION INPUT ;
    USE SIGNAL ;
    PORT
      LAYER M5 ;
        RECT  40.56 69.036 40.584 69.12 ;
    END
  END cfg_data[186]
  PIN cfg_data[187]
    DIRECTION INPUT ;
    USE SIGNAL ;
    PORT
      LAYER M5 ;
        RECT  40.656 69.036 40.68 69.12 ;
    END
  END cfg_data[187]
  PIN cfg_data[188]
    DIRECTION INPUT ;
    USE SIGNAL ;
    PORT
      LAYER M5 ;
        RECT  40.752 69.036 40.776 69.12 ;
    END
  END cfg_data[188]
  PIN cfg_data[189]
    DIRECTION INPUT ;
    USE SIGNAL ;
    PORT
      LAYER M5 ;
        RECT  40.848 69.036 40.872 69.12 ;
    END
  END cfg_data[189]
  PIN cfg_data[18]
    DIRECTION INPUT ;
    USE SIGNAL ;
    PORT
      LAYER M5 ;
        RECT  20.592 69.036 20.616 69.12 ;
    END
  END cfg_data[18]
  PIN cfg_data[190]
    DIRECTION INPUT ;
    USE SIGNAL ;
    PORT
      LAYER M5 ;
        RECT  40.944 69.036 40.968 69.12 ;
    END
  END cfg_data[190]
  PIN cfg_data[191]
    DIRECTION INPUT ;
    USE SIGNAL ;
    PORT
      LAYER M5 ;
        RECT  41.04 69.036 41.064 69.12 ;
    END
  END cfg_data[191]
  PIN cfg_data[192]
    DIRECTION INPUT ;
    USE SIGNAL ;
    PORT
      LAYER M5 ;
        RECT  41.136 69.036 41.16 69.12 ;
    END
  END cfg_data[192]
  PIN cfg_data[193]
    DIRECTION INPUT ;
    USE SIGNAL ;
    PORT
      LAYER M5 ;
        RECT  41.232 69.036 41.256 69.12 ;
    END
  END cfg_data[193]
  PIN cfg_data[194]
    DIRECTION INPUT ;
    USE SIGNAL ;
    PORT
      LAYER M5 ;
        RECT  41.328 69.036 41.352 69.12 ;
    END
  END cfg_data[194]
  PIN cfg_data[195]
    DIRECTION INPUT ;
    USE SIGNAL ;
    PORT
      LAYER M5 ;
        RECT  41.424 69.036 41.448 69.12 ;
    END
  END cfg_data[195]
  PIN cfg_data[196]
    DIRECTION INPUT ;
    USE SIGNAL ;
    PORT
      LAYER M5 ;
        RECT  41.52 69.036 41.544 69.12 ;
    END
  END cfg_data[196]
  PIN cfg_data[197]
    DIRECTION INPUT ;
    USE SIGNAL ;
    PORT
      LAYER M5 ;
        RECT  41.616 69.036 41.64 69.12 ;
    END
  END cfg_data[197]
  PIN cfg_data[198]
    DIRECTION INPUT ;
    USE SIGNAL ;
    PORT
      LAYER M5 ;
        RECT  41.712 69.036 41.736 69.12 ;
    END
  END cfg_data[198]
  PIN cfg_data[199]
    DIRECTION INPUT ;
    USE SIGNAL ;
    PORT
      LAYER M5 ;
        RECT  41.808 69.036 41.832 69.12 ;
    END
  END cfg_data[199]
  PIN cfg_data[19]
    DIRECTION INPUT ;
    USE SIGNAL ;
    PORT
      LAYER M5 ;
        RECT  20.688 69.036 20.712 69.12 ;
    END
  END cfg_data[19]
  PIN cfg_data[1]
    DIRECTION INPUT ;
    USE SIGNAL ;
    PORT
      LAYER M5 ;
        RECT  18.96 69.036 18.984 69.12 ;
    END
  END cfg_data[1]
  PIN cfg_data[200]
    DIRECTION INPUT ;
    USE SIGNAL ;
    PORT
      LAYER M5 ;
        RECT  41.904 69.036 41.928 69.12 ;
    END
  END cfg_data[200]
  PIN cfg_data[201]
    DIRECTION INPUT ;
    USE SIGNAL ;
    PORT
      LAYER M5 ;
        RECT  42 69.036 42.024 69.12 ;
    END
  END cfg_data[201]
  PIN cfg_data[202]
    DIRECTION INPUT ;
    USE SIGNAL ;
    PORT
      LAYER M5 ;
        RECT  42.096 69.036 42.12 69.12 ;
    END
  END cfg_data[202]
  PIN cfg_data[203]
    DIRECTION INPUT ;
    USE SIGNAL ;
    PORT
      LAYER M5 ;
        RECT  42.192 69.036 42.216 69.12 ;
    END
  END cfg_data[203]
  PIN cfg_data[204]
    DIRECTION INPUT ;
    USE SIGNAL ;
    PORT
      LAYER M5 ;
        RECT  42.288 69.036 42.312 69.12 ;
    END
  END cfg_data[204]
  PIN cfg_data[205]
    DIRECTION INPUT ;
    USE SIGNAL ;
    PORT
      LAYER M5 ;
        RECT  42.384 69.036 42.408 69.12 ;
    END
  END cfg_data[205]
  PIN cfg_data[206]
    DIRECTION INPUT ;
    USE SIGNAL ;
    PORT
      LAYER M5 ;
        RECT  42.48 69.036 42.504 69.12 ;
    END
  END cfg_data[206]
  PIN cfg_data[207]
    DIRECTION INPUT ;
    USE SIGNAL ;
    PORT
      LAYER M5 ;
        RECT  42.576 69.036 42.6 69.12 ;
    END
  END cfg_data[207]
  PIN cfg_data[208]
    DIRECTION INPUT ;
    USE SIGNAL ;
    PORT
      LAYER M5 ;
        RECT  42.672 69.036 42.696 69.12 ;
    END
  END cfg_data[208]
  PIN cfg_data[209]
    DIRECTION INPUT ;
    USE SIGNAL ;
    PORT
      LAYER M5 ;
        RECT  42.768 69.036 42.792 69.12 ;
    END
  END cfg_data[209]
  PIN cfg_data[20]
    DIRECTION INPUT ;
    USE SIGNAL ;
    PORT
      LAYER M5 ;
        RECT  30.768 69.036 30.792 69.12 ;
    END
  END cfg_data[20]
  PIN cfg_data[210]
    DIRECTION INPUT ;
    USE SIGNAL ;
    PORT
      LAYER M5 ;
        RECT  42.864 69.036 42.888 69.12 ;
    END
  END cfg_data[210]
  PIN cfg_data[211]
    DIRECTION INPUT ;
    USE SIGNAL ;
    PORT
      LAYER M5 ;
        RECT  42.96 69.036 42.984 69.12 ;
    END
  END cfg_data[211]
  PIN cfg_data[212]
    DIRECTION INPUT ;
    USE SIGNAL ;
    PORT
      LAYER M5 ;
        RECT  23.856 69.036 23.88 69.12 ;
    END
  END cfg_data[212]
  PIN cfg_data[213]
    DIRECTION INPUT ;
    USE SIGNAL ;
    PORT
      LAYER M5 ;
        RECT  23.952 69.036 23.976 69.12 ;
    END
  END cfg_data[213]
  PIN cfg_data[214]
    DIRECTION INPUT ;
    USE SIGNAL ;
    PORT
      LAYER M5 ;
        RECT  24.048 69.036 24.072 69.12 ;
    END
  END cfg_data[214]
  PIN cfg_data[215]
    DIRECTION INPUT ;
    USE SIGNAL ;
    PORT
      LAYER M5 ;
        RECT  24.144 69.036 24.168 69.12 ;
    END
  END cfg_data[215]
  PIN cfg_data[216]
    DIRECTION INPUT ;
    USE SIGNAL ;
    PORT
      LAYER M5 ;
        RECT  24.24 69.036 24.264 69.12 ;
    END
  END cfg_data[216]
  PIN cfg_data[217]
    DIRECTION INPUT ;
    USE SIGNAL ;
    PORT
      LAYER M5 ;
        RECT  24.336 69.036 24.36 69.12 ;
    END
  END cfg_data[217]
  PIN cfg_data[218]
    DIRECTION INPUT ;
    USE SIGNAL ;
    PORT
      LAYER M5 ;
        RECT  24.432 69.036 24.456 69.12 ;
    END
  END cfg_data[218]
  PIN cfg_data[219]
    DIRECTION INPUT ;
    USE SIGNAL ;
    PORT
      LAYER M5 ;
        RECT  24.528 69.036 24.552 69.12 ;
    END
  END cfg_data[219]
  PIN cfg_data[21]
    DIRECTION INPUT ;
    USE SIGNAL ;
    PORT
      LAYER M5 ;
        RECT  30.864 69.036 30.888 69.12 ;
    END
  END cfg_data[21]
  PIN cfg_data[220]
    DIRECTION INPUT ;
    USE SIGNAL ;
    PORT
      LAYER M5 ;
        RECT  24.624 69.036 24.648 69.12 ;
    END
  END cfg_data[220]
  PIN cfg_data[221]
    DIRECTION INPUT ;
    USE SIGNAL ;
    PORT
      LAYER M5 ;
        RECT  24.72 69.036 24.744 69.12 ;
    END
  END cfg_data[221]
  PIN cfg_data[222]
    DIRECTION INPUT ;
    USE SIGNAL ;
    PORT
      LAYER M5 ;
        RECT  24.816 69.036 24.84 69.12 ;
    END
  END cfg_data[222]
  PIN cfg_data[223]
    DIRECTION INPUT ;
    USE SIGNAL ;
    PORT
      LAYER M5 ;
        RECT  24.912 69.036 24.936 69.12 ;
    END
  END cfg_data[223]
  PIN cfg_data[224]
    DIRECTION INPUT ;
    USE SIGNAL ;
    PORT
      LAYER M5 ;
        RECT  25.008 69.036 25.032 69.12 ;
    END
  END cfg_data[224]
  PIN cfg_data[225]
    DIRECTION INPUT ;
    USE SIGNAL ;
    PORT
      LAYER M5 ;
        RECT  25.104 69.036 25.128 69.12 ;
    END
  END cfg_data[225]
  PIN cfg_data[226]
    DIRECTION INPUT ;
    USE SIGNAL ;
    PORT
      LAYER M5 ;
        RECT  25.2 69.036 25.224 69.12 ;
    END
  END cfg_data[226]
  PIN cfg_data[227]
    DIRECTION INPUT ;
    USE SIGNAL ;
    PORT
      LAYER M5 ;
        RECT  25.296 69.036 25.32 69.12 ;
    END
  END cfg_data[227]
  PIN cfg_data[228]
    DIRECTION INPUT ;
    USE SIGNAL ;
    PORT
      LAYER M5 ;
        RECT  25.392 69.036 25.416 69.12 ;
    END
  END cfg_data[228]
  PIN cfg_data[229]
    DIRECTION INPUT ;
    USE SIGNAL ;
    PORT
      LAYER M5 ;
        RECT  25.488 69.036 25.512 69.12 ;
    END
  END cfg_data[229]
  PIN cfg_data[22]
    DIRECTION INPUT ;
    USE SIGNAL ;
    PORT
      LAYER M5 ;
        RECT  30.96 69.036 30.984 69.12 ;
    END
  END cfg_data[22]
  PIN cfg_data[230]
    DIRECTION INPUT ;
    USE SIGNAL ;
    PORT
      LAYER M5 ;
        RECT  25.584 69.036 25.608 69.12 ;
    END
  END cfg_data[230]
  PIN cfg_data[231]
    DIRECTION INPUT ;
    USE SIGNAL ;
    PORT
      LAYER M5 ;
        RECT  25.68 69.036 25.704 69.12 ;
    END
  END cfg_data[231]
  PIN cfg_data[232]
    DIRECTION INPUT ;
    USE SIGNAL ;
    PORT
      LAYER M5 ;
        RECT  25.776 69.036 25.8 69.12 ;
    END
  END cfg_data[232]
  PIN cfg_data[233]
    DIRECTION INPUT ;
    USE SIGNAL ;
    PORT
      LAYER M5 ;
        RECT  25.872 69.036 25.896 69.12 ;
    END
  END cfg_data[233]
  PIN cfg_data[234]
    DIRECTION INPUT ;
    USE SIGNAL ;
    PORT
      LAYER M5 ;
        RECT  25.968 69.036 25.992 69.12 ;
    END
  END cfg_data[234]
  PIN cfg_data[235]
    DIRECTION INPUT ;
    USE SIGNAL ;
    PORT
      LAYER M5 ;
        RECT  26.064 69.036 26.088 69.12 ;
    END
  END cfg_data[235]
  PIN cfg_data[236]
    DIRECTION INPUT ;
    USE SIGNAL ;
    PORT
      LAYER M5 ;
        RECT  26.16 69.036 26.184 69.12 ;
    END
  END cfg_data[236]
  PIN cfg_data[237]
    DIRECTION INPUT ;
    USE SIGNAL ;
    PORT
      LAYER M5 ;
        RECT  26.256 69.036 26.28 69.12 ;
    END
  END cfg_data[237]
  PIN cfg_data[238]
    DIRECTION INPUT ;
    USE SIGNAL ;
    PORT
      LAYER M5 ;
        RECT  26.352 69.036 26.376 69.12 ;
    END
  END cfg_data[238]
  PIN cfg_data[239]
    DIRECTION INPUT ;
    USE SIGNAL ;
    PORT
      LAYER M5 ;
        RECT  26.448 69.036 26.472 69.12 ;
    END
  END cfg_data[239]
  PIN cfg_data[23]
    DIRECTION INPUT ;
    USE SIGNAL ;
    PORT
      LAYER M5 ;
        RECT  31.056 69.036 31.08 69.12 ;
    END
  END cfg_data[23]
  PIN cfg_data[240]
    DIRECTION INPUT ;
    USE SIGNAL ;
    PORT
      LAYER M5 ;
        RECT  26.544 69.036 26.568 69.12 ;
    END
  END cfg_data[240]
  PIN cfg_data[241]
    DIRECTION INPUT ;
    USE SIGNAL ;
    PORT
      LAYER M5 ;
        RECT  26.64 69.036 26.664 69.12 ;
    END
  END cfg_data[241]
  PIN cfg_data[242]
    DIRECTION INPUT ;
    USE SIGNAL ;
    PORT
      LAYER M5 ;
        RECT  26.736 69.036 26.76 69.12 ;
    END
  END cfg_data[242]
  PIN cfg_data[243]
    DIRECTION INPUT ;
    USE SIGNAL ;
    PORT
      LAYER M5 ;
        RECT  26.832 69.036 26.856 69.12 ;
    END
  END cfg_data[243]
  PIN cfg_data[244]
    DIRECTION INPUT ;
    USE SIGNAL ;
    PORT
      LAYER M5 ;
        RECT  26.928 69.036 26.952 69.12 ;
    END
  END cfg_data[244]
  PIN cfg_data[245]
    DIRECTION INPUT ;
    USE SIGNAL ;
    PORT
      LAYER M5 ;
        RECT  27.024 69.036 27.048 69.12 ;
    END
  END cfg_data[245]
  PIN cfg_data[246]
    DIRECTION INPUT ;
    USE SIGNAL ;
    PORT
      LAYER M5 ;
        RECT  27.12 69.036 27.144 69.12 ;
    END
  END cfg_data[246]
  PIN cfg_data[247]
    DIRECTION INPUT ;
    USE SIGNAL ;
    PORT
      LAYER M5 ;
        RECT  27.216 69.036 27.24 69.12 ;
    END
  END cfg_data[247]
  PIN cfg_data[248]
    DIRECTION INPUT ;
    USE SIGNAL ;
    PORT
      LAYER M5 ;
        RECT  27.312 69.036 27.336 69.12 ;
    END
  END cfg_data[248]
  PIN cfg_data[249]
    DIRECTION INPUT ;
    USE SIGNAL ;
    PORT
      LAYER M5 ;
        RECT  27.408 69.036 27.432 69.12 ;
    END
  END cfg_data[249]
  PIN cfg_data[24]
    DIRECTION INPUT ;
    USE SIGNAL ;
    PORT
      LAYER M5 ;
        RECT  31.152 69.036 31.176 69.12 ;
    END
  END cfg_data[24]
  PIN cfg_data[250]
    DIRECTION INPUT ;
    USE SIGNAL ;
    PORT
      LAYER M5 ;
        RECT  27.504 69.036 27.528 69.12 ;
    END
  END cfg_data[250]
  PIN cfg_data[251]
    DIRECTION INPUT ;
    USE SIGNAL ;
    PORT
      LAYER M5 ;
        RECT  27.6 69.036 27.624 69.12 ;
    END
  END cfg_data[251]
  PIN cfg_data[252]
    DIRECTION INPUT ;
    USE SIGNAL ;
    PORT
      LAYER M5 ;
        RECT  27.696 69.036 27.72 69.12 ;
    END
  END cfg_data[252]
  PIN cfg_data[253]
    DIRECTION INPUT ;
    USE SIGNAL ;
    PORT
      LAYER M5 ;
        RECT  27.792 69.036 27.816 69.12 ;
    END
  END cfg_data[253]
  PIN cfg_data[254]
    DIRECTION INPUT ;
    USE SIGNAL ;
    PORT
      LAYER M5 ;
        RECT  27.888 69.036 27.912 69.12 ;
    END
  END cfg_data[254]
  PIN cfg_data[255]
    DIRECTION INPUT ;
    USE SIGNAL ;
    PORT
      LAYER M5 ;
        RECT  27.984 69.036 28.008 69.12 ;
    END
  END cfg_data[255]
  PIN cfg_data[25]
    DIRECTION INPUT ;
    USE SIGNAL ;
    PORT
      LAYER M5 ;
        RECT  31.248 69.036 31.272 69.12 ;
    END
  END cfg_data[25]
  PIN cfg_data[26]
    DIRECTION INPUT ;
    USE SIGNAL ;
    PORT
      LAYER M5 ;
        RECT  31.344 69.036 31.368 69.12 ;
    END
  END cfg_data[26]
  PIN cfg_data[27]
    DIRECTION INPUT ;
    USE SIGNAL ;
    PORT
      LAYER M5 ;
        RECT  31.44 69.036 31.464 69.12 ;
    END
  END cfg_data[27]
  PIN cfg_data[28]
    DIRECTION INPUT ;
    USE SIGNAL ;
    PORT
      LAYER M5 ;
        RECT  31.536 69.036 31.56 69.12 ;
    END
  END cfg_data[28]
  PIN cfg_data[29]
    DIRECTION INPUT ;
    USE SIGNAL ;
    PORT
      LAYER M5 ;
        RECT  31.632 69.036 31.656 69.12 ;
    END
  END cfg_data[29]
  PIN cfg_data[2]
    DIRECTION INPUT ;
    USE SIGNAL ;
    PORT
      LAYER M5 ;
        RECT  19.056 69.036 19.08 69.12 ;
    END
  END cfg_data[2]
  PIN cfg_data[30]
    DIRECTION INPUT ;
    USE SIGNAL ;
    PORT
      LAYER M5 ;
        RECT  31.728 69.036 31.752 69.12 ;
    END
  END cfg_data[30]
  PIN cfg_data[31]
    DIRECTION INPUT ;
    USE SIGNAL ;
    PORT
      LAYER M5 ;
        RECT  31.824 69.036 31.848 69.12 ;
    END
  END cfg_data[31]
  PIN cfg_data[32]
    DIRECTION INPUT ;
    USE SIGNAL ;
    PORT
      LAYER M5 ;
        RECT  31.92 69.036 31.944 69.12 ;
    END
  END cfg_data[32]
  PIN cfg_data[33]
    DIRECTION INPUT ;
    USE SIGNAL ;
    PORT
      LAYER M5 ;
        RECT  32.016 69.036 32.04 69.12 ;
    END
  END cfg_data[33]
  PIN cfg_data[34]
    DIRECTION INPUT ;
    USE SIGNAL ;
    PORT
      LAYER M5 ;
        RECT  32.112 69.036 32.136 69.12 ;
    END
  END cfg_data[34]
  PIN cfg_data[35]
    DIRECTION INPUT ;
    USE SIGNAL ;
    PORT
      LAYER M5 ;
        RECT  32.208 69.036 32.232 69.12 ;
    END
  END cfg_data[35]
  PIN cfg_data[36]
    DIRECTION INPUT ;
    USE SIGNAL ;
    PORT
      LAYER M5 ;
        RECT  32.304 69.036 32.328 69.12 ;
    END
  END cfg_data[36]
  PIN cfg_data[37]
    DIRECTION INPUT ;
    USE SIGNAL ;
    PORT
      LAYER M5 ;
        RECT  32.4 69.036 32.424 69.12 ;
    END
  END cfg_data[37]
  PIN cfg_data[38]
    DIRECTION INPUT ;
    USE SIGNAL ;
    PORT
      LAYER M5 ;
        RECT  32.496 69.036 32.52 69.12 ;
    END
  END cfg_data[38]
  PIN cfg_data[39]
    DIRECTION INPUT ;
    USE SIGNAL ;
    PORT
      LAYER M5 ;
        RECT  32.592 69.036 32.616 69.12 ;
    END
  END cfg_data[39]
  PIN cfg_data[3]
    DIRECTION INPUT ;
    USE SIGNAL ;
    PORT
      LAYER M5 ;
        RECT  19.152 69.036 19.176 69.12 ;
    END
  END cfg_data[3]
  PIN cfg_data[40]
    DIRECTION INPUT ;
    USE SIGNAL ;
    PORT
      LAYER M5 ;
        RECT  32.688 69.036 32.712 69.12 ;
    END
  END cfg_data[40]
  PIN cfg_data[41]
    DIRECTION INPUT ;
    USE SIGNAL ;
    PORT
      LAYER M5 ;
        RECT  32.784 69.036 32.808 69.12 ;
    END
  END cfg_data[41]
  PIN cfg_data[42]
    DIRECTION INPUT ;
    USE SIGNAL ;
    PORT
      LAYER M5 ;
        RECT  32.88 69.036 32.904 69.12 ;
    END
  END cfg_data[42]
  PIN cfg_data[43]
    DIRECTION INPUT ;
    USE SIGNAL ;
    PORT
      LAYER M5 ;
        RECT  32.976 69.036 33 69.12 ;
    END
  END cfg_data[43]
  PIN cfg_data[44]
    DIRECTION INPUT ;
    USE SIGNAL ;
    PORT
      LAYER M5 ;
        RECT  33.072 69.036 33.096 69.12 ;
    END
  END cfg_data[44]
  PIN cfg_data[45]
    DIRECTION INPUT ;
    USE SIGNAL ;
    PORT
      LAYER M5 ;
        RECT  33.168 69.036 33.192 69.12 ;
    END
  END cfg_data[45]
  PIN cfg_data[46]
    DIRECTION INPUT ;
    USE SIGNAL ;
    PORT
      LAYER M5 ;
        RECT  33.264 69.036 33.288 69.12 ;
    END
  END cfg_data[46]
  PIN cfg_data[47]
    DIRECTION INPUT ;
    USE SIGNAL ;
    PORT
      LAYER M5 ;
        RECT  33.36 69.036 33.384 69.12 ;
    END
  END cfg_data[47]
  PIN cfg_data[48]
    DIRECTION INPUT ;
    USE SIGNAL ;
    PORT
      LAYER M5 ;
        RECT  33.456 69.036 33.48 69.12 ;
    END
  END cfg_data[48]
  PIN cfg_data[49]
    DIRECTION INPUT ;
    USE SIGNAL ;
    PORT
      LAYER M5 ;
        RECT  33.552 69.036 33.576 69.12 ;
    END
  END cfg_data[49]
  PIN cfg_data[4]
    DIRECTION INPUT ;
    USE SIGNAL ;
    PORT
      LAYER M5 ;
        RECT  19.248 69.036 19.272 69.12 ;
    END
  END cfg_data[4]
  PIN cfg_data[50]
    DIRECTION INPUT ;
    USE SIGNAL ;
    PORT
      LAYER M5 ;
        RECT  33.648 69.036 33.672 69.12 ;
    END
  END cfg_data[50]
  PIN cfg_data[51]
    DIRECTION INPUT ;
    USE SIGNAL ;
    PORT
      LAYER M5 ;
        RECT  33.744 69.036 33.768 69.12 ;
    END
  END cfg_data[51]
  PIN cfg_data[52]
    DIRECTION INPUT ;
    USE SIGNAL ;
    PORT
      LAYER M5 ;
        RECT  33.84 69.036 33.864 69.12 ;
    END
  END cfg_data[52]
  PIN cfg_data[53]
    DIRECTION INPUT ;
    USE SIGNAL ;
    PORT
      LAYER M5 ;
        RECT  33.936 69.036 33.96 69.12 ;
    END
  END cfg_data[53]
  PIN cfg_data[54]
    DIRECTION INPUT ;
    USE SIGNAL ;
    PORT
      LAYER M5 ;
        RECT  34.032 69.036 34.056 69.12 ;
    END
  END cfg_data[54]
  PIN cfg_data[55]
    DIRECTION INPUT ;
    USE SIGNAL ;
    PORT
      LAYER M5 ;
        RECT  34.128 69.036 34.152 69.12 ;
    END
  END cfg_data[55]
  PIN cfg_data[56]
    DIRECTION INPUT ;
    USE SIGNAL ;
    PORT
      LAYER M5 ;
        RECT  34.224 69.036 34.248 69.12 ;
    END
  END cfg_data[56]
  PIN cfg_data[57]
    DIRECTION INPUT ;
    USE SIGNAL ;
    PORT
      LAYER M5 ;
        RECT  34.32 69.036 34.344 69.12 ;
    END
  END cfg_data[57]
  PIN cfg_data[58]
    DIRECTION INPUT ;
    USE SIGNAL ;
    PORT
      LAYER M5 ;
        RECT  34.416 69.036 34.44 69.12 ;
    END
  END cfg_data[58]
  PIN cfg_data[59]
    DIRECTION INPUT ;
    USE SIGNAL ;
    PORT
      LAYER M5 ;
        RECT  34.512 69.036 34.536 69.12 ;
    END
  END cfg_data[59]
  PIN cfg_data[5]
    DIRECTION INPUT ;
    USE SIGNAL ;
    PORT
      LAYER M5 ;
        RECT  19.344 69.036 19.368 69.12 ;
    END
  END cfg_data[5]
  PIN cfg_data[60]
    DIRECTION INPUT ;
    USE SIGNAL ;
    PORT
      LAYER M5 ;
        RECT  34.608 69.036 34.632 69.12 ;
    END
  END cfg_data[60]
  PIN cfg_data[61]
    DIRECTION INPUT ;
    USE SIGNAL ;
    PORT
      LAYER M5 ;
        RECT  34.704 69.036 34.728 69.12 ;
    END
  END cfg_data[61]
  PIN cfg_data[62]
    DIRECTION INPUT ;
    USE SIGNAL ;
    PORT
      LAYER M5 ;
        RECT  34.8 69.036 34.824 69.12 ;
    END
  END cfg_data[62]
  PIN cfg_data[63]
    DIRECTION INPUT ;
    USE SIGNAL ;
    PORT
      LAYER M5 ;
        RECT  34.896 69.036 34.92 69.12 ;
    END
  END cfg_data[63]
  PIN cfg_data[64]
    DIRECTION INPUT ;
    USE SIGNAL ;
    PORT
      LAYER M5 ;
        RECT  34.992 69.036 35.016 69.12 ;
    END
  END cfg_data[64]
  PIN cfg_data[65]
    DIRECTION INPUT ;
    USE SIGNAL ;
    PORT
      LAYER M5 ;
        RECT  35.088 69.036 35.112 69.12 ;
    END
  END cfg_data[65]
  PIN cfg_data[66]
    DIRECTION INPUT ;
    USE SIGNAL ;
    PORT
      LAYER M5 ;
        RECT  35.184 69.036 35.208 69.12 ;
    END
  END cfg_data[66]
  PIN cfg_data[67]
    DIRECTION INPUT ;
    USE SIGNAL ;
    PORT
      LAYER M5 ;
        RECT  35.28 69.036 35.304 69.12 ;
    END
  END cfg_data[67]
  PIN cfg_data[68]
    DIRECTION INPUT ;
    USE SIGNAL ;
    PORT
      LAYER M5 ;
        RECT  35.376 69.036 35.4 69.12 ;
    END
  END cfg_data[68]
  PIN cfg_data[69]
    DIRECTION INPUT ;
    USE SIGNAL ;
    PORT
      LAYER M5 ;
        RECT  35.472 69.036 35.496 69.12 ;
    END
  END cfg_data[69]
  PIN cfg_data[6]
    DIRECTION INPUT ;
    USE SIGNAL ;
    PORT
      LAYER M5 ;
        RECT  19.44 69.036 19.464 69.12 ;
    END
  END cfg_data[6]
  PIN cfg_data[70]
    DIRECTION INPUT ;
    USE SIGNAL ;
    PORT
      LAYER M5 ;
        RECT  35.568 69.036 35.592 69.12 ;
    END
  END cfg_data[70]
  PIN cfg_data[71]
    DIRECTION INPUT ;
    USE SIGNAL ;
    PORT
      LAYER M5 ;
        RECT  35.664 69.036 35.688 69.12 ;
    END
  END cfg_data[71]
  PIN cfg_data[72]
    DIRECTION INPUT ;
    USE SIGNAL ;
    PORT
      LAYER M5 ;
        RECT  35.76 69.036 35.784 69.12 ;
    END
  END cfg_data[72]
  PIN cfg_data[73]
    DIRECTION INPUT ;
    USE SIGNAL ;
    PORT
      LAYER M5 ;
        RECT  35.856 69.036 35.88 69.12 ;
    END
  END cfg_data[73]
  PIN cfg_data[74]
    DIRECTION INPUT ;
    USE SIGNAL ;
    PORT
      LAYER M5 ;
        RECT  35.952 69.036 35.976 69.12 ;
    END
  END cfg_data[74]
  PIN cfg_data[75]
    DIRECTION INPUT ;
    USE SIGNAL ;
    PORT
      LAYER M5 ;
        RECT  36.048 69.036 36.072 69.12 ;
    END
  END cfg_data[75]
  PIN cfg_data[76]
    DIRECTION INPUT ;
    USE SIGNAL ;
    PORT
      LAYER M5 ;
        RECT  36.144 69.036 36.168 69.12 ;
    END
  END cfg_data[76]
  PIN cfg_data[77]
    DIRECTION INPUT ;
    USE SIGNAL ;
    PORT
      LAYER M5 ;
        RECT  36.24 69.036 36.264 69.12 ;
    END
  END cfg_data[77]
  PIN cfg_data[78]
    DIRECTION INPUT ;
    USE SIGNAL ;
    PORT
      LAYER M5 ;
        RECT  36.336 69.036 36.36 69.12 ;
    END
  END cfg_data[78]
  PIN cfg_data[79]
    DIRECTION INPUT ;
    USE SIGNAL ;
    PORT
      LAYER M5 ;
        RECT  36.432 69.036 36.456 69.12 ;
    END
  END cfg_data[79]
  PIN cfg_data[7]
    DIRECTION INPUT ;
    USE SIGNAL ;
    PORT
      LAYER M5 ;
        RECT  19.536 69.036 19.56 69.12 ;
    END
  END cfg_data[7]
  PIN cfg_data[80]
    DIRECTION INPUT ;
    USE SIGNAL ;
    PORT
      LAYER M5 ;
        RECT  36.528 69.036 36.552 69.12 ;
    END
  END cfg_data[80]
  PIN cfg_data[81]
    DIRECTION INPUT ;
    USE SIGNAL ;
    PORT
      LAYER M5 ;
        RECT  36.624 69.036 36.648 69.12 ;
    END
  END cfg_data[81]
  PIN cfg_data[82]
    DIRECTION INPUT ;
    USE SIGNAL ;
    PORT
      LAYER M5 ;
        RECT  36.72 69.036 36.744 69.12 ;
    END
  END cfg_data[82]
  PIN cfg_data[83]
    DIRECTION INPUT ;
    USE SIGNAL ;
    PORT
      LAYER M5 ;
        RECT  36.816 69.036 36.84 69.12 ;
    END
  END cfg_data[83]
  PIN cfg_data[84]
    DIRECTION INPUT ;
    USE SIGNAL ;
    PORT
      LAYER M5 ;
        RECT  43.056 69.036 43.08 69.12 ;
    END
  END cfg_data[84]
  PIN cfg_data[85]
    DIRECTION INPUT ;
    USE SIGNAL ;
    PORT
      LAYER M5 ;
        RECT  43.152 69.036 43.176 69.12 ;
    END
  END cfg_data[85]
  PIN cfg_data[86]
    DIRECTION INPUT ;
    USE SIGNAL ;
    PORT
      LAYER M5 ;
        RECT  43.248 69.036 43.272 69.12 ;
    END
  END cfg_data[86]
  PIN cfg_data[87]
    DIRECTION INPUT ;
    USE SIGNAL ;
    PORT
      LAYER M5 ;
        RECT  43.344 69.036 43.368 69.12 ;
    END
  END cfg_data[87]
  PIN cfg_data[88]
    DIRECTION INPUT ;
    USE SIGNAL ;
    PORT
      LAYER M5 ;
        RECT  43.44 69.036 43.464 69.12 ;
    END
  END cfg_data[88]
  PIN cfg_data[89]
    DIRECTION INPUT ;
    USE SIGNAL ;
    PORT
      LAYER M5 ;
        RECT  43.536 69.036 43.56 69.12 ;
    END
  END cfg_data[89]
  PIN cfg_data[8]
    DIRECTION INPUT ;
    USE SIGNAL ;
    PORT
      LAYER M5 ;
        RECT  19.632 69.036 19.656 69.12 ;
    END
  END cfg_data[8]
  PIN cfg_data[90]
    DIRECTION INPUT ;
    USE SIGNAL ;
    PORT
      LAYER M5 ;
        RECT  43.632 69.036 43.656 69.12 ;
    END
  END cfg_data[90]
  PIN cfg_data[91]
    DIRECTION INPUT ;
    USE SIGNAL ;
    PORT
      LAYER M5 ;
        RECT  43.728 69.036 43.752 69.12 ;
    END
  END cfg_data[91]
  PIN cfg_data[92]
    DIRECTION INPUT ;
    USE SIGNAL ;
    PORT
      LAYER M5 ;
        RECT  43.824 69.036 43.848 69.12 ;
    END
  END cfg_data[92]
  PIN cfg_data[93]
    DIRECTION INPUT ;
    USE SIGNAL ;
    PORT
      LAYER M5 ;
        RECT  43.92 69.036 43.944 69.12 ;
    END
  END cfg_data[93]
  PIN cfg_data[94]
    DIRECTION INPUT ;
    USE SIGNAL ;
    PORT
      LAYER M5 ;
        RECT  44.016 69.036 44.04 69.12 ;
    END
  END cfg_data[94]
  PIN cfg_data[95]
    DIRECTION INPUT ;
    USE SIGNAL ;
    PORT
      LAYER M5 ;
        RECT  44.112 69.036 44.136 69.12 ;
    END
  END cfg_data[95]
  PIN cfg_data[96]
    DIRECTION INPUT ;
    USE SIGNAL ;
    PORT
      LAYER M5 ;
        RECT  44.208 69.036 44.232 69.12 ;
    END
  END cfg_data[96]
  PIN cfg_data[97]
    DIRECTION INPUT ;
    USE SIGNAL ;
    PORT
      LAYER M5 ;
        RECT  44.304 69.036 44.328 69.12 ;
    END
  END cfg_data[97]
  PIN cfg_data[98]
    DIRECTION INPUT ;
    USE SIGNAL ;
    PORT
      LAYER M5 ;
        RECT  44.4 69.036 44.424 69.12 ;
    END
  END cfg_data[98]
  PIN cfg_data[99]
    DIRECTION INPUT ;
    USE SIGNAL ;
    PORT
      LAYER M5 ;
        RECT  44.496 69.036 44.52 69.12 ;
    END
  END cfg_data[99]
  PIN cfg_data[9]
    DIRECTION INPUT ;
    USE SIGNAL ;
    PORT
      LAYER M5 ;
        RECT  19.728 69.036 19.752 69.12 ;
    END
  END cfg_data[9]
  PIN cfg_target[0]
    DIRECTION INPUT ;
    USE SIGNAL ;
    PORT
      LAYER M5 ;
        RECT  28.08 69.036 28.104 69.12 ;
    END
  END cfg_target[0]
  PIN cfg_target[1]
    DIRECTION INPUT ;
    USE SIGNAL ;
    PORT
      LAYER M5 ;
        RECT  28.176 69.036 28.2 69.12 ;
    END
  END cfg_target[1]
  PIN cfg_target[2]
    DIRECTION INPUT ;
    USE SIGNAL ;
    PORT
      LAYER M5 ;
        RECT  28.272 69.036 28.296 69.12 ;
    END
  END cfg_target[2]
  PIN cfg_target[3]
    DIRECTION INPUT ;
    USE SIGNAL ;
    PORT
      LAYER M5 ;
        RECT  28.368 69.036 28.392 69.12 ;
    END
  END cfg_target[3]
  PIN cfg_target[4]
    DIRECTION INPUT ;
    USE SIGNAL ;
    PORT
      LAYER M5 ;
        RECT  28.464 69.036 28.488 69.12 ;
    END
  END cfg_target[4]
  PIN cfg_target[5]
    DIRECTION INPUT ;
    USE SIGNAL ;
    PORT
      LAYER M5 ;
        RECT  28.56 69.036 28.584 69.12 ;
    END
  END cfg_target[5]
  PIN cfg_target[6]
    DIRECTION INPUT ;
    USE SIGNAL ;
    PORT
      LAYER M5 ;
        RECT  28.656 69.036 28.68 69.12 ;
    END
  END cfg_target[6]
  PIN cfg_target[7]
    DIRECTION INPUT ;
    USE SIGNAL ;
    PORT
      LAYER M5 ;
        RECT  28.752 69.036 28.776 69.12 ;
    END
  END cfg_target[7]
  PIN cfg_v
    DIRECTION INPUT ;
    USE SIGNAL ;
    PORT
      LAYER M5 ;
        RECT  28.848 69.036 28.872 69.12 ;
    END
  END cfg_v
  PIN clk
    DIRECTION INPUT ;
    USE SIGNAL ;
    PORT
      LAYER M5 ;
        RECT  28.944 69.036 28.968 69.12 ;
    END
  END clk
  PIN desc_base[0]
    DIRECTION INPUT ;
    USE SIGNAL ;
    PORT
      LAYER M5 ;
        RECT  29.04 69.036 29.064 69.12 ;
    END
  END desc_base[0]
  PIN desc_base[10]
    DIRECTION INPUT ;
    USE SIGNAL ;
    PORT
      LAYER M5 ;
        RECT  20.784 69.036 20.808 69.12 ;
    END
  END desc_base[10]
  PIN desc_base[11]
    DIRECTION INPUT ;
    USE SIGNAL ;
    PORT
      LAYER M5 ;
        RECT  20.88 69.036 20.904 69.12 ;
    END
  END desc_base[11]
  PIN desc_base[1]
    DIRECTION INPUT ;
    USE SIGNAL ;
    PORT
      LAYER M5 ;
        RECT  29.136 69.036 29.16 69.12 ;
    END
  END desc_base[1]
  PIN desc_base[2]
    DIRECTION INPUT ;
    USE SIGNAL ;
    PORT
      LAYER M5 ;
        RECT  29.232 69.036 29.256 69.12 ;
    END
  END desc_base[2]
  PIN desc_base[3]
    DIRECTION INPUT ;
    USE SIGNAL ;
    PORT
      LAYER M5 ;
        RECT  29.328 69.036 29.352 69.12 ;
    END
  END desc_base[3]
  PIN desc_base[4]
    DIRECTION INPUT ;
    USE SIGNAL ;
    PORT
      LAYER M5 ;
        RECT  29.424 69.036 29.448 69.12 ;
    END
  END desc_base[4]
  PIN desc_base[5]
    DIRECTION INPUT ;
    USE SIGNAL ;
    PORT
      LAYER M5 ;
        RECT  29.52 69.036 29.544 69.12 ;
    END
  END desc_base[5]
  PIN desc_base[6]
    DIRECTION INPUT ;
    USE SIGNAL ;
    PORT
      LAYER M5 ;
        RECT  29.616 69.036 29.64 69.12 ;
    END
  END desc_base[6]
  PIN desc_base[7]
    DIRECTION INPUT ;
    USE SIGNAL ;
    PORT
      LAYER M5 ;
        RECT  29.712 69.036 29.736 69.12 ;
    END
  END desc_base[7]
  PIN desc_base[8]
    DIRECTION INPUT ;
    USE SIGNAL ;
    PORT
      LAYER M5 ;
        RECT  29.808 69.036 29.832 69.12 ;
    END
  END desc_base[8]
  PIN desc_base[9]
    DIRECTION INPUT ;
    USE SIGNAL ;
    PORT
      LAYER M5 ;
        RECT  29.904 69.036 29.928 69.12 ;
    END
  END desc_base[9]
  PIN desc_limit[0]
    DIRECTION INPUT ;
    USE SIGNAL ;
    PORT
      LAYER M5 ;
        RECT  20.976 69.036 21 69.12 ;
    END
  END desc_limit[0]
  PIN desc_limit[10]
    DIRECTION INPUT ;
    USE SIGNAL ;
    PORT
      LAYER M5 ;
        RECT  21.936 69.036 21.96 69.12 ;
    END
  END desc_limit[10]
  PIN desc_limit[11]
    DIRECTION INPUT ;
    USE SIGNAL ;
    PORT
      LAYER M5 ;
        RECT  22.032 69.036 22.056 69.12 ;
    END
  END desc_limit[11]
  PIN desc_limit[12]
    DIRECTION INPUT ;
    USE SIGNAL ;
    PORT
      LAYER M5 ;
        RECT  22.128 69.036 22.152 69.12 ;
    END
  END desc_limit[12]
  PIN desc_limit[1]
    DIRECTION INPUT ;
    USE SIGNAL ;
    PORT
      LAYER M5 ;
        RECT  21.072 69.036 21.096 69.12 ;
    END
  END desc_limit[1]
  PIN desc_limit[2]
    DIRECTION INPUT ;
    USE SIGNAL ;
    PORT
      LAYER M5 ;
        RECT  21.168 69.036 21.192 69.12 ;
    END
  END desc_limit[2]
  PIN desc_limit[3]
    DIRECTION INPUT ;
    USE SIGNAL ;
    PORT
      LAYER M5 ;
        RECT  21.264 69.036 21.288 69.12 ;
    END
  END desc_limit[3]
  PIN desc_limit[4]
    DIRECTION INPUT ;
    USE SIGNAL ;
    PORT
      LAYER M5 ;
        RECT  21.36 69.036 21.384 69.12 ;
    END
  END desc_limit[4]
  PIN desc_limit[5]
    DIRECTION INPUT ;
    USE SIGNAL ;
    PORT
      LAYER M5 ;
        RECT  21.456 69.036 21.48 69.12 ;
    END
  END desc_limit[5]
  PIN desc_limit[6]
    DIRECTION INPUT ;
    USE SIGNAL ;
    PORT
      LAYER M5 ;
        RECT  21.552 69.036 21.576 69.12 ;
    END
  END desc_limit[6]
  PIN desc_limit[7]
    DIRECTION INPUT ;
    USE SIGNAL ;
    PORT
      LAYER M5 ;
        RECT  21.648 69.036 21.672 69.12 ;
    END
  END desc_limit[7]
  PIN desc_limit[8]
    DIRECTION INPUT ;
    USE SIGNAL ;
    PORT
      LAYER M5 ;
        RECT  21.744 69.036 21.768 69.12 ;
    END
  END desc_limit[8]
  PIN desc_limit[9]
    DIRECTION INPUT ;
    USE SIGNAL ;
    PORT
      LAYER M5 ;
        RECT  21.84 69.036 21.864 69.12 ;
    END
  END desc_limit[9]
  PIN desc_loops[0]
    DIRECTION INPUT ;
    USE SIGNAL ;
    PORT
      LAYER M5 ;
        RECT  22.224 69.036 22.248 69.12 ;
    END
  END desc_loops[0]
  PIN desc_loops[10]
    DIRECTION INPUT ;
    USE SIGNAL ;
    PORT
      LAYER M5 ;
        RECT  23.184 69.036 23.208 69.12 ;
    END
  END desc_loops[10]
  PIN desc_loops[11]
    DIRECTION INPUT ;
    USE SIGNAL ;
    PORT
      LAYER M5 ;
        RECT  23.28 69.036 23.304 69.12 ;
    END
  END desc_loops[11]
  PIN desc_loops[12]
    DIRECTION INPUT ;
    USE SIGNAL ;
    PORT
      LAYER M5 ;
        RECT  23.376 69.036 23.4 69.12 ;
    END
  END desc_loops[12]
  PIN desc_loops[13]
    DIRECTION INPUT ;
    USE SIGNAL ;
    PORT
      LAYER M5 ;
        RECT  23.472 69.036 23.496 69.12 ;
    END
  END desc_loops[13]
  PIN desc_loops[14]
    DIRECTION INPUT ;
    USE SIGNAL ;
    PORT
      LAYER M5 ;
        RECT  23.568 69.036 23.592 69.12 ;
    END
  END desc_loops[14]
  PIN desc_loops[15]
    DIRECTION INPUT ;
    USE SIGNAL ;
    PORT
      LAYER M5 ;
        RECT  23.664 69.036 23.688 69.12 ;
    END
  END desc_loops[15]
  PIN desc_loops[1]
    DIRECTION INPUT ;
    USE SIGNAL ;
    PORT
      LAYER M5 ;
        RECT  22.32 69.036 22.344 69.12 ;
    END
  END desc_loops[1]
  PIN desc_loops[2]
    DIRECTION INPUT ;
    USE SIGNAL ;
    PORT
      LAYER M5 ;
        RECT  22.416 69.036 22.44 69.12 ;
    END
  END desc_loops[2]
  PIN desc_loops[3]
    DIRECTION INPUT ;
    USE SIGNAL ;
    PORT
      LAYER M5 ;
        RECT  22.512 69.036 22.536 69.12 ;
    END
  END desc_loops[3]
  PIN desc_loops[4]
    DIRECTION INPUT ;
    USE SIGNAL ;
    PORT
      LAYER M5 ;
        RECT  22.608 69.036 22.632 69.12 ;
    END
  END desc_loops[4]
  PIN desc_loops[5]
    DIRECTION INPUT ;
    USE SIGNAL ;
    PORT
      LAYER M5 ;
        RECT  22.704 69.036 22.728 69.12 ;
    END
  END desc_loops[5]
  PIN desc_loops[6]
    DIRECTION INPUT ;
    USE SIGNAL ;
    PORT
      LAYER M5 ;
        RECT  22.8 69.036 22.824 69.12 ;
    END
  END desc_loops[6]
  PIN desc_loops[7]
    DIRECTION INPUT ;
    USE SIGNAL ;
    PORT
      LAYER M5 ;
        RECT  22.896 69.036 22.92 69.12 ;
    END
  END desc_loops[7]
  PIN desc_loops[8]
    DIRECTION INPUT ;
    USE SIGNAL ;
    PORT
      LAYER M5 ;
        RECT  22.992 69.036 23.016 69.12 ;
    END
  END desc_loops[8]
  PIN desc_loops[9]
    DIRECTION INPUT ;
    USE SIGNAL ;
    PORT
      LAYER M5 ;
        RECT  23.088 69.036 23.112 69.12 ;
    END
  END desc_loops[9]
  PIN desc_v
    DIRECTION INPUT ;
    USE SIGNAL ;
    PORT
      LAYER M5 ;
        RECT  23.76 69.036 23.784 69.12 ;
    END
  END desc_v
  PIN launch_v
    DIRECTION INPUT ;
    USE SIGNAL ;
    PORT
      LAYER M5 ;
        RECT  30.576 69.036 30.6 69.12 ;
    END
  END launch_v
  PIN rst_n
    DIRECTION INPUT ;
    USE SIGNAL ;
    PORT
      LAYER M5 ;
        RECT  30.672 69.036 30.696 69.12 ;
    END
  END rst_n
  PIN s_active[0]
    DIRECTION OUTPUT ;
    USE SIGNAL ;
    PORT
      LAYER M5 ;
        RECT  35.28 0 35.304 0.084 ;
    END
  END s_active[0]
  PIN s_active[10]
    DIRECTION OUTPUT ;
    USE SIGNAL ;
    PORT
      LAYER M5 ;
        RECT  36.24 0 36.264 0.084 ;
    END
  END s_active[10]
  PIN s_active[11]
    DIRECTION OUTPUT ;
    USE SIGNAL ;
    PORT
      LAYER M5 ;
        RECT  36.336 0 36.36 0.084 ;
    END
  END s_active[11]
  PIN s_active[12]
    DIRECTION OUTPUT ;
    USE SIGNAL ;
    PORT
      LAYER M5 ;
        RECT  36.432 0 36.456 0.084 ;
    END
  END s_active[12]
  PIN s_active[13]
    DIRECTION OUTPUT ;
    USE SIGNAL ;
    PORT
      LAYER M5 ;
        RECT  36.528 0 36.552 0.084 ;
    END
  END s_active[13]
  PIN s_active[14]
    DIRECTION OUTPUT ;
    USE SIGNAL ;
    PORT
      LAYER M5 ;
        RECT  36.624 0 36.648 0.084 ;
    END
  END s_active[14]
  PIN s_active[15]
    DIRECTION OUTPUT ;
    USE SIGNAL ;
    PORT
      LAYER M5 ;
        RECT  36.72 0 36.744 0.084 ;
    END
  END s_active[15]
  PIN s_active[16]
    DIRECTION OUTPUT ;
    USE SIGNAL ;
    PORT
      LAYER M5 ;
        RECT  36.816 0 36.84 0.084 ;
    END
  END s_active[16]
  PIN s_active[17]
    DIRECTION OUTPUT ;
    USE SIGNAL ;
    PORT
      LAYER M5 ;
        RECT  36.912 0 36.936 0.084 ;
    END
  END s_active[17]
  PIN s_active[18]
    DIRECTION OUTPUT ;
    USE SIGNAL ;
    PORT
      LAYER M5 ;
        RECT  37.008 0 37.032 0.084 ;
    END
  END s_active[18]
  PIN s_active[1]
    DIRECTION OUTPUT ;
    USE SIGNAL ;
    PORT
      LAYER M5 ;
        RECT  35.376 0 35.4 0.084 ;
    END
  END s_active[1]
  PIN s_active[2]
    DIRECTION OUTPUT ;
    USE SIGNAL ;
    PORT
      LAYER M5 ;
        RECT  35.472 0 35.496 0.084 ;
    END
  END s_active[2]
  PIN s_active[3]
    DIRECTION OUTPUT ;
    USE SIGNAL ;
    PORT
      LAYER M5 ;
        RECT  35.568 0 35.592 0.084 ;
    END
  END s_active[3]
  PIN s_active[4]
    DIRECTION OUTPUT ;
    USE SIGNAL ;
    PORT
      LAYER M5 ;
        RECT  35.664 0 35.688 0.084 ;
    END
  END s_active[4]
  PIN s_active[5]
    DIRECTION OUTPUT ;
    USE SIGNAL ;
    PORT
      LAYER M5 ;
        RECT  35.76 0 35.784 0.084 ;
    END
  END s_active[5]
  PIN s_active[6]
    DIRECTION OUTPUT ;
    USE SIGNAL ;
    PORT
      LAYER M5 ;
        RECT  35.856 0 35.88 0.084 ;
    END
  END s_active[6]
  PIN s_active[7]
    DIRECTION OUTPUT ;
    USE SIGNAL ;
    PORT
      LAYER M5 ;
        RECT  35.952 0 35.976 0.084 ;
    END
  END s_active[7]
  PIN s_active[8]
    DIRECTION OUTPUT ;
    USE SIGNAL ;
    PORT
      LAYER M5 ;
        RECT  36.048 0 36.072 0.084 ;
    END
  END s_active[8]
  PIN s_active[9]
    DIRECTION OUTPUT ;
    USE SIGNAL ;
    PORT
      LAYER M5 ;
        RECT  36.144 0 36.168 0.084 ;
    END
  END s_active[9]
  PIN s_fault[0]
    DIRECTION OUTPUT ;
    USE SIGNAL ;
    PORT
      LAYER M5 ;
        RECT  37.104 0 37.128 0.084 ;
    END
  END s_fault[0]
  PIN s_fault[10]
    DIRECTION OUTPUT ;
    USE SIGNAL ;
    PORT
      LAYER M5 ;
        RECT  38.064 0 38.088 0.084 ;
    END
  END s_fault[10]
  PIN s_fault[11]
    DIRECTION OUTPUT ;
    USE SIGNAL ;
    PORT
      LAYER M5 ;
        RECT  38.16 0 38.184 0.084 ;
    END
  END s_fault[11]
  PIN s_fault[12]
    DIRECTION OUTPUT ;
    USE SIGNAL ;
    PORT
      LAYER M5 ;
        RECT  38.256 0 38.28 0.084 ;
    END
  END s_fault[12]
  PIN s_fault[13]
    DIRECTION OUTPUT ;
    USE SIGNAL ;
    PORT
      LAYER M5 ;
        RECT  39.12 0 39.144 0.084 ;
    END
  END s_fault[13]
  PIN s_fault[14]
    DIRECTION OUTPUT ;
    USE SIGNAL ;
    PORT
      LAYER M5 ;
        RECT  39.216 0 39.24 0.084 ;
    END
  END s_fault[14]
  PIN s_fault[15]
    DIRECTION OUTPUT ;
    USE SIGNAL ;
    PORT
      LAYER M5 ;
        RECT  39.312 0 39.336 0.084 ;
    END
  END s_fault[15]
  PIN s_fault[16]
    DIRECTION OUTPUT ;
    USE SIGNAL ;
    PORT
      LAYER M5 ;
        RECT  39.408 0 39.432 0.084 ;
    END
  END s_fault[16]
  PIN s_fault[17]
    DIRECTION OUTPUT ;
    USE SIGNAL ;
    PORT
      LAYER M5 ;
        RECT  39.504 0 39.528 0.084 ;
    END
  END s_fault[17]
  PIN s_fault[18]
    DIRECTION OUTPUT ;
    USE SIGNAL ;
    PORT
      LAYER M5 ;
        RECT  39.6 0 39.624 0.084 ;
    END
  END s_fault[18]
  PIN s_fault[19]
    DIRECTION OUTPUT ;
    USE SIGNAL ;
    PORT
      LAYER M5 ;
        RECT  39.696 0 39.72 0.084 ;
    END
  END s_fault[19]
  PIN s_fault[1]
    DIRECTION OUTPUT ;
    USE SIGNAL ;
    PORT
      LAYER M5 ;
        RECT  37.2 0 37.224 0.084 ;
    END
  END s_fault[1]
  PIN s_fault[20]
    DIRECTION OUTPUT ;
    USE SIGNAL ;
    PORT
      LAYER M5 ;
        RECT  39.792 0 39.816 0.084 ;
    END
  END s_fault[20]
  PIN s_fault[21]
    DIRECTION OUTPUT ;
    USE SIGNAL ;
    PORT
      LAYER M5 ;
        RECT  39.888 0 39.912 0.084 ;
    END
  END s_fault[21]
  PIN s_fault[22]
    DIRECTION OUTPUT ;
    USE SIGNAL ;
    PORT
      LAYER M5 ;
        RECT  39.984 0 40.008 0.084 ;
    END
  END s_fault[22]
  PIN s_fault[23]
    DIRECTION OUTPUT ;
    USE SIGNAL ;
    PORT
      LAYER M5 ;
        RECT  40.08 0 40.104 0.084 ;
    END
  END s_fault[23]
  PIN s_fault[24]
    DIRECTION OUTPUT ;
    USE SIGNAL ;
    PORT
      LAYER M5 ;
        RECT  40.176 0 40.2 0.084 ;
    END
  END s_fault[24]
  PIN s_fault[25]
    DIRECTION OUTPUT ;
    USE SIGNAL ;
    PORT
      LAYER M5 ;
        RECT  40.272 0 40.296 0.084 ;
    END
  END s_fault[25]
  PIN s_fault[26]
    DIRECTION OUTPUT ;
    USE SIGNAL ;
    PORT
      LAYER M5 ;
        RECT  40.368 0 40.392 0.084 ;
    END
  END s_fault[26]
  PIN s_fault[27]
    DIRECTION OUTPUT ;
    USE SIGNAL ;
    PORT
      LAYER M5 ;
        RECT  40.464 0 40.488 0.084 ;
    END
  END s_fault[27]
  PIN s_fault[28]
    DIRECTION OUTPUT ;
    USE SIGNAL ;
    PORT
      LAYER M5 ;
        RECT  40.56 0 40.584 0.084 ;
    END
  END s_fault[28]
  PIN s_fault[2]
    DIRECTION OUTPUT ;
    USE SIGNAL ;
    PORT
      LAYER M5 ;
        RECT  37.296 0 37.32 0.084 ;
    END
  END s_fault[2]
  PIN s_fault[3]
    DIRECTION OUTPUT ;
    USE SIGNAL ;
    PORT
      LAYER M5 ;
        RECT  37.392 0 37.416 0.084 ;
    END
  END s_fault[3]
  PIN s_fault[4]
    DIRECTION OUTPUT ;
    USE SIGNAL ;
    PORT
      LAYER M5 ;
        RECT  37.488 0 37.512 0.084 ;
    END
  END s_fault[4]
  PIN s_fault[5]
    DIRECTION OUTPUT ;
    USE SIGNAL ;
    PORT
      LAYER M5 ;
        RECT  37.584 0 37.608 0.084 ;
    END
  END s_fault[5]
  PIN s_fault[6]
    DIRECTION OUTPUT ;
    USE SIGNAL ;
    PORT
      LAYER M5 ;
        RECT  37.68 0 37.704 0.084 ;
    END
  END s_fault[6]
  PIN s_fault[7]
    DIRECTION OUTPUT ;
    USE SIGNAL ;
    PORT
      LAYER M5 ;
        RECT  37.776 0 37.8 0.084 ;
    END
  END s_fault[7]
  PIN s_fault[8]
    DIRECTION OUTPUT ;
    USE SIGNAL ;
    PORT
      LAYER M5 ;
        RECT  37.872 0 37.896 0.084 ;
    END
  END s_fault[8]
  PIN s_fault[9]
    DIRECTION OUTPUT ;
    USE SIGNAL ;
    PORT
      LAYER M5 ;
        RECT  37.968 0 37.992 0.084 ;
    END
  END s_fault[9]
  PIN s_ready[0]
    DIRECTION OUTPUT ;
    USE SIGNAL ;
    PORT
      LAYER M5 ;
        RECT  40.656 0 40.68 0.084 ;
    END
  END s_ready[0]
  PIN s_ready[10]
    DIRECTION OUTPUT ;
    USE SIGNAL ;
    PORT
      LAYER M5 ;
        RECT  41.616 0 41.64 0.084 ;
    END
  END s_ready[10]
  PIN s_ready[11]
    DIRECTION OUTPUT ;
    USE SIGNAL ;
    PORT
      LAYER M5 ;
        RECT  41.712 0 41.736 0.084 ;
    END
  END s_ready[11]
  PIN s_ready[12]
    DIRECTION OUTPUT ;
    USE SIGNAL ;
    PORT
      LAYER M5 ;
        RECT  41.808 0 41.832 0.084 ;
    END
  END s_ready[12]
  PIN s_ready[13]
    DIRECTION OUTPUT ;
    USE SIGNAL ;
    PORT
      LAYER M5 ;
        RECT  41.904 0 41.928 0.084 ;
    END
  END s_ready[13]
  PIN s_ready[14]
    DIRECTION OUTPUT ;
    USE SIGNAL ;
    PORT
      LAYER M5 ;
        RECT  42 0 42.024 0.084 ;
    END
  END s_ready[14]
  PIN s_ready[15]
    DIRECTION OUTPUT ;
    USE SIGNAL ;
    PORT
      LAYER M5 ;
        RECT  42.096 0 42.12 0.084 ;
    END
  END s_ready[15]
  PIN s_ready[16]
    DIRECTION OUTPUT ;
    USE SIGNAL ;
    PORT
      LAYER M5 ;
        RECT  29.136 0 29.16 0.084 ;
    END
  END s_ready[16]
  PIN s_ready[17]
    DIRECTION OUTPUT ;
    USE SIGNAL ;
    PORT
      LAYER M5 ;
        RECT  29.232 0 29.256 0.084 ;
    END
  END s_ready[17]
  PIN s_ready[18]
    DIRECTION OUTPUT ;
    USE SIGNAL ;
    PORT
      LAYER M5 ;
        RECT  29.328 0 29.352 0.084 ;
    END
  END s_ready[18]
  PIN s_ready[1]
    DIRECTION OUTPUT ;
    USE SIGNAL ;
    PORT
      LAYER M5 ;
        RECT  40.752 0 40.776 0.084 ;
    END
  END s_ready[1]
  PIN s_ready[2]
    DIRECTION OUTPUT ;
    USE SIGNAL ;
    PORT
      LAYER M5 ;
        RECT  40.848 0 40.872 0.084 ;
    END
  END s_ready[2]
  PIN s_ready[3]
    DIRECTION OUTPUT ;
    USE SIGNAL ;
    PORT
      LAYER M5 ;
        RECT  40.944 0 40.968 0.084 ;
    END
  END s_ready[3]
  PIN s_ready[4]
    DIRECTION OUTPUT ;
    USE SIGNAL ;
    PORT
      LAYER M5 ;
        RECT  41.04 0 41.064 0.084 ;
    END
  END s_ready[4]
  PIN s_ready[5]
    DIRECTION OUTPUT ;
    USE SIGNAL ;
    PORT
      LAYER M5 ;
        RECT  41.136 0 41.16 0.084 ;
    END
  END s_ready[5]
  PIN s_ready[6]
    DIRECTION OUTPUT ;
    USE SIGNAL ;
    PORT
      LAYER M5 ;
        RECT  41.232 0 41.256 0.084 ;
    END
  END s_ready[6]
  PIN s_ready[7]
    DIRECTION OUTPUT ;
    USE SIGNAL ;
    PORT
      LAYER M5 ;
        RECT  41.328 0 41.352 0.084 ;
    END
  END s_ready[7]
  PIN s_ready[8]
    DIRECTION OUTPUT ;
    USE SIGNAL ;
    PORT
      LAYER M5 ;
        RECT  41.424 0 41.448 0.084 ;
    END
  END s_ready[8]
  PIN s_ready[9]
    DIRECTION OUTPUT ;
    USE SIGNAL ;
    PORT
      LAYER M5 ;
        RECT  41.52 0 41.544 0.084 ;
    END
  END s_ready[9]
  PIN t_active[0]
    DIRECTION INPUT ;
    USE SIGNAL ;
    PORT
      LAYER M5 ;
        RECT  29.424 0 29.448 0.084 ;
    END
  END t_active[0]
  PIN t_active[10]
    DIRECTION INPUT ;
    USE SIGNAL ;
    PORT
      LAYER M5 ;
        RECT  30.384 0 30.408 0.084 ;
    END
  END t_active[10]
  PIN t_active[11]
    DIRECTION INPUT ;
    USE SIGNAL ;
    PORT
      LAYER M5 ;
        RECT  30.48 0 30.504 0.084 ;
    END
  END t_active[11]
  PIN t_active[12]
    DIRECTION INPUT ;
    USE SIGNAL ;
    PORT
      LAYER M5 ;
        RECT  30.576 0 30.6 0.084 ;
    END
  END t_active[12]
  PIN t_active[13]
    DIRECTION INPUT ;
    USE SIGNAL ;
    PORT
      LAYER M5 ;
        RECT  30.672 0 30.696 0.084 ;
    END
  END t_active[13]
  PIN t_active[14]
    DIRECTION INPUT ;
    USE SIGNAL ;
    PORT
      LAYER M5 ;
        RECT  30.768 0 30.792 0.084 ;
    END
  END t_active[14]
  PIN t_active[15]
    DIRECTION INPUT ;
    USE SIGNAL ;
    PORT
      LAYER M5 ;
        RECT  30.864 0 30.888 0.084 ;
    END
  END t_active[15]
  PIN t_active[16]
    DIRECTION INPUT ;
    USE SIGNAL ;
    PORT
      LAYER M5 ;
        RECT  30.96 0 30.984 0.084 ;
    END
  END t_active[16]
  PIN t_active[17]
    DIRECTION INPUT ;
    USE SIGNAL ;
    PORT
      LAYER M5 ;
        RECT  31.056 0 31.08 0.084 ;
    END
  END t_active[17]
  PIN t_active[18]
    DIRECTION INPUT ;
    USE SIGNAL ;
    PORT
      LAYER M5 ;
        RECT  31.152 0 31.176 0.084 ;
    END
  END t_active[18]
  PIN t_active[1]
    DIRECTION INPUT ;
    USE SIGNAL ;
    PORT
      LAYER M5 ;
        RECT  29.52 0 29.544 0.084 ;
    END
  END t_active[1]
  PIN t_active[2]
    DIRECTION INPUT ;
    USE SIGNAL ;
    PORT
      LAYER M5 ;
        RECT  29.616 0 29.64 0.084 ;
    END
  END t_active[2]
  PIN t_active[3]
    DIRECTION INPUT ;
    USE SIGNAL ;
    PORT
      LAYER M5 ;
        RECT  29.712 0 29.736 0.084 ;
    END
  END t_active[3]
  PIN t_active[4]
    DIRECTION INPUT ;
    USE SIGNAL ;
    PORT
      LAYER M5 ;
        RECT  29.808 0 29.832 0.084 ;
    END
  END t_active[4]
  PIN t_active[5]
    DIRECTION INPUT ;
    USE SIGNAL ;
    PORT
      LAYER M5 ;
        RECT  29.904 0 29.928 0.084 ;
    END
  END t_active[5]
  PIN t_active[6]
    DIRECTION INPUT ;
    USE SIGNAL ;
    PORT
      LAYER M5 ;
        RECT  30 0 30.024 0.084 ;
    END
  END t_active[6]
  PIN t_active[7]
    DIRECTION INPUT ;
    USE SIGNAL ;
    PORT
      LAYER M5 ;
        RECT  30.096 0 30.12 0.084 ;
    END
  END t_active[7]
  PIN t_active[8]
    DIRECTION INPUT ;
    USE SIGNAL ;
    PORT
      LAYER M5 ;
        RECT  30.192 0 30.216 0.084 ;
    END
  END t_active[8]
  PIN t_active[9]
    DIRECTION INPUT ;
    USE SIGNAL ;
    PORT
      LAYER M5 ;
        RECT  30.288 0 30.312 0.084 ;
    END
  END t_active[9]
  PIN t_fault[0]
    DIRECTION INPUT ;
    USE SIGNAL ;
    PORT
      LAYER M5 ;
        RECT  31.248 0 31.272 0.084 ;
    END
  END t_fault[0]
  PIN t_fault[10]
    DIRECTION INPUT ;
    USE SIGNAL ;
    PORT
      LAYER M5 ;
        RECT  32.208 0 32.232 0.084 ;
    END
  END t_fault[10]
  PIN t_fault[11]
    DIRECTION INPUT ;
    USE SIGNAL ;
    PORT
      LAYER M5 ;
        RECT  32.304 0 32.328 0.084 ;
    END
  END t_fault[11]
  PIN t_fault[12]
    DIRECTION INPUT ;
    USE SIGNAL ;
    PORT
      LAYER M5 ;
        RECT  32.4 0 32.424 0.084 ;
    END
  END t_fault[12]
  PIN t_fault[13]
    DIRECTION INPUT ;
    USE SIGNAL ;
    PORT
      LAYER M5 ;
        RECT  32.496 0 32.52 0.084 ;
    END
  END t_fault[13]
  PIN t_fault[14]
    DIRECTION INPUT ;
    USE SIGNAL ;
    PORT
      LAYER M5 ;
        RECT  32.592 0 32.616 0.084 ;
    END
  END t_fault[14]
  PIN t_fault[15]
    DIRECTION INPUT ;
    USE SIGNAL ;
    PORT
      LAYER M5 ;
        RECT  32.688 0 32.712 0.084 ;
    END
  END t_fault[15]
  PIN t_fault[16]
    DIRECTION INPUT ;
    USE SIGNAL ;
    PORT
      LAYER M5 ;
        RECT  32.784 0 32.808 0.084 ;
    END
  END t_fault[16]
  PIN t_fault[17]
    DIRECTION INPUT ;
    USE SIGNAL ;
    PORT
      LAYER M5 ;
        RECT  32.88 0 32.904 0.084 ;
    END
  END t_fault[17]
  PIN t_fault[18]
    DIRECTION INPUT ;
    USE SIGNAL ;
    PORT
      LAYER M5 ;
        RECT  32.976 0 33 0.084 ;
    END
  END t_fault[18]
  PIN t_fault[19]
    DIRECTION INPUT ;
    USE SIGNAL ;
    PORT
      LAYER M5 ;
        RECT  33.072 0 33.096 0.084 ;
    END
  END t_fault[19]
  PIN t_fault[1]
    DIRECTION INPUT ;
    USE SIGNAL ;
    PORT
      LAYER M5 ;
        RECT  31.344 0 31.368 0.084 ;
    END
  END t_fault[1]
  PIN t_fault[20]
    DIRECTION INPUT ;
    USE SIGNAL ;
    PORT
      LAYER M5 ;
        RECT  33.168 0 33.192 0.084 ;
    END
  END t_fault[20]
  PIN t_fault[21]
    DIRECTION INPUT ;
    USE SIGNAL ;
    PORT
      LAYER M5 ;
        RECT  33.264 0 33.288 0.084 ;
    END
  END t_fault[21]
  PIN t_fault[22]
    DIRECTION INPUT ;
    USE SIGNAL ;
    PORT
      LAYER M5 ;
        RECT  33.36 0 33.384 0.084 ;
    END
  END t_fault[22]
  PIN t_fault[23]
    DIRECTION INPUT ;
    USE SIGNAL ;
    PORT
      LAYER M5 ;
        RECT  33.456 0 33.48 0.084 ;
    END
  END t_fault[23]
  PIN t_fault[24]
    DIRECTION INPUT ;
    USE SIGNAL ;
    PORT
      LAYER M5 ;
        RECT  33.552 0 33.576 0.084 ;
    END
  END t_fault[24]
  PIN t_fault[25]
    DIRECTION INPUT ;
    USE SIGNAL ;
    PORT
      LAYER M5 ;
        RECT  33.648 0 33.672 0.084 ;
    END
  END t_fault[25]
  PIN t_fault[26]
    DIRECTION INPUT ;
    USE SIGNAL ;
    PORT
      LAYER M5 ;
        RECT  33.744 0 33.768 0.084 ;
    END
  END t_fault[26]
  PIN t_fault[27]
    DIRECTION INPUT ;
    USE SIGNAL ;
    PORT
      LAYER M5 ;
        RECT  33.84 0 33.864 0.084 ;
    END
  END t_fault[27]
  PIN t_fault[28]
    DIRECTION INPUT ;
    USE SIGNAL ;
    PORT
      LAYER M5 ;
        RECT  33.936 0 33.96 0.084 ;
    END
  END t_fault[28]
  PIN t_fault[2]
    DIRECTION INPUT ;
    USE SIGNAL ;
    PORT
      LAYER M5 ;
        RECT  31.44 0 31.464 0.084 ;
    END
  END t_fault[2]
  PIN t_fault[3]
    DIRECTION INPUT ;
    USE SIGNAL ;
    PORT
      LAYER M5 ;
        RECT  31.536 0 31.56 0.084 ;
    END
  END t_fault[3]
  PIN t_fault[4]
    DIRECTION INPUT ;
    USE SIGNAL ;
    PORT
      LAYER M5 ;
        RECT  31.632 0 31.656 0.084 ;
    END
  END t_fault[4]
  PIN t_fault[5]
    DIRECTION INPUT ;
    USE SIGNAL ;
    PORT
      LAYER M5 ;
        RECT  31.728 0 31.752 0.084 ;
    END
  END t_fault[5]
  PIN t_fault[6]
    DIRECTION INPUT ;
    USE SIGNAL ;
    PORT
      LAYER M5 ;
        RECT  31.824 0 31.848 0.084 ;
    END
  END t_fault[6]
  PIN t_fault[7]
    DIRECTION INPUT ;
    USE SIGNAL ;
    PORT
      LAYER M5 ;
        RECT  31.92 0 31.944 0.084 ;
    END
  END t_fault[7]
  PIN t_fault[8]
    DIRECTION INPUT ;
    USE SIGNAL ;
    PORT
      LAYER M5 ;
        RECT  32.016 0 32.04 0.084 ;
    END
  END t_fault[8]
  PIN t_fault[9]
    DIRECTION INPUT ;
    USE SIGNAL ;
    PORT
      LAYER M5 ;
        RECT  32.112 0 32.136 0.084 ;
    END
  END t_fault[9]
  PIN t_ready[0]
    DIRECTION INPUT ;
    USE SIGNAL ;
    PORT
      LAYER M5 ;
        RECT  34.032 0 34.056 0.084 ;
    END
  END t_ready[0]
  PIN t_ready[10]
    DIRECTION INPUT ;
    USE SIGNAL ;
    PORT
      LAYER M5 ;
        RECT  34.992 0 35.016 0.084 ;
    END
  END t_ready[10]
  PIN t_ready[11]
    DIRECTION INPUT ;
    USE SIGNAL ;
    PORT
      LAYER M5 ;
        RECT  35.088 0 35.112 0.084 ;
    END
  END t_ready[11]
  PIN t_ready[12]
    DIRECTION INPUT ;
    USE SIGNAL ;
    PORT
      LAYER M5 ;
        RECT  35.184 0 35.208 0.084 ;
    END
  END t_ready[12]
  PIN t_ready[13]
    DIRECTION INPUT ;
    USE SIGNAL ;
    PORT
      LAYER M5 ;
        RECT  38.352 0 38.376 0.084 ;
    END
  END t_ready[13]
  PIN t_ready[14]
    DIRECTION INPUT ;
    USE SIGNAL ;
    PORT
      LAYER M5 ;
        RECT  38.448 0 38.472 0.084 ;
    END
  END t_ready[14]
  PIN t_ready[15]
    DIRECTION INPUT ;
    USE SIGNAL ;
    PORT
      LAYER M5 ;
        RECT  38.544 0 38.568 0.084 ;
    END
  END t_ready[15]
  PIN t_ready[16]
    DIRECTION INPUT ;
    USE SIGNAL ;
    PORT
      LAYER M5 ;
        RECT  38.64 0 38.664 0.084 ;
    END
  END t_ready[16]
  PIN t_ready[17]
    DIRECTION INPUT ;
    USE SIGNAL ;
    PORT
      LAYER M5 ;
        RECT  38.736 0 38.76 0.084 ;
    END
  END t_ready[17]
  PIN t_ready[18]
    DIRECTION INPUT ;
    USE SIGNAL ;
    PORT
      LAYER M5 ;
        RECT  38.832 0 38.856 0.084 ;
    END
  END t_ready[18]
  PIN t_ready[1]
    DIRECTION INPUT ;
    USE SIGNAL ;
    PORT
      LAYER M5 ;
        RECT  34.128 0 34.152 0.084 ;
    END
  END t_ready[1]
  PIN t_ready[2]
    DIRECTION INPUT ;
    USE SIGNAL ;
    PORT
      LAYER M5 ;
        RECT  34.224 0 34.248 0.084 ;
    END
  END t_ready[2]
  PIN t_ready[3]
    DIRECTION INPUT ;
    USE SIGNAL ;
    PORT
      LAYER M5 ;
        RECT  34.32 0 34.344 0.084 ;
    END
  END t_ready[3]
  PIN t_ready[4]
    DIRECTION INPUT ;
    USE SIGNAL ;
    PORT
      LAYER M5 ;
        RECT  34.416 0 34.44 0.084 ;
    END
  END t_ready[4]
  PIN t_ready[5]
    DIRECTION INPUT ;
    USE SIGNAL ;
    PORT
      LAYER M5 ;
        RECT  34.512 0 34.536 0.084 ;
    END
  END t_ready[5]
  PIN t_ready[6]
    DIRECTION INPUT ;
    USE SIGNAL ;
    PORT
      LAYER M5 ;
        RECT  34.608 0 34.632 0.084 ;
    END
  END t_ready[6]
  PIN t_ready[7]
    DIRECTION INPUT ;
    USE SIGNAL ;
    PORT
      LAYER M5 ;
        RECT  34.704 0 34.728 0.084 ;
    END
  END t_ready[7]
  PIN t_ready[8]
    DIRECTION INPUT ;
    USE SIGNAL ;
    PORT
      LAYER M5 ;
        RECT  34.8 0 34.824 0.084 ;
    END
  END t_ready[8]
  PIN t_ready[9]
    DIRECTION INPUT ;
    USE SIGNAL ;
    PORT
      LAYER M5 ;
        RECT  34.896 0 34.92 0.084 ;
    END
  END t_ready[9]
  PIN VDD
    DIRECTION INOUT ;
    USE POWER ;
    PORT
      LAYER M5 ;
        RECT  61.992 2.151 62.112 66.969 ;
        RECT  56.592 2.151 56.712 66.969 ;
        RECT  51.192 2.151 51.312 66.969 ;
        RECT  45.792 2.151 45.912 66.969 ;
        RECT  40.392 2.151 40.512 66.969 ;
        RECT  34.992 2.151 35.112 66.969 ;
        RECT  29.592 2.151 29.712 66.969 ;
        RECT  24.192 2.151 24.312 66.969 ;
        RECT  18.792 2.151 18.912 66.969 ;
        RECT  13.392 2.151 13.512 66.969 ;
        RECT  7.992 2.151 8.112 66.969 ;
        RECT  2.592 2.151 2.712 66.969 ;
    END
  END VDD
  PIN VSS
    DIRECTION INOUT ;
    USE GROUND ;
    PORT
      LAYER M5 ;
        RECT  61.8 2.137 61.92 66.983 ;
        RECT  56.4 2.137 56.52 66.983 ;
        RECT  51 2.137 51.12 66.983 ;
        RECT  45.6 2.137 45.72 66.983 ;
        RECT  40.2 2.137 40.32 66.983 ;
        RECT  34.8 2.137 34.92 66.983 ;
        RECT  29.4 2.137 29.52 66.983 ;
        RECT  24 2.137 24.12 66.983 ;
        RECT  18.6 2.137 18.72 66.983 ;
        RECT  13.2 2.137 13.32 66.983 ;
        RECT  7.8 2.137 7.92 66.983 ;
        RECT  2.4 2.137 2.52 66.983 ;
    END
  END VSS
  OBS
    LAYER RVTN ;
     RECT  2.16 2.16 66.96 2.295 ;
     RECT  2.16 2.565 66.96 2.835 ;
     RECT  2.16 3.105 66.96 3.375 ;
     RECT  2.16 3.645 66.96 3.915 ;
     RECT  2.16 4.185 66.96 4.455 ;
     RECT  2.16 4.725 66.96 4.995 ;
     RECT  2.16 5.265 66.96 5.535 ;
     RECT  2.16 5.805 66.96 6.075 ;
     RECT  2.16 6.345 66.96 6.615 ;
     RECT  2.16 6.885 66.96 7.155 ;
     RECT  2.16 7.425 66.96 7.695 ;
     RECT  2.16 7.965 66.96 8.235 ;
     RECT  2.16 8.505 66.96 8.775 ;
     RECT  2.16 9.045 66.96 9.315 ;
     RECT  2.16 9.585 66.96 9.855 ;
     RECT  2.16 10.125 66.96 10.395 ;
     RECT  2.16 10.665 66.96 10.935 ;
     RECT  2.16 11.205 66.96 11.475 ;
     RECT  2.16 11.745 66.96 12.015 ;
     RECT  2.16 12.285 66.96 12.555 ;
     RECT  2.16 12.825 66.96 13.095 ;
     RECT  2.16 13.365 66.96 13.635 ;
     RECT  2.16 13.905 66.96 14.175 ;
     RECT  2.16 14.445 66.96 14.715 ;
     RECT  2.16 14.985 66.96 15.255 ;
     RECT  2.16 15.525 66.96 15.795 ;
     RECT  2.16 16.065 66.96 16.335 ;
     RECT  2.16 16.605 66.96 16.875 ;
     RECT  2.16 17.145 66.96 17.415 ;
     RECT  2.16 17.685 66.96 17.955 ;
     RECT  2.16 18.225 66.96 18.495 ;
     RECT  2.16 18.765 66.96 19.035 ;
     RECT  2.16 19.305 66.96 19.575 ;
     RECT  2.16 19.845 66.96 20.115 ;
     RECT  2.16 20.385 66.96 20.655 ;
     RECT  2.16 20.925 66.96 21.195 ;
     RECT  2.16 21.465 66.96 21.735 ;
     RECT  2.16 22.005 66.96 22.275 ;
     RECT  2.16 22.545 66.96 22.815 ;
     RECT  2.16 23.085 66.96 23.355 ;
     RECT  2.16 23.625 66.96 23.895 ;
     RECT  2.16 24.165 66.96 24.435 ;
     RECT  2.16 24.705 66.96 24.975 ;
     RECT  2.16 25.245 66.96 25.515 ;
     RECT  2.16 25.785 66.96 26.055 ;
     RECT  2.16 26.325 66.96 26.595 ;
     RECT  2.16 26.865 66.96 27.135 ;
     RECT  2.16 27.405 66.96 27.675 ;
     RECT  2.16 27.945 66.96 28.215 ;
     RECT  2.16 28.485 66.96 28.755 ;
     RECT  2.16 29.025 66.96 29.295 ;
     RECT  2.16 29.565 66.96 29.835 ;
     RECT  2.16 30.105 66.96 30.375 ;
     RECT  2.16 30.645 66.96 30.915 ;
     RECT  2.16 31.185 66.96 31.455 ;
     RECT  2.16 31.725 66.96 31.995 ;
     RECT  2.16 32.265 66.96 32.535 ;
     RECT  2.16 32.805 66.96 33.075 ;
     RECT  2.16 33.345 66.96 33.615 ;
     RECT  2.16 33.885 66.96 34.155 ;
     RECT  2.16 34.425 66.96 34.695 ;
     RECT  2.16 34.965 66.96 35.235 ;
     RECT  2.16 35.505 66.96 35.775 ;
     RECT  2.16 36.045 66.96 36.315 ;
     RECT  2.16 36.585 66.96 36.855 ;
     RECT  2.16 37.125 66.96 37.395 ;
     RECT  2.16 37.665 66.96 37.935 ;
     RECT  2.16 38.205 66.96 38.475 ;
     RECT  2.16 38.745 66.96 39.015 ;
     RECT  2.16 39.285 66.96 39.555 ;
     RECT  2.16 39.825 66.96 40.095 ;
     RECT  2.16 40.365 66.96 40.635 ;
     RECT  2.16 40.905 66.96 41.175 ;
     RECT  2.16 41.445 66.96 41.715 ;
     RECT  2.16 41.985 66.96 42.255 ;
     RECT  2.16 42.525 66.96 42.795 ;
     RECT  2.16 43.065 66.96 43.335 ;
     RECT  2.16 43.605 66.96 43.875 ;
     RECT  2.16 44.145 66.96 44.415 ;
     RECT  2.16 44.685 66.96 44.955 ;
     RECT  2.16 45.225 66.96 45.495 ;
     RECT  2.16 45.765 66.96 46.035 ;
     RECT  2.16 46.305 66.96 46.575 ;
     RECT  2.16 46.845 66.96 47.115 ;
     RECT  2.16 47.385 66.96 47.655 ;
     RECT  2.16 47.925 66.96 48.195 ;
     RECT  2.16 48.465 66.96 48.735 ;
     RECT  2.16 49.005 66.96 49.275 ;
     RECT  2.16 49.545 66.96 49.815 ;
     RECT  2.16 50.085 66.96 50.355 ;
     RECT  2.16 50.625 66.96 50.895 ;
     RECT  2.16 51.165 66.96 51.435 ;
     RECT  2.16 51.705 66.96 51.975 ;
     RECT  2.16 52.245 66.96 52.515 ;
     RECT  2.16 52.785 66.96 53.055 ;
     RECT  2.16 53.325 66.96 53.595 ;
     RECT  2.16 53.865 66.96 54.135 ;
     RECT  2.16 54.405 66.96 54.675 ;
     RECT  2.16 54.945 66.96 55.215 ;
     RECT  2.16 55.485 66.96 55.755 ;
     RECT  2.16 56.025 66.96 56.295 ;
     RECT  2.16 56.565 66.96 56.835 ;
     RECT  2.16 57.105 66.96 57.375 ;
     RECT  2.16 57.645 66.96 57.915 ;
     RECT  2.16 58.185 66.96 58.455 ;
     RECT  2.16 58.725 66.96 58.995 ;
     RECT  2.16 59.265 66.96 59.535 ;
     RECT  2.16 59.805 66.96 60.075 ;
     RECT  2.16 60.345 66.96 60.615 ;
     RECT  2.16 60.885 66.96 61.155 ;
     RECT  2.16 61.425 66.96 61.695 ;
     RECT  2.16 61.965 66.96 62.235 ;
     RECT  2.16 62.505 66.96 62.775 ;
     RECT  2.16 63.045 66.96 63.315 ;
     RECT  2.16 63.585 66.96 63.855 ;
     RECT  2.16 64.125 66.96 64.395 ;
     RECT  2.16 64.665 66.96 64.935 ;
     RECT  2.16 65.205 66.96 65.475 ;
     RECT  2.16 65.745 66.96 66.015 ;
     RECT  2.16 66.285 66.96 66.555 ;
     RECT  2.16 66.825 66.96 66.96 ;
    LAYER RVTP ;
     RECT  2.16 2.295 66.96 2.565 ;
     RECT  2.16 2.835 66.96 3.105 ;
     RECT  2.16 3.375 66.96 3.645 ;
     RECT  2.16 3.915 66.96 4.185 ;
     RECT  2.16 4.455 66.96 4.725 ;
     RECT  2.16 4.995 66.96 5.265 ;
     RECT  2.16 5.535 66.96 5.805 ;
     RECT  2.16 6.075 66.96 6.345 ;
     RECT  2.16 6.615 66.96 6.885 ;
     RECT  2.16 7.155 66.96 7.425 ;
     RECT  2.16 7.695 66.96 7.965 ;
     RECT  2.16 8.235 66.96 8.505 ;
     RECT  2.16 8.775 66.96 9.045 ;
     RECT  2.16 9.315 66.96 9.585 ;
     RECT  2.16 9.855 66.96 10.125 ;
     RECT  2.16 10.395 66.96 10.665 ;
     RECT  2.16 10.935 66.96 11.205 ;
     RECT  2.16 11.475 66.96 11.745 ;
     RECT  2.16 12.015 66.96 12.285 ;
     RECT  2.16 12.555 66.96 12.825 ;
     RECT  2.16 13.095 66.96 13.365 ;
     RECT  2.16 13.635 66.96 13.905 ;
     RECT  2.16 14.175 66.96 14.445 ;
     RECT  2.16 14.715 66.96 14.985 ;
     RECT  2.16 15.255 66.96 15.525 ;
     RECT  2.16 15.795 66.96 16.065 ;
     RECT  2.16 16.335 66.96 16.605 ;
     RECT  2.16 16.875 66.96 17.145 ;
     RECT  2.16 17.415 66.96 17.685 ;
     RECT  2.16 17.955 66.96 18.225 ;
     RECT  2.16 18.495 66.96 18.765 ;
     RECT  2.16 19.035 66.96 19.305 ;
     RECT  2.16 19.575 66.96 19.845 ;
     RECT  2.16 20.115 66.96 20.385 ;
     RECT  2.16 20.655 66.96 20.925 ;
     RECT  2.16 21.195 66.96 21.465 ;
     RECT  2.16 21.735 66.96 22.005 ;
     RECT  2.16 22.275 66.96 22.545 ;
     RECT  2.16 22.815 66.96 23.085 ;
     RECT  2.16 23.355 66.96 23.625 ;
     RECT  2.16 23.895 66.96 24.165 ;
     RECT  2.16 24.435 66.96 24.705 ;
     RECT  2.16 24.975 66.96 25.245 ;
     RECT  2.16 25.515 66.96 25.785 ;
     RECT  2.16 26.055 66.96 26.325 ;
     RECT  2.16 26.595 66.96 26.865 ;
     RECT  2.16 27.135 66.96 27.405 ;
     RECT  2.16 27.675 66.96 27.945 ;
     RECT  2.16 28.215 66.96 28.485 ;
     RECT  2.16 28.755 66.96 29.025 ;
     RECT  2.16 29.295 66.96 29.565 ;
     RECT  2.16 29.835 66.96 30.105 ;
     RECT  2.16 30.375 66.96 30.645 ;
     RECT  2.16 30.915 66.96 31.185 ;
     RECT  2.16 31.455 66.96 31.725 ;
     RECT  2.16 31.995 66.96 32.265 ;
     RECT  2.16 32.535 66.96 32.805 ;
     RECT  2.16 33.075 66.96 33.345 ;
     RECT  2.16 33.615 66.96 33.885 ;
     RECT  2.16 34.155 66.96 34.425 ;
     RECT  2.16 34.695 66.96 34.965 ;
     RECT  2.16 35.235 66.96 35.505 ;
     RECT  2.16 35.775 66.96 36.045 ;
     RECT  2.16 36.315 66.96 36.585 ;
     RECT  2.16 36.855 66.96 37.125 ;
     RECT  2.16 37.395 66.96 37.665 ;
     RECT  2.16 37.935 66.96 38.205 ;
     RECT  2.16 38.475 66.96 38.745 ;
     RECT  2.16 39.015 66.96 39.285 ;
     RECT  2.16 39.555 66.96 39.825 ;
     RECT  2.16 40.095 66.96 40.365 ;
     RECT  2.16 40.635 66.96 40.905 ;
     RECT  2.16 41.175 66.96 41.445 ;
     RECT  2.16 41.715 66.96 41.985 ;
     RECT  2.16 42.255 66.96 42.525 ;
     RECT  2.16 42.795 66.96 43.065 ;
     RECT  2.16 43.335 66.96 43.605 ;
     RECT  2.16 43.875 66.96 44.145 ;
     RECT  2.16 44.415 66.96 44.685 ;
     RECT  2.16 44.955 66.96 45.225 ;
     RECT  2.16 45.495 66.96 45.765 ;
     RECT  2.16 46.035 66.96 46.305 ;
     RECT  2.16 46.575 66.96 46.845 ;
     RECT  2.16 47.115 66.96 47.385 ;
     RECT  2.16 47.655 66.96 47.925 ;
     RECT  2.16 48.195 66.96 48.465 ;
     RECT  2.16 48.735 66.96 49.005 ;
     RECT  2.16 49.275 66.96 49.545 ;
     RECT  2.16 49.815 66.96 50.085 ;
     RECT  2.16 50.355 66.96 50.625 ;
     RECT  2.16 50.895 66.96 51.165 ;
     RECT  2.16 51.435 66.96 51.705 ;
     RECT  2.16 51.975 66.96 52.245 ;
     RECT  2.16 52.515 66.96 52.785 ;
     RECT  2.16 53.055 66.96 53.325 ;
     RECT  2.16 53.595 66.96 53.865 ;
     RECT  2.16 54.135 66.96 54.405 ;
     RECT  2.16 54.675 66.96 54.945 ;
     RECT  2.16 55.215 66.96 55.485 ;
     RECT  2.16 55.755 66.96 56.025 ;
     RECT  2.16 56.295 66.96 56.565 ;
     RECT  2.16 56.835 66.96 57.105 ;
     RECT  2.16 57.375 66.96 57.645 ;
     RECT  2.16 57.915 66.96 58.185 ;
     RECT  2.16 58.455 66.96 58.725 ;
     RECT  2.16 58.995 66.96 59.265 ;
     RECT  2.16 59.535 66.96 59.805 ;
     RECT  2.16 60.075 66.96 60.345 ;
     RECT  2.16 60.615 66.96 60.885 ;
     RECT  2.16 61.155 66.96 61.425 ;
     RECT  2.16 61.695 66.96 61.965 ;
     RECT  2.16 62.235 66.96 62.505 ;
     RECT  2.16 62.775 66.96 63.045 ;
     RECT  2.16 63.315 66.96 63.585 ;
     RECT  2.16 63.855 66.96 64.125 ;
     RECT  2.16 64.395 66.96 64.665 ;
     RECT  2.16 64.935 66.96 65.205 ;
     RECT  2.16 65.475 66.96 65.745 ;
     RECT  2.16 66.015 66.96 66.285 ;
     RECT  2.16 66.555 66.96 66.825 ;
    LAYER M1 ;
     RECT  2.16 2.151 66.96 66.969 ;
    LAYER M2 ;
     RECT  0.103 24.714 0.175 24.732 ;
     RECT  0.103 48.438 0.175 48.456 ;
     RECT  0.103 18.396 0.203 18.414 ;
     RECT  0.103 19.62 0.203 19.638 ;
     RECT  0.103 21.132 0.203 21.879 ;
     RECT  0.103 22.941 0.203 22.959 ;
     RECT  0.175 24.138 0.203 24.732 ;
     RECT  0.103 25.641 0.203 25.929 ;
     RECT  0.103 27.072 0.203 27.09 ;
     RECT  0.103 34.236 0.203 34.92 ;
     RECT  0.103 40.644 0.203 41.238 ;
     RECT  0.103 46.746 0.203 46.764 ;
     RECT  0.175 48.438 0.203 49.104 ;
     RECT  0.203 21.816 0.239 21.879 ;
     RECT  0.203 34.596 0.239 34.92 ;
     RECT  0.139 39.096 0.239 39.114 ;
     RECT  0.203 24.138 0.275 24.354 ;
     RECT  0.203 49.086 0.311 49.104 ;
     RECT  0.239 21.861 0.347 21.879 ;
     RECT  0.203 40.644 0.347 40.662 ;
     RECT  0.211 45.234 0.347 45.252 ;
     RECT  0.499 28.026 0.535 28.044 ;
     RECT  0.103 30.726 0.535 30.744 ;
     RECT  0.103 42.966 0.535 43.209 ;
     RECT  0.535 46.926 0.635 47.484 ;
     RECT  0.535 17.658 2.16 17.676 ;
     RECT  0.535 18.576 2.16 18.594 ;
     RECT  0.535 22.176 2.16 22.194 ;
     RECT  0.275 24.336 2.16 24.354 ;
     RECT  0.535 27.846 2.16 28.044 ;
     RECT  0.535 30.546 2.16 30.744 ;
     RECT  0.103 31.896 2.16 31.914 ;
     RECT  0.239 34.596 2.16 34.614 ;
     RECT  0.535 36.216 2.16 36.234 ;
     RECT  0.535 37.566 2.16 37.584 ;
     RECT  0.535 42.156 2.16 42.174 ;
     RECT  0.535 42.966 2.16 43.326 ;
     RECT  0.635 46.926 2.16 46.944 ;
     RECT  1.183 48.978 2.16 48.996 ;
     RECT  2.16 2.151 18.823 66.969 ;
     RECT  18.823 2.151 19.391 67.014 ;
     RECT  19.391 2.151 28.039 66.969 ;
     RECT  28.039 2.034 31.819 66.969 ;
     RECT  31.819 1.962 33.683 66.969 ;
     RECT  33.683 2.151 34.627 66.969 ;
     RECT  34.627 2.034 36.923 66.969 ;
     RECT  36.923 2.151 39.379 66.969 ;
     RECT  39.379 2.106 39.839 66.969 ;
     RECT  39.839 2.151 40.603 66.969 ;
     RECT  40.603 2.106 40.927 66.969 ;
     RECT  40.927 1.998 42.007 66.969 ;
     RECT  42.007 1.881 42.763 66.969 ;
     RECT  42.763 1.836 44.231 66.969 ;
     RECT  44.231 1.881 44.915 66.969 ;
     RECT  44.915 1.926 45.239 66.969 ;
     RECT  45.239 1.998 45.599 66.969 ;
     RECT  45.599 2.106 45.959 66.969 ;
     RECT  45.959 2.151 49.171 66.969 ;
     RECT  49.171 2.151 50.459 67.014 ;
     RECT  50.459 2.151 66.96 66.969 ;
     RECT  66.96 19.89 67.307 51.534 ;
     RECT  67.307 19.89 67.811 38.304 ;
     RECT  67.811 19.89 67.847 23.346 ;
     RECT  67.811 28.764 67.847 34.992 ;
     RECT  67.307 39.096 67.847 51.534 ;
     RECT  67.847 28.764 67.883 32.094 ;
     RECT  67.847 39.186 67.883 42.588 ;
     RECT  67.847 43.416 67.919 51.534 ;
     RECT  67.847 19.89 68.387 23.274 ;
     RECT  67.811 24.138 68.387 28.008 ;
     RECT  67.883 28.764 68.387 31.869 ;
     RECT  67.811 35.946 68.387 38.304 ;
     RECT  67.883 39.186 68.387 39.204 ;
     RECT  67.919 43.416 68.387 46.062 ;
     RECT  68.387 19.89 68.423 19.908 ;
     RECT  68.387 20.664 68.423 21.834 ;
     RECT  68.387 23.094 68.423 23.274 ;
     RECT  68.387 24.138 68.423 27.234 ;
     RECT  68.387 29.07 68.423 29.754 ;
     RECT  67.847 34.2 68.423 34.992 ;
     RECT  68.387 35.982 68.423 36.81 ;
     RECT  68.387 37.674 68.423 38.304 ;
     RECT  67.883 40.104 68.423 42.588 ;
     RECT  67.919 46.89 68.423 51.534 ;
     RECT  68.423 21.546 68.459 21.834 ;
     RECT  68.423 26.136 68.459 26.244 ;
     RECT  68.423 27.036 68.459 27.162 ;
     RECT  68.423 35.982 68.459 36.684 ;
     RECT  68.423 46.89 68.459 47.178 ;
     RECT  68.423 50.67 68.459 51.534 ;
     RECT  68.459 21.744 68.495 21.834 ;
     RECT  68.387 30.888 68.963 31.869 ;
     RECT  68.459 47.016 68.963 47.178 ;
     RECT  68.423 24.246 68.999 24.462 ;
     RECT  68.423 25.218 68.999 25.308 ;
     RECT  68.423 34.362 68.999 34.452 ;
     RECT  68.459 35.982 68.999 36.504 ;
     RECT  68.963 47.016 68.999 47.106 ;
     RECT  68.423 48.906 68.999 49.734 ;
     RECT  68.423 20.664 69.035 20.682 ;
     RECT  68.495 21.816 69.035 21.834 ;
     RECT  68.423 23.094 69.035 23.112 ;
     RECT  68.999 24.246 69.035 24.264 ;
     RECT  68.999 25.218 69.035 25.236 ;
     RECT  68.459 26.136 69.035 26.154 ;
     RECT  68.459 27.144 69.035 27.162 ;
     RECT  68.423 29.736 69.035 29.754 ;
     RECT  68.963 30.888 69.035 31.14 ;
     RECT  67.847 32.85 69.035 33.372 ;
     RECT  68.999 34.434 69.035 34.452 ;
     RECT  68.999 36.018 69.035 36.036 ;
     RECT  68.423 38.178 69.035 38.304 ;
     RECT  68.423 40.104 69.035 40.122 ;
     RECT  68.423 42.03 69.035 42.048 ;
     RECT  68.387 43.812 69.035 45.594 ;
     RECT  68.999 47.016 69.035 47.034 ;
     RECT  68.999 49.59 69.035 49.734 ;
     RECT  68.459 50.67 69.035 50.688 ;
     RECT  68.459 51.516 69.035 51.534 ;
    LAYER M3 ;
     RECT  43.812 0.091 43.83 0.139 ;
     RECT  32.976 0.043 32.994 0.173 ;
     RECT  37.224 0.043 37.242 0.173 ;
     RECT  38.16 0.091 38.178 0.187 ;
     RECT  43.812 0.139 43.902 0.187 ;
     RECT  38.16 0.187 38.214 0.283 ;
     RECT  37.872 0.283 38.214 0.413 ;
     RECT  30.204 0.091 30.222 0.523 ;
     RECT  30.96 0.091 31.374 0.523 ;
     RECT  28.44 0.043 28.458 0.811 ;
     RECT  28.44 0.811 28.998 1.051 ;
     RECT  29.772 0.523 31.374 1.051 ;
     RECT  28.44 1.051 31.374 1.147 ;
     RECT  35.604 0.091 35.622 1.723 ;
     RECT  42.768 0.571 42.786 1.723 ;
     RECT  43.812 0.187 44.37 1.723 ;
     RECT  42.768 1.723 44.37 1.771 ;
     RECT  41.868 0.331 41.886 1.876 ;
     RECT  42.768 1.771 44.73 1.876 ;
     RECT  41.868 1.876 42.03 1.921 ;
     RECT  42.768 1.876 44.91 1.921 ;
     RECT  28.44 1.147 31.41 1.957 ;
     RECT  33.444 1.723 33.462 1.957 ;
     RECT  41.868 1.921 45.234 1.993 ;
     RECT  45.972 0.043 45.99 1.993 ;
     RECT  40.932 1.993 40.95 2.011 ;
     RECT  28.44 1.957 31.842 2.029 ;
     RECT  33.444 1.957 33.678 2.029 ;
     RECT  35.136 1.723 35.622 2.029 ;
     RECT  36.648 1.675 36.666 2.029 ;
     RECT  33.264 2.029 33.678 2.101 ;
     RECT  34.632 2.029 35.622 2.101 ;
     RECT  40.356 2.011 40.95 2.101 ;
     RECT  32.688 2.101 33.678 2.191 ;
     RECT  34.632 2.101 35.802 2.191 ;
     RECT  36.648 2.029 36.918 2.191 ;
     RECT  39.384 2.101 40.95 2.191 ;
     RECT  37.944 2.191 38.214 2.203 ;
     RECT  28.044 2.029 31.842 2.251 ;
     RECT  32.688 2.191 35.802 2.251 ;
     RECT  37.692 2.203 38.214 2.251 ;
     RECT  28.044 2.251 35.802 2.293 ;
     RECT  36.612 2.191 36.918 2.293 ;
     RECT  28.044 2.293 36.918 2.299 ;
     RECT  37.692 2.251 38.25 2.299 ;
     RECT  39.384 2.191 41.058 2.299 ;
     RECT  41.868 1.993 45.99 2.299 ;
     RECT  2.415 2.143 2.505 2.413 ;
     RECT  7.815 2.143 7.905 2.413 ;
     RECT  13.215 2.143 13.305 2.413 ;
     RECT  18.615 2.143 18.705 2.413 ;
     RECT  24.015 2.143 24.105 2.413 ;
     RECT  51.015 2.143 51.105 2.413 ;
     RECT  56.415 2.143 56.505 2.413 ;
     RECT  61.815 2.143 61.905 2.413 ;
     RECT  27.972 2.299 46.422 2.795 ;
     RECT  28.62 2.795 45.99 3.029 ;
     RECT  28.62 3.029 45.897 3.577 ;
     RECT  28.332 3.577 45.897 3.629 ;
     RECT  28.692 3.629 45.897 3.839 ;
     RECT  28.764 3.839 45.897 4.919 ;
     RECT  29.196 4.919 45.897 5.063 ;
     RECT  28.404 5.071 28.422 5.117 ;
     RECT  29.304 5.063 45.897 5.789 ;
     RECT  29.415 5.789 45.897 5.801 ;
     RECT  44.964 5.801 45.897 6.091 ;
     RECT  29.415 5.801 43.866 6.125 ;
     RECT  44.964 6.091 46.17 6.269 ;
     RECT  56.415 2.413 56.697 6.511 ;
     RECT  45.615 6.269 46.17 6.557 ;
     RECT  56.304 6.511 56.697 6.557 ;
     RECT  29.415 6.125 43.794 6.647 ;
     RECT  29.415 6.647 43.254 7.349 ;
     RECT  29.415 7.349 30.726 7.357 ;
     RECT  29.196 7.357 30.726 7.421 ;
     RECT  31.5 7.349 43.254 7.619 ;
     RECT  29.34 7.421 30.726 7.655 ;
     RECT  31.5 7.619 42.75 7.727 ;
     RECT  42.732 7.727 42.75 7.763 ;
     RECT  30.6 7.655 30.726 7.889 ;
     RECT  31.5 7.727 41.994 7.889 ;
     RECT  30.6 7.889 30.618 7.925 ;
     RECT  31.5 7.889 40.497 7.925 ;
     RECT  32.112 7.925 40.497 7.961 ;
     RECT  32.364 7.961 40.497 8.159 ;
     RECT  32.364 8.159 32.382 8.195 ;
     RECT  33.408 8.159 40.497 8.303 ;
     RECT  33.84 8.303 40.497 8.465 ;
     RECT  34.056 8.465 35.37 8.501 ;
     RECT  41.436 7.889 41.454 8.537 ;
     RECT  34.815 8.501 35.37 8.699 ;
     RECT  36.108 8.465 40.497 8.735 ;
     RECT  36.108 8.735 38.142 8.843 ;
     RECT  39.744 8.735 40.497 8.879 ;
     RECT  36.756 8.843 38.142 8.969 ;
     RECT  38.916 8.735 38.934 8.969 ;
     RECT  37.584 8.969 37.602 9.041 ;
     RECT  34.056 8.501 34.074 9.815 ;
     RECT  28.296 9.859 28.314 9.931 ;
     RECT  29.34 7.655 29.754 9.931 ;
     RECT  27.504 9.931 29.754 10.049 ;
     RECT  28.152 10.049 29.754 10.085 ;
     RECT  27.36 10.057 27.378 10.109 ;
     RECT  28.296 10.085 29.754 10.595 ;
     RECT  28.656 10.595 29.754 10.831 ;
     RECT  28.656 10.831 30.114 11.129 ;
     RECT  28.656 11.129 28.674 11.165 ;
     RECT  29.415 11.129 30.114 11.281 ;
     RECT  29.415 11.281 30.402 11.749 ;
     RECT  29.415 11.749 30.69 12.245 ;
     RECT  24.015 2.413 24.297 12.991 ;
     RECT  13.215 2.413 13.497 13.003 ;
     RECT  23.904 12.991 24.297 13.037 ;
     RECT  13.215 13.003 13.554 13.051 ;
     RECT  12.924 13.051 13.554 13.091 ;
     RECT  12.96 13.091 13.554 13.199 ;
     RECT  12.96 13.199 13.497 13.517 ;
     RECT  4.68 17.113 4.698 17.149 ;
     RECT  6.876 17.113 6.894 17.149 ;
     RECT  6.768 17.149 6.894 17.221 ;
     RECT  6.48 17.221 6.894 17.419 ;
     RECT  7.815 2.413 8.097 17.419 ;
     RECT  22.032 17.347 22.05 17.455 ;
     RECT  4.356 17.149 4.698 17.491 ;
     RECT  23.076 17.311 23.094 17.491 ;
     RECT  24.015 13.037 24.297 17.491 ;
     RECT  3.852 17.491 5.706 17.581 ;
     RECT  6.48 17.419 8.097 17.581 ;
     RECT  0.54 17.653 0.558 17.741 ;
     RECT  2.415 2.413 2.697 17.761 ;
     RECT  3.852 17.581 8.097 17.879 ;
     RECT  6.012 17.879 8.097 17.887 ;
     RECT  21.996 17.455 22.05 17.923 ;
     RECT  23.076 17.491 24.297 17.923 ;
     RECT  3.852 17.879 5.166 18.031 ;
     RECT  9.36 18.031 9.378 18.149 ;
     RECT  3.636 18.031 5.166 18.221 ;
     RECT  6.012 17.887 8.442 18.229 ;
     RECT  2.304 17.761 2.697 18.391 ;
     RECT  0.108 18.379 0.198 18.419 ;
     RECT  6.012 18.229 8.658 18.491 ;
     RECT  0.18 18.419 0.198 18.571 ;
     RECT  4.356 18.221 5.166 18.661 ;
     RECT  6.012 18.491 8.586 18.661 ;
     RECT  2.304 18.391 3.582 18.689 ;
     RECT  9.396 18.571 9.414 18.689 ;
     RECT  4.356 18.661 8.586 18.869 ;
     RECT  5.4 18.869 8.586 18.959 ;
     RECT  0.18 18.571 0.558 18.989 ;
     RECT  10.8 17.851 10.818 19.003 ;
     RECT  4.356 18.869 4.662 19.111 ;
     RECT  10.8 19.003 10.854 19.111 ;
     RECT  0.18 18.989 0.198 19.147 ;
     RECT  10.656 19.111 10.926 19.229 ;
     RECT  10.728 19.229 10.854 19.301 ;
     RECT  21.996 17.923 24.297 19.309 ;
     RECT  45.615 6.557 45.897 19.387 ;
     RECT  9.324 18.967 9.342 19.543 ;
     RECT  21.996 19.309 24.462 19.543 ;
     RECT  0.144 19.147 0.198 19.612 ;
     RECT  2.304 18.689 3.114 19.627 ;
     RECT  3.996 19.111 4.662 19.651 ;
     RECT  5.4 18.959 8.478 19.651 ;
     RECT  0.108 19.612 0.198 19.757 ;
     RECT  0.144 19.757 0.198 19.805 ;
     RECT  9.324 19.543 9.414 19.805 ;
     RECT  18.615 2.413 18.897 19.849 ;
     RECT  68.4 19.885 68.418 19.915 ;
     RECT  3.996 19.651 8.478 19.921 ;
     RECT  9.216 19.813 9.306 19.921 ;
     RECT  45.615 19.387 45.99 19.921 ;
     RECT  67.788 19.915 68.418 19.921 ;
     RECT  3.996 19.921 9.306 19.949 ;
     RECT  2.304 19.627 3.15 20.011 ;
     RECT  3.996 19.949 9.198 20.011 ;
     RECT  64.44 19.921 64.53 20.011 ;
     RECT  21.996 19.543 24.786 20.047 ;
     RECT  26.1 19.849 26.118 20.047 ;
     RECT  63 19.921 63.018 20.047 ;
     RECT  2.304 20.011 9.198 20.048 ;
     RECT  20.664 20.047 20.682 20.083 ;
     RECT  14.76 19.963 14.85 20.093 ;
     RECT  10.836 19.301 10.854 20.111 ;
     RECT  20.664 20.083 20.754 20.147 ;
     RECT  61.815 2.413 62.097 20.155 ;
     RECT  3.852 20.048 9.198 20.189 ;
     RECT  14.832 20.093 14.85 20.189 ;
     RECT  18.615 19.849 19.602 20.189 ;
     RECT  45.615 19.921 46.206 20.191 ;
     RECT  61.38 20.155 62.097 20.191 ;
     RECT  63 20.047 63.594 20.191 ;
     RECT  64.44 20.011 64.566 20.191 ;
     RECT  65.484 19.777 65.502 20.191 ;
     RECT  18.615 20.189 18.954 20.219 ;
     RECT  20.736 20.147 20.754 20.219 ;
     RECT  45.615 20.191 46.746 20.219 ;
     RECT  46.656 20.219 46.746 20.237 ;
     RECT  67.284 19.921 68.418 20.237 ;
     RECT  42.768 20.191 42.786 20.309 ;
     RECT  46.728 20.237 46.746 20.309 ;
     RECT  61.38 20.191 63.594 20.309 ;
     RECT  68.328 20.237 68.418 20.345 ;
     RECT  66.24 20.083 66.258 20.389 ;
     RECT  67.284 20.237 67.302 20.389 ;
     RECT  2.304 20.048 2.862 20.491 ;
     RECT  61.38 20.309 63.558 20.581 ;
     RECT  59.76 20.155 59.778 20.584 ;
     RECT  68.364 20.345 68.418 20.587 ;
     RECT  59.76 20.584 59.886 20.615 ;
     RECT  64.44 20.191 65.502 20.623 ;
     RECT  66.24 20.389 67.302 20.623 ;
     RECT  68.364 20.587 69.03 20.687 ;
     RECT  59.868 20.615 59.886 20.731 ;
     RECT  2.268 20.491 2.862 20.759 ;
     RECT  64.44 20.623 67.302 20.821 ;
     RECT  58.716 20.191 58.734 20.849 ;
     RECT  64.368 20.821 67.302 20.861 ;
     RECT  5.364 20.189 9.198 20.875 ;
     RECT  2.304 20.759 2.862 20.929 ;
     RECT  3.852 20.189 4.59 20.929 ;
     RECT  64.548 20.861 67.302 20.957 ;
     RECT  41.544 20.929 41.562 20.965 ;
     RECT  5.364 20.875 9.45 20.971 ;
     RECT  5.364 20.971 9.486 21.001 ;
     RECT  21.996 20.047 26.118 21.001 ;
     RECT  5.328 21.001 9.486 21.029 ;
     RECT  56.415 6.557 56.697 21.091 ;
     RECT  59.868 20.731 60.03 21.091 ;
     RECT  60.948 20.581 63.558 21.091 ;
     RECT  64.62 20.957 67.302 21.091 ;
     RECT  5.328 21.029 9.378 21.119 ;
     RECT  0.144 19.805 0.162 21.127 ;
     RECT  21.996 21.001 26.514 21.127 ;
     RECT  27.324 21.091 27.342 21.127 ;
     RECT  56.415 21.091 57.042 21.127 ;
     RECT  59.868 21.091 60.138 21.163 ;
     RECT  60.948 21.091 63.594 21.163 ;
     RECT  64.62 21.091 67.338 21.197 ;
     RECT  56.415 21.127 57.078 21.227 ;
     RECT  68.364 20.687 68.418 21.259 ;
     RECT  2.304 20.929 4.59 21.271 ;
     RECT  5.328 21.119 9.306 21.271 ;
     RECT  41.544 20.965 42.21 21.271 ;
     RECT  10.764 21.199 10.782 21.388 ;
     RECT  30.636 12.245 30.69 21.433 ;
     RECT  10.728 21.388 10.782 21.469 ;
     RECT  41.544 21.271 42.534 21.505 ;
     RECT  68.328 21.259 68.418 21.541 ;
     RECT  10.656 21.469 10.782 21.595 ;
     RECT  59.868 21.163 63.594 21.595 ;
     RECT  0.108 21.127 0.198 21.643 ;
     RECT  10.656 21.595 10.818 21.659 ;
     RECT  21.996 21.127 27.342 21.703 ;
     RECT  68.328 21.541 68.454 21.739 ;
     RECT  2.304 21.271 9.306 21.803 ;
     RECT  68.328 21.739 69.03 21.839 ;
     RECT  0.108 21.643 0.342 21.884 ;
     RECT  21.996 21.703 27.378 22.009 ;
     RECT  64.62 21.197 67.302 22.045 ;
     RECT  2.304 21.803 8.55 22.109 ;
     RECT  0.216 21.884 0.342 22.157 ;
     RECT  68.328 21.839 68.49 22.157 ;
     RECT  0.324 22.157 0.342 22.171 ;
     RECT  59.868 21.595 63.81 22.171 ;
     RECT  59.868 22.171 63.882 22.207 ;
     RECT  64.62 22.045 67.374 22.207 ;
     RECT  68.328 22.157 68.382 22.207 ;
     RECT  59.796 22.207 68.382 22.235 ;
     RECT  59.796 22.235 62.442 22.301 ;
     RECT  0.324 22.171 0.558 22.349 ;
     RECT  21.996 22.009 27.63 22.351 ;
     RECT  28.368 21.937 28.386 22.351 ;
     RECT  56.415 21.227 57.042 22.351 ;
     RECT  10.8 21.659 10.818 22.379 ;
     RECT  63.216 22.235 68.382 22.379 ;
     RECT  64.584 22.379 68.382 22.469 ;
     RECT  59.976 22.301 62.442 22.505 ;
     RECT  0.324 22.349 0.342 22.541 ;
     RECT  56.415 22.351 57.15 22.549 ;
     RECT  4.248 22.109 8.55 22.555 ;
     RECT  9.396 22.081 9.486 22.555 ;
     RECT  41.544 21.505 43.074 22.585 ;
     RECT  56.415 22.549 57.186 22.649 ;
     RECT  44.712 22.243 44.73 22.819 ;
     RECT  41.544 22.585 43.182 22.855 ;
     RECT  44.028 22.819 44.73 22.855 ;
     RECT  4.248 22.555 9.486 22.856 ;
     RECT  64.584 22.469 67.842 22.883 ;
     RECT  4.248 22.856 9.45 23.009 ;
     RECT  0.108 22.924 0.198 23.021 ;
     RECT  0.18 23.021 0.198 23.069 ;
     RECT  2.304 22.109 3.51 23.083 ;
     RECT  4.248 23.009 9.306 23.083 ;
     RECT  69.012 22.891 69.03 23.117 ;
     RECT  61.092 22.505 62.442 23.125 ;
     RECT  63.216 22.379 63.846 23.125 ;
     RECT  38.772 22.981 38.79 23.161 ;
     RECT  61.092 23.125 63.846 23.161 ;
     RECT  64.584 22.883 65.07 23.161 ;
     RECT  65.988 22.883 67.842 23.251 ;
     RECT  59.976 22.505 60.282 23.275 ;
     RECT  65.988 23.251 68.418 23.309 ;
     RECT  38.772 23.161 38.862 23.315 ;
     RECT  10.836 23.251 10.854 23.351 ;
     RECT  2.304 23.083 9.306 23.357 ;
     RECT  41.544 22.855 44.73 23.431 ;
     RECT  61.092 23.161 65.07 23.629 ;
     RECT  2.376 23.357 9.306 23.645 ;
     RECT  56.415 22.649 57.078 23.659 ;
     RECT  41.508 23.431 44.73 23.665 ;
     RECT  45.615 20.219 45.897 23.665 ;
     RECT  29.415 12.245 29.697 23.701 ;
     RECT  59.868 23.275 60.282 23.791 ;
     RECT  38.772 23.315 38.79 23.855 ;
     RECT  61.056 23.629 65.07 23.863 ;
     RECT  2.376 23.645 9.27 23.891 ;
     RECT  41.508 23.665 45.897 23.899 ;
     RECT  10.8 23.701 10.818 23.927 ;
     RECT  65.988 23.309 67.842 23.935 ;
     RECT  29.232 23.701 29.697 23.971 ;
     RECT  30.6 21.433 30.69 23.971 ;
     RECT  59.868 23.791 60.318 23.971 ;
     RECT  61.056 23.863 65.142 23.971 ;
     RECT  65.916 23.935 67.842 23.971 ;
     RECT  0.144 23.755 0.162 24.043 ;
     RECT  59.868 23.971 67.842 24.133 ;
     RECT  69.012 24.043 69.03 24.133 ;
     RECT  2.376 23.891 8.694 24.169 ;
     RECT  21.996 22.351 28.386 24.169 ;
     RECT  29.232 23.971 30.69 24.169 ;
     RECT  59.868 24.133 69.03 24.269 ;
     RECT  0.144 24.043 0.342 24.331 ;
     RECT  59.868 24.269 68.994 24.509 ;
     RECT  56.415 23.659 57.114 24.511 ;
     RECT  59.868 24.509 66.042 24.629 ;
     RECT  0.144 24.331 0.558 24.653 ;
     RECT  0.144 24.653 0.198 24.7 ;
     RECT  21.996 24.169 30.69 24.709 ;
     RECT  56.415 24.511 57.186 24.736 ;
     RECT  65.988 24.629 66.042 24.773 ;
     RECT  2.304 24.169 8.694 24.781 ;
     RECT  59.868 24.629 65.142 24.781 ;
     RECT  59.796 24.781 65.142 24.845 ;
     RECT  2.304 24.781 8.838 24.899 ;
     RECT  10.8 24.871 10.818 24.971 ;
     RECT  56.415 24.736 57.222 24.971 ;
     RECT  67.284 24.509 68.994 25.003 ;
     RECT  59.868 24.845 65.142 25.079 ;
     RECT  60.984 25.079 65.142 25.088 ;
     RECT  5.58 24.899 8.838 25.177 ;
     RECT  67.284 25.003 69.03 25.229 ;
     RECT  5.58 25.177 9.09 25.439 ;
     RECT  9 25.439 9.09 25.511 ;
     RECT  10.836 25.447 10.854 25.619 ;
     RECT  2.304 24.899 4.698 25.723 ;
     RECT  5.58 25.439 8.226 25.723 ;
     RECT  21.996 24.709 30.798 25.789 ;
     RECT  58.716 25.321 58.734 25.789 ;
     RECT  65.988 24.773 66.006 25.825 ;
     RECT  9.36 25.681 9.378 25.889 ;
     RECT  67.788 25.229 69.03 25.889 ;
     RECT  46.656 25.825 46.674 25.978 ;
     RECT  46.62 25.978 46.674 25.979 ;
     RECT  65.808 25.825 66.402 25.979 ;
     RECT  0.108 24.7 0.198 25.997 ;
     RECT  32.184 21.631 32.202 26.023 ;
     RECT  59.868 25.079 60.21 26.023 ;
     RECT  0.144 25.997 0.198 26.045 ;
     RECT  59.724 26.023 60.21 26.059 ;
     RECT  60.984 25.088 64.926 26.059 ;
     RECT  10.656 25.789 10.746 26.087 ;
     RECT  46.62 25.979 46.638 26.087 ;
     RECT  59.724 26.059 64.926 26.141 ;
     RECT  68.292 25.889 69.03 26.159 ;
     RECT  21.996 25.789 30.87 26.221 ;
     RECT  31.608 26.023 32.202 26.221 ;
     RECT  21.996 26.221 32.202 26.257 ;
     RECT  67.248 26.155 67.302 26.356 ;
     RECT  10.728 26.087 10.746 26.365 ;
     RECT  21.996 26.257 32.526 26.401 ;
     RECT  10.728 26.365 10.818 26.555 ;
     RECT  67.212 26.356 67.302 26.563 ;
     RECT  2.304 25.723 8.226 26.635 ;
     RECT  9.108 26.401 9.126 26.635 ;
     RECT  66.672 26.563 67.302 26.635 ;
     RECT  68.292 26.159 68.454 26.635 ;
     RECT  66.672 26.635 68.454 26.663 ;
     RECT  2.304 26.635 9.126 26.671 ;
     RECT  10.728 26.555 10.746 26.699 ;
     RECT  65.808 25.979 65.934 26.731 ;
     RECT  2.304 26.671 9.378 26.789 ;
     RECT  21.996 26.401 33.066 26.797 ;
     RECT  58.716 25.789 58.806 26.797 ;
     RECT  58.716 26.797 58.842 26.869 ;
     RECT  67.284 26.663 68.454 26.923 ;
     RECT  0.144 26.045 0.162 27.052 ;
     RECT  59.976 26.141 64.926 27.067 ;
     RECT  65.808 26.731 66.51 27.067 ;
     RECT  67.284 26.923 69.03 27.167 ;
     RECT  21.996 26.797 33.498 27.175 ;
     RECT  9.18 26.789 9.378 27.205 ;
     RECT  0.108 27.052 0.198 27.245 ;
     RECT  9.18 27.205 9.45 27.245 ;
     RECT  2.304 26.789 8.442 27.329 ;
     RECT  9.18 27.245 9.378 27.329 ;
     RECT  59.976 27.067 66.51 27.329 ;
     RECT  58.716 26.869 58.914 27.485 ;
     RECT  58.716 27.485 58.806 27.509 ;
     RECT  58.716 27.509 58.77 27.599 ;
     RECT  60.984 27.329 66.186 27.599 ;
     RECT  10.764 27.571 10.782 27.707 ;
     RECT  9.18 27.329 9.27 27.751 ;
     RECT  59.976 27.329 60.246 27.841 ;
     RECT  21.996 27.175 33.606 27.877 ;
     RECT  59.832 27.841 60.246 27.877 ;
     RECT  21.996 27.877 33.894 27.949 ;
     RECT  59.76 27.877 60.246 27.965 ;
     RECT  0.54 27.841 0.558 28.021 ;
     RECT  9.144 27.751 9.27 28.139 ;
     RECT  59.832 27.965 60.246 28.139 ;
     RECT  21.996 27.949 33.93 28.147 ;
     RECT  34.815 8.699 35.097 28.147 ;
     RECT  0.504 28.021 0.558 28.205 ;
     RECT  59.976 28.139 60.246 28.219 ;
     RECT  60.984 27.599 63.666 28.219 ;
     RECT  2.304 27.329 8.37 28.291 ;
     RECT  59.976 28.219 63.666 28.363 ;
     RECT  64.404 27.599 66.078 28.363 ;
     RECT  2.304 28.291 8.946 28.445 ;
     RECT  59.976 28.363 66.078 28.453 ;
     RECT  59.976 28.453 66.402 28.493 ;
     RECT  2.304 28.445 8.097 28.651 ;
     RECT  67.284 27.167 68.454 28.685 ;
     RECT  2.268 28.651 8.097 28.688 ;
     RECT  8.856 28.445 8.946 28.751 ;
     RECT  10.8 28.687 10.818 28.859 ;
     RECT  67.788 28.685 68.454 28.877 ;
     RECT  63.324 28.493 66.15 28.949 ;
     RECT  21.996 28.147 35.097 29.065 ;
     RECT  58.716 27.599 58.734 29.065 ;
     RECT  0.504 28.205 0.522 29.165 ;
     RECT  59.976 28.493 62.55 29.227 ;
     RECT  47.808 29.227 47.826 29.263 ;
     RECT  63.324 28.949 65.574 29.327 ;
     RECT  2.304 28.688 8.097 29.335 ;
     RECT  59.904 29.227 62.55 29.335 ;
     RECT  63.324 29.327 65.322 29.335 ;
     RECT  59.904 29.335 65.322 29.365 ;
     RECT  9.144 29.101 9.234 29.399 ;
     RECT  58.716 29.065 58.842 29.399 ;
     RECT  59.832 29.365 65.322 29.405 ;
     RECT  67.788 28.877 68.418 29.461 ;
     RECT  9.144 29.399 9.162 29.561 ;
     RECT  0.144 29.419 0.162 29.597 ;
     RECT  67.284 29.461 68.418 29.611 ;
     RECT  10.764 29.101 10.782 29.641 ;
     RECT  48.708 29.569 48.726 29.641 ;
     RECT  2.304 29.335 8.154 29.731 ;
     RECT  9.036 29.641 9.054 29.731 ;
     RECT  2.304 29.731 9.054 29.759 ;
     RECT  60.048 29.405 65.322 29.759 ;
     RECT  47.736 29.263 47.826 29.767 ;
     RECT  47.736 29.767 47.97 29.803 ;
     RECT  48.708 29.641 48.834 29.803 ;
     RECT  10.728 29.641 10.782 29.911 ;
     RECT  66.348 29.839 66.366 29.911 ;
     RECT  2.304 29.759 8.802 29.939 ;
     RECT  10.728 29.911 10.818 29.939 ;
     RECT  66.348 29.911 66.546 30.029 ;
     RECT  66.348 30.029 66.366 30.065 ;
     RECT  2.415 29.939 8.802 30.173 ;
     RECT  2.415 30.173 8.298 30.179 ;
     RECT  58.716 29.399 58.77 30.271 ;
     RECT  47.736 29.803 48.834 30.343 ;
     RECT  49.968 30.307 49.986 30.343 ;
     RECT  58.716 30.271 58.842 30.343 ;
     RECT  58.716 30.343 58.914 30.379 ;
     RECT  67.284 29.611 69.03 30.413 ;
     RECT  58.716 30.379 58.986 30.479 ;
     RECT  60.048 29.759 65.286 30.479 ;
     RECT  2.415 30.179 4.914 30.713 ;
     RECT  0.54 30.541 0.558 30.721 ;
     RECT  2.415 30.713 4.59 30.749 ;
     RECT  65.7 30.649 66.15 30.749 ;
     RECT  0.108 30.721 0.558 30.797 ;
     RECT  2.415 30.749 4.446 30.839 ;
     RECT  65.772 30.749 66.15 30.859 ;
     RECT  5.796 30.179 8.298 30.955 ;
     RECT  5.472 30.955 8.766 31.081 ;
     RECT  9.936 30.685 9.954 31.081 ;
     RECT  0.144 30.797 0.558 31.085 ;
     RECT  58.716 30.479 58.842 31.109 ;
     RECT  67.752 30.413 69.03 31.145 ;
     RECT  2.415 30.839 4.374 31.147 ;
     RECT  10.8 29.939 10.818 31.189 ;
     RECT  10.728 31.189 10.818 31.289 ;
     RECT  60.048 30.479 64.854 31.339 ;
     RECT  0.54 31.085 0.558 31.373 ;
     RECT  51.015 2.413 51.297 31.387 ;
     RECT  10.728 31.289 10.782 31.459 ;
     RECT  59.76 31.339 64.854 31.495 ;
     RECT  65.772 30.859 66.69 31.531 ;
     RECT  67.752 31.145 68.958 31.531 ;
     RECT  10.692 31.459 10.782 31.559 ;
     RECT  59.688 31.495 64.854 31.621 ;
     RECT  65.772 31.531 68.958 31.621 ;
     RECT  5.472 31.081 9.954 31.649 ;
     RECT  59.688 31.621 68.958 31.649 ;
     RECT  59.76 31.649 68.958 31.685 ;
     RECT  2.304 31.147 4.374 31.693 ;
     RECT  5.472 31.649 8.37 31.693 ;
     RECT  60.012 31.685 68.958 31.709 ;
     RECT  50.94 31.387 51.297 31.729 ;
     RECT  10.728 31.559 10.782 31.757 ;
     RECT  47.736 30.343 49.986 31.891 ;
     RECT  58.716 31.109 58.806 31.919 ;
     RECT  0.108 31.891 0.126 31.949 ;
     RECT  66.132 31.709 68.958 31.949 ;
     RECT  47.736 31.891 50.022 31.999 ;
     RECT  50.868 31.729 51.297 31.999 ;
     RECT  68.94 31.949 68.958 32.045 ;
     RECT  21.996 29.065 35.154 32.071 ;
     RECT  35.928 31.189 35.946 32.071 ;
     RECT  47.736 31.999 51.297 32.197 ;
     RECT  46.764 32.197 46.782 32.341 ;
     RECT  46.764 32.341 46.854 32.369 ;
     RECT  47.736 32.197 51.354 32.369 ;
     RECT  2.304 31.693 8.37 32.395 ;
     RECT  2.268 32.395 8.37 32.459 ;
     RECT  10.908 32.341 10.926 32.459 ;
     RECT  2.304 32.459 8.37 32.467 ;
     RECT  9.18 31.649 9.954 32.467 ;
     RECT  46.836 32.369 46.854 32.495 ;
     RECT  21.996 32.071 35.946 32.503 ;
     RECT  60.012 31.709 65.322 32.575 ;
     RECT  59.868 32.575 65.322 32.611 ;
     RECT  66.132 31.949 67.878 32.611 ;
     RECT  21.996 32.503 36.162 32.737 ;
     RECT  58.788 32.701 58.806 32.801 ;
     RECT  59.868 32.611 67.878 32.872 ;
     RECT  69.012 32.779 69.03 32.872 ;
     RECT  2.304 32.467 9.954 32.909 ;
     RECT  59.868 32.872 69.03 32.971 ;
     RECT  21.996 32.737 36.342 33.007 ;
     RECT  59.832 32.971 69.03 33.008 ;
     RECT  10.8 32.971 10.818 33.071 ;
     RECT  59.832 33.008 67.842 33.071 ;
     RECT  21.996 33.007 36.738 33.115 ;
     RECT  63.252 33.071 67.842 33.179 ;
     RECT  59.832 33.071 62.406 33.259 ;
     RECT  2.304 32.909 8.694 33.269 ;
     RECT  63.252 33.179 66.474 33.269 ;
     RECT  59.688 33.259 62.406 33.305 ;
     RECT  63.288 33.269 65.322 33.305 ;
     RECT  2.304 33.269 8.37 33.349 ;
     RECT  63.288 33.305 64.89 33.449 ;
     RECT  2.268 33.349 8.37 33.485 ;
     RECT  21.996 33.115 36.918 33.547 ;
     RECT  63.288 33.449 64.746 33.719 ;
     RECT  58.752 33.691 58.77 33.781 ;
     RECT  66.312 33.269 66.474 33.809 ;
     RECT  58.716 33.781 58.77 33.817 ;
     RECT  47.736 32.369 51.297 34.051 ;
     RECT  21.996 33.547 37.494 34.087 ;
     RECT  60.228 33.305 62.406 34.087 ;
     RECT  2.34 33.485 8.37 34.115 ;
     RECT  67.284 33.179 67.842 34.195 ;
     RECT  69.012 33.008 69.03 34.195 ;
     RECT  67.284 34.195 69.03 34.219 ;
     RECT  0.144 33.739 0.162 34.231 ;
     RECT  10.8 33.853 10.818 34.231 ;
     RECT  67.248 34.219 69.03 34.231 ;
     RECT  2.34 34.115 2.697 34.315 ;
     RECT  10.728 34.231 10.818 34.321 ;
     RECT  60.228 34.087 62.478 34.349 ;
     RECT  65.556 34.195 65.574 34.349 ;
     RECT  66.6 34.231 69.03 34.385 ;
     RECT  21.996 34.087 37.998 34.393 ;
     RECT  46.8 34.357 46.818 34.393 ;
     RECT  3.528 34.115 8.37 34.429 ;
     RECT  9.144 34.159 9.162 34.429 ;
     RECT  58.716 33.817 58.914 34.429 ;
     RECT  66.672 34.385 69.03 34.457 ;
     RECT  46.764 34.393 46.89 34.465 ;
     RECT  47.628 34.051 51.297 34.465 ;
     RECT  61.02 34.349 62.478 34.465 ;
     RECT  63.288 33.719 64.602 34.465 ;
     RECT  61.02 34.465 64.602 34.501 ;
     RECT  10.728 34.321 10.89 34.529 ;
     RECT  0.108 34.231 0.198 34.591 ;
     RECT  3.528 34.429 9.162 34.619 ;
     RECT  66.672 34.457 68.418 34.637 ;
     RECT  58.716 34.429 58.95 34.655 ;
     RECT  7.668 34.619 9.09 34.691 ;
     RECT  61.02 34.501 64.746 34.691 ;
     RECT  60.228 34.349 60.246 34.771 ;
     RECT  3.528 34.619 6.858 34.861 ;
     RECT  61.2 34.691 64.746 34.861 ;
     RECT  7.668 34.691 8.766 34.889 ;
     RECT  0.108 34.591 0.558 34.925 ;
     RECT  46.764 34.465 51.297 34.997 ;
     RECT  2.304 34.315 2.697 35.005 ;
     RECT  3.42 34.861 6.858 35.005 ;
     RECT  60.048 34.771 60.246 35.032 ;
     RECT  66.672 34.637 66.69 35.069 ;
     RECT  0.144 34.925 0.558 35.117 ;
     RECT  21.996 34.393 38.574 35.167 ;
     RECT  61.2 34.861 64.926 35.167 ;
     RECT  21.888 35.167 38.574 35.203 ;
     RECT  60.012 35.032 60.246 35.203 ;
     RECT  10.764 34.529 10.818 35.231 ;
     RECT  60.012 35.203 60.462 35.267 ;
     RECT  58.716 34.655 58.806 35.339 ;
     RECT  67.788 34.637 68.418 35.371 ;
     RECT  65.916 35.311 65.934 35.429 ;
     RECT  61.2 35.167 64.998 35.473 ;
     RECT  2.304 35.005 6.858 35.509 ;
     RECT  7.668 34.889 8.478 35.509 ;
     RECT  18.615 20.219 18.897 35.509 ;
     RECT  67.212 35.371 68.418 35.537 ;
     RECT  2.304 35.509 8.478 35.563 ;
     RECT  47.376 34.997 51.297 35.581 ;
     RECT  2.268 35.563 8.478 35.609 ;
     RECT  9.936 32.909 9.954 35.671 ;
     RECT  0.144 35.117 0.162 35.693 ;
     RECT  61.2 35.473 65.718 35.699 ;
     RECT  61.2 35.699 65.358 35.735 ;
     RECT  9.36 35.671 9.954 35.743 ;
     RECT  60.444 35.267 60.462 35.803 ;
     RECT  61.2 35.735 65.25 35.803 ;
     RECT  67.248 35.537 68.418 35.851 ;
     RECT  2.304 35.609 8.478 35.941 ;
     RECT  9.324 35.743 9.954 35.941 ;
     RECT  47.376 35.581 51.57 35.941 ;
     RECT  2.304 35.941 9.954 35.969 ;
     RECT  10.8 35.231 10.818 36.013 ;
     RECT  60.444 35.803 65.25 36.029 ;
     RECT  67.248 35.851 69.03 36.041 ;
     RECT  10.728 36.013 10.818 36.077 ;
     RECT  60.444 36.029 62.097 36.121 ;
     RECT  10.728 36.077 10.746 36.149 ;
     RECT  0.324 36.139 0.342 36.211 ;
     RECT  60.372 36.121 62.097 36.247 ;
     RECT  20.772 30.541 20.79 36.283 ;
     RECT  58.716 35.339 58.734 36.311 ;
     RECT  2.304 35.969 4.482 36.419 ;
     RECT  67.248 36.041 68.994 36.419 ;
     RECT  68.364 36.419 68.994 36.509 ;
     RECT  0.324 36.211 0.558 36.557 ;
     RECT  18.615 35.509 18.954 36.589 ;
     RECT  66.096 36.481 66.114 36.589 ;
     RECT  20.268 36.283 20.79 36.625 ;
     RECT  62.892 36.029 65.25 36.661 ;
     RECT  66.024 36.589 66.114 36.661 ;
     RECT  68.364 36.509 68.454 36.749 ;
     RECT  60.012 36.247 62.097 36.787 ;
     RECT  62.892 36.661 66.33 36.787 ;
     RECT  67.248 36.419 67.302 36.787 ;
     RECT  0.324 36.557 0.342 36.859 ;
     RECT  2.412 36.419 4.482 36.859 ;
     RECT  5.292 35.969 9.954 36.859 ;
     RECT  18.615 36.589 19.17 36.895 ;
     RECT  20.268 36.625 21.15 36.895 ;
     RECT  0.216 36.859 0.342 37.037 ;
     RECT  18.615 36.895 21.15 37.057 ;
     RECT  21.888 35.203 38.646 37.057 ;
     RECT  58.824 37.057 58.842 37.129 ;
     RECT  58.824 37.129 58.878 37.147 ;
     RECT  58.752 37.147 58.878 37.165 ;
     RECT  2.412 36.859 9.954 37.192 ;
     RECT  2.304 37.192 9.954 37.193 ;
     RECT  60.012 36.787 67.302 37.291 ;
     RECT  68.364 36.749 68.418 37.291 ;
     RECT  58.752 37.165 58.914 37.355 ;
     RECT  60.012 37.291 68.418 37.355 ;
     RECT  60.012 37.355 65.898 37.427 ;
     RECT  46.764 35.941 51.57 37.463 ;
     RECT  10.836 37.363 10.854 37.589 ;
     RECT  46.8 37.463 51.57 37.589 ;
     RECT  10.8 37.705 10.818 37.741 ;
     RECT  0.54 37.561 0.558 37.805 ;
     RECT  66.672 37.355 68.418 37.805 ;
     RECT  10.764 37.741 10.818 37.859 ;
     RECT  67.752 37.805 68.418 37.901 ;
     RECT  60.444 37.427 65.682 37.931 ;
     RECT  60.516 37.931 65.682 38.003 ;
     RECT  4.104 37.193 9.954 38.039 ;
     RECT  4.104 38.039 9.162 38.129 ;
     RECT  67.752 37.901 67.806 38.129 ;
     RECT  2.304 37.193 3.294 38.155 ;
     RECT  4.104 38.129 8.226 38.155 ;
     RECT  67.752 38.129 67.77 38.189 ;
     RECT  58.716 37.435 58.734 38.245 ;
     RECT  60.588 38.003 65.682 38.281 ;
     RECT  66.672 37.805 66.69 38.309 ;
     RECT  69.012 38.059 69.03 38.309 ;
     RECT  10.764 37.859 10.782 38.399 ;
     RECT  60.588 38.281 65.754 38.399 ;
     RECT  2.304 38.155 8.226 38.525 ;
     RECT  2.304 38.525 7.038 38.669 ;
     RECT  60.588 38.399 65.682 38.669 ;
     RECT  9.936 38.039 9.954 38.785 ;
     RECT  58.716 38.245 58.806 38.827 ;
     RECT  2.304 38.669 4.554 38.849 ;
     RECT  7.776 38.525 8.226 38.911 ;
     RECT  0.144 38.203 0.162 38.923 ;
     RECT  7.776 38.911 8.298 38.923 ;
     RECT  58.716 38.827 58.842 38.939 ;
     RECT  66.708 38.947 66.726 39.019 ;
     RECT  10.908 38.911 10.926 39.047 ;
     RECT  0.144 38.923 0.342 39.053 ;
     RECT  18.615 37.057 38.646 39.055 ;
     RECT  66.708 39.019 67.302 39.091 ;
     RECT  66.708 39.091 67.842 39.115 ;
     RECT  0.144 39.053 0.27 39.149 ;
     RECT  7.776 38.923 8.586 39.181 ;
     RECT  9.396 38.785 9.954 39.181 ;
     RECT  66.708 39.115 68.382 39.209 ;
     RECT  60.768 38.669 65.682 39.281 ;
     RECT  56.415 24.971 56.697 39.325 ;
     RECT  0.252 39.149 0.27 39.341 ;
     RECT  64.728 39.281 65.682 39.361 ;
     RECT  7.776 39.181 9.954 39.389 ;
     RECT  56.304 39.325 56.697 39.389 ;
     RECT  10.872 39.451 10.89 39.523 ;
     RECT  66.708 39.209 67.878 39.533 ;
     RECT  59.976 39.211 59.994 39.559 ;
     RECT  64.728 39.361 65.79 39.587 ;
     RECT  2.304 38.849 4.518 39.631 ;
     RECT  5.364 38.669 7.002 39.631 ;
     RECT  7.776 39.389 8.19 39.631 ;
     RECT  9.144 39.389 9.954 39.659 ;
     RECT  5.364 39.631 8.19 39.773 ;
     RECT  10.8 39.523 10.89 39.785 ;
     RECT  64.728 39.587 65.07 39.785 ;
     RECT  2.304 39.631 4.554 39.857 ;
     RECT  5.364 39.773 8.154 39.883 ;
     RECT  59.976 39.559 60.03 39.893 ;
     RECT  60.012 39.893 60.03 39.901 ;
     RECT  60.768 39.281 63.99 39.901 ;
     RECT  66.708 39.533 66.726 39.901 ;
     RECT  10.8 39.785 10.818 40.019 ;
     RECT  9.144 39.659 9.198 40.091 ;
     RECT  4.212 39.857 4.554 40.099 ;
     RECT  5.328 39.883 8.154 40.099 ;
     RECT  18.576 39.055 38.754 40.099 ;
     RECT  0.144 39.883 0.162 40.123 ;
     RECT  69.012 40.075 69.03 40.127 ;
     RECT  65.844 39.631 65.898 40.135 ;
     RECT  66.672 39.901 66.726 40.135 ;
     RECT  60.012 39.901 63.99 40.171 ;
     RECT  64.728 39.785 64.818 40.171 ;
     RECT  60.012 40.171 64.818 40.289 ;
     RECT  18.576 40.099 39.006 40.297 ;
     RECT  47.376 37.589 51.57 40.361 ;
     RECT  18.576 40.297 39.078 40.397 ;
     RECT  67.752 39.533 67.878 40.405 ;
     RECT  0.144 40.123 0.234 40.459 ;
     RECT  0.144 40.459 0.342 40.555 ;
     RECT  9.036 40.531 9.09 40.555 ;
     RECT  4.212 40.099 8.154 40.567 ;
     RECT  2.304 39.857 3.294 40.603 ;
     RECT  4.212 40.567 8.262 40.603 ;
     RECT  9 40.555 9.09 40.603 ;
     RECT  14.868 40.567 14.886 40.639 ;
     RECT  65.844 40.135 66.726 40.675 ;
     RECT  0.108 40.555 0.342 40.685 ;
     RECT  2.304 40.603 3.438 40.711 ;
     RECT  4.212 40.603 9.09 40.711 ;
     RECT  2.304 40.711 9.09 40.739 ;
     RECT  60.264 40.289 64.818 40.829 ;
     RECT  67.752 40.405 68.418 40.829 ;
     RECT  65.628 40.675 66.726 40.843 ;
     RECT  14.832 40.639 14.886 40.864 ;
     RECT  61.128 40.829 64.818 40.873 ;
     RECT  9.936 39.659 9.954 40.891 ;
     RECT  61.128 40.873 64.854 40.925 ;
     RECT  18.576 40.397 38.934 40.981 ;
     RECT  14.832 40.864 14.922 41.009 ;
     RECT  10.728 41.107 10.746 41.179 ;
     RECT  10.728 41.179 10.818 41.207 ;
     RECT  2.304 40.739 8.442 41.213 ;
     RECT  0.108 40.685 0.198 41.357 ;
     RECT  10.8 41.207 10.818 41.369 ;
     RECT  0.144 41.357 0.198 41.405 ;
     RECT  2.304 41.213 3.654 41.405 ;
     RECT  4.392 41.213 8.442 41.521 ;
     RECT  9.18 40.891 9.954 41.521 ;
     RECT  4.392 41.521 9.954 41.549 ;
     RECT  14.832 41.009 14.85 41.549 ;
     RECT  13.215 13.517 13.497 41.611 ;
     RECT  60.264 40.829 60.282 41.611 ;
     RECT  61.128 40.925 64.818 41.611 ;
     RECT  68.328 40.829 68.418 41.611 ;
     RECT  60.264 41.611 64.818 41.647 ;
     RECT  65.628 40.843 67.266 41.647 ;
     RECT  68.328 41.611 69.03 41.647 ;
     RECT  13.104 41.611 13.497 41.648 ;
     RECT  4.392 41.549 8.838 41.747 ;
     RECT  2.304 41.405 3.438 41.819 ;
     RECT  0.144 41.405 0.162 41.837 ;
     RECT  60.264 41.647 69.03 41.864 ;
     RECT  2.415 41.819 3.438 41.909 ;
     RECT  58.716 38.939 58.806 41.917 ;
     RECT  60.264 41.864 66.402 41.917 ;
     RECT  2.415 41.909 3.294 41.945 ;
     RECT  58.716 41.917 58.878 41.989 ;
     RECT  59.796 41.917 66.402 41.989 ;
     RECT  1.152 41.755 1.17 41.995 ;
     RECT  4.392 41.747 8.73 41.995 ;
     RECT  4.32 41.995 8.73 42.017 ;
     RECT  67.284 41.864 69.03 42.053 ;
     RECT  10.836 41.947 10.854 42.077 ;
     RECT  14.868 41.989 14.886 42.089 ;
     RECT  1.152 41.995 1.278 42.125 ;
     RECT  5.508 42.017 8.73 42.179 ;
     RECT  58.716 41.989 66.402 42.179 ;
     RECT  9.936 41.549 9.954 42.323 ;
     RECT  0.54 42.151 0.558 42.413 ;
     RECT  10.8 42.223 10.818 42.449 ;
     RECT  67.284 42.053 68.418 42.509 ;
     RECT  4.32 42.017 4.77 42.565 ;
     RECT  2.415 41.945 2.862 42.601 ;
     RECT  4.248 42.565 4.77 42.691 ;
     RECT  2.304 42.601 2.862 42.701 ;
     RECT  9.144 42.529 9.306 42.719 ;
     RECT  58.716 42.179 66.366 42.749 ;
     RECT  58.716 42.749 58.95 42.755 ;
     RECT  59.724 42.749 66.366 42.755 ;
     RECT  67.32 42.509 68.418 42.797 ;
     RECT  4.104 42.691 4.77 42.799 ;
     RECT  5.508 42.179 8.298 42.799 ;
     RECT  4.104 42.799 8.298 42.811 ;
     RECT  2.34 42.701 2.862 42.835 ;
     RECT  3.672 42.811 8.298 42.835 ;
     RECT  10.836 42.961 10.854 43.097 ;
     RECT  0.108 42.952 0.126 43.18 ;
     RECT  2.34 42.835 8.298 43.259 ;
     RECT  65.88 42.755 66.366 43.259 ;
     RECT  66.168 43.259 66.366 43.267 ;
     RECT  0.108 43.18 0.198 43.277 ;
     RECT  9.18 42.719 9.306 43.295 ;
     RECT  0.18 43.277 0.198 43.303 ;
     RECT  2.34 43.259 3.294 43.331 ;
     RECT  59.724 42.755 64.566 43.331 ;
     RECT  66.168 43.267 66.474 43.375 ;
     RECT  9.504 43.339 9.63 43.439 ;
     RECT  4.248 43.259 8.298 43.501 ;
     RECT  58.716 42.755 58.842 43.537 ;
     RECT  0.18 43.303 0.558 43.565 ;
     RECT  67.32 42.797 68.382 43.565 ;
     RECT  58.716 43.537 58.878 43.613 ;
     RECT  67.788 43.565 68.382 43.627 ;
     RECT  58.716 43.613 58.842 43.637 ;
     RECT  2.34 43.331 3.078 43.681 ;
     RECT  60.048 43.331 64.566 43.681 ;
     RECT  9.504 43.439 9.558 43.709 ;
     RECT  58.716 43.637 58.806 43.799 ;
     RECT  60.048 43.681 64.602 43.799 ;
     RECT  60.048 43.799 60.93 43.949 ;
     RECT  4.248 43.501 8.694 44.041 ;
     RECT  61.815 43.799 64.602 44.077 ;
     RECT  2.304 43.681 3.078 44.185 ;
     RECT  60.048 43.949 60.894 44.185 ;
     RECT  61.815 44.077 64.854 44.185 ;
     RECT  66.168 43.375 66.582 44.185 ;
     RECT  0.144 44.011 0.162 44.189 ;
     RECT  4.248 44.041 8.73 44.213 ;
     RECT  59.868 44.185 60.894 44.237 ;
     RECT  61.815 44.185 66.618 44.249 ;
     RECT  2.304 44.185 3.402 44.311 ;
     RECT  4.248 44.213 8.37 44.311 ;
     RECT  9.468 44.221 9.486 44.311 ;
     RECT  41.436 23.899 45.897 44.347 ;
     RECT  59.868 44.237 60.678 44.375 ;
     RECT  64.764 44.249 66.618 44.381 ;
     RECT  60.048 44.375 60.678 44.411 ;
     RECT  66.6 44.381 66.618 44.411 ;
     RECT  2.304 44.311 8.37 44.447 ;
     RECT  58.716 43.799 58.734 44.617 ;
     RECT  67.788 43.627 69.03 44.653 ;
     RECT  10.8 43.771 10.818 44.689 ;
     RECT  41.436 44.347 45.99 44.689 ;
     RECT  10.728 44.689 10.818 44.717 ;
     RECT  9.288 44.311 9.486 44.753 ;
     RECT  0.216 44.491 0.234 44.779 ;
     RECT  10.728 44.717 10.746 44.789 ;
     RECT  58.716 44.617 58.878 44.789 ;
     RECT  41.436 44.689 46.422 44.887 ;
     RECT  64.764 44.381 65.646 44.915 ;
     RECT  0.216 44.779 0.342 45.115 ;
     RECT  9.288 44.753 9.45 45.149 ;
     RECT  41.436 44.887 46.458 45.193 ;
     RECT  47.376 40.361 51.297 45.193 ;
     RECT  61.815 44.249 63.99 45.193 ;
     RECT  64.764 44.915 65.574 45.193 ;
     RECT  66.744 44.653 69.03 45.193 ;
     RECT  0.216 45.115 0.414 45.211 ;
     RECT  66.6 45.193 69.03 45.221 ;
     RECT  60.048 44.411 60.39 45.265 ;
     RECT  2.34 44.447 8.37 45.293 ;
     RECT  59.868 45.265 60.39 45.301 ;
     RECT  2.34 45.293 8.334 45.355 ;
     RECT  9.252 45.301 9.27 45.391 ;
     RECT  58.716 44.789 58.842 45.419 ;
     RECT  59.868 45.301 60.822 45.419 ;
     RECT  61.815 45.193 65.574 45.419 ;
     RECT  0.144 45.211 0.414 45.485 ;
     RECT  2.304 45.355 8.334 45.527 ;
     RECT  0.144 45.485 0.342 45.581 ;
     RECT  67.752 45.221 69.03 45.599 ;
     RECT  63.648 45.419 65.574 45.689 ;
     RECT  59.868 45.419 60.39 45.697 ;
     RECT  65.484 45.689 65.574 45.733 ;
     RECT  66.6 45.221 66.762 45.733 ;
     RECT  59.724 45.697 60.39 45.773 ;
     RECT  1.152 45.835 1.17 46.013 ;
     RECT  10.8 45.661 10.818 46.031 ;
     RECT  0.324 45.581 0.342 46.061 ;
     RECT  67.752 45.599 68.958 46.067 ;
     RECT  2.415 45.527 8.334 46.069 ;
     RECT  9.108 45.391 9.27 46.069 ;
     RECT  2.415 46.069 9.27 46.109 ;
     RECT  61.815 45.419 62.766 46.219 ;
     RECT  63.648 45.689 64.746 46.219 ;
     RECT  18.54 40.981 38.934 46.309 ;
     RECT  65.484 45.733 66.762 46.309 ;
     RECT  67.752 46.067 67.914 46.309 ;
     RECT  59.868 45.773 60.39 46.345 ;
     RECT  61.815 46.219 64.746 46.345 ;
     RECT  10.728 46.237 10.746 46.373 ;
     RECT  2.415 46.109 8.334 46.381 ;
     RECT  2.304 46.381 8.334 46.445 ;
     RECT  9.072 46.109 9.27 46.534 ;
     RECT  65.484 46.309 67.914 46.541 ;
     RECT  9.072 46.534 9.306 46.579 ;
     RECT  59.868 46.345 64.746 46.603 ;
     RECT  65.484 46.541 66.726 46.603 ;
     RECT  59.868 46.603 66.726 46.637 ;
     RECT  9.072 46.579 10.026 46.679 ;
     RECT  0.144 46.555 0.198 46.732 ;
     RECT  58.716 45.419 58.806 46.741 ;
     RECT  58.716 46.741 58.842 46.813 ;
     RECT  18.54 46.309 39.114 46.849 ;
     RECT  40.215 8.879 40.497 46.849 ;
     RECT  2.415 46.445 8.334 46.885 ;
     RECT  9.072 46.679 9.954 46.885 ;
     RECT  67.788 46.541 67.914 46.885 ;
     RECT  68.94 46.067 68.958 46.885 ;
     RECT  67.788 46.885 68.958 46.891 ;
     RECT  0.108 46.732 0.198 46.921 ;
     RECT  0.108 46.921 0.558 47.021 ;
     RECT  58.716 46.813 58.914 47.039 ;
     RECT  67.788 46.891 69.03 47.039 ;
     RECT  0.18 47.021 0.558 47.069 ;
     RECT  58.716 47.039 58.878 47.069 ;
     RECT  59.868 46.637 66.654 47.111 ;
     RECT  67.788 47.039 68.994 47.111 ;
     RECT  2.415 46.885 9.954 47.183 ;
     RECT  10.8 47.011 10.818 47.183 ;
     RECT  67.788 47.111 68.958 47.183 ;
     RECT  58.716 47.069 58.806 47.219 ;
     RECT  59.868 47.111 60.318 47.219 ;
     RECT  2.415 47.183 8.91 47.272 ;
     RECT  58.716 47.219 58.77 47.309 ;
     RECT  59.868 47.219 60.138 47.309 ;
     RECT  61.092 47.111 66.654 47.309 ;
     RECT  61.815 47.309 66.654 47.389 ;
     RECT  67.788 47.183 68.454 47.405 ;
     RECT  0.54 47.069 0.558 47.419 ;
     RECT  18.54 46.849 40.497 47.461 ;
     RECT  41.436 45.193 51.297 47.461 ;
     RECT  0.54 47.419 0.63 47.489 ;
     RECT  61.815 47.389 66.69 47.489 ;
     RECT  0.54 47.489 0.558 47.501 ;
     RECT  67.788 47.405 68.418 47.551 ;
     RECT  10.908 47.623 10.926 47.731 ;
     RECT  10.908 47.731 10.998 47.849 ;
     RECT  61.815 47.489 66.186 47.849 ;
     RECT  9.936 47.183 9.954 47.929 ;
     RECT  2.304 47.272 8.91 48.001 ;
     RECT  9.864 47.929 9.954 48.001 ;
     RECT  61.815 47.849 65.538 48.029 ;
     RECT  67.248 47.551 68.418 48.119 ;
     RECT  2.304 48.001 9.954 48.155 ;
     RECT  61.056 48.091 61.074 48.163 ;
     RECT  61.815 48.029 65.142 48.163 ;
     RECT  67.32 48.119 68.418 48.269 ;
     RECT  61.056 48.163 65.142 48.271 ;
     RECT  2.304 48.155 9.126 48.299 ;
     RECT  0.108 48.331 0.126 48.379 ;
     RECT  2.304 48.299 8.37 48.389 ;
     RECT  10.836 48.271 10.854 48.389 ;
     RECT  60.804 48.271 65.142 48.425 ;
     RECT  0.108 48.379 0.198 48.476 ;
     RECT  58.716 47.309 58.734 48.505 ;
     RECT  67.356 48.269 68.418 48.523 ;
     RECT  0.144 48.476 0.198 48.653 ;
     RECT  66.564 48.541 66.582 48.695 ;
     RECT  9.108 48.299 9.126 48.731 ;
     RECT  58.716 48.505 58.878 48.767 ;
     RECT  10.8 48.469 10.818 48.839 ;
     RECT  60.804 48.425 63.702 48.839 ;
     RECT  2.304 48.389 5.85 48.929 ;
     RECT  6.588 48.389 8.37 48.929 ;
     RECT  64.476 48.425 65.142 48.937 ;
     RECT  59.868 47.309 60.03 48.965 ;
     RECT  1.152 48.523 1.17 48.973 ;
     RECT  2.415 48.929 3.294 48.989 ;
     RECT  2.415 48.989 2.79 49.001 ;
     RECT  6.696 48.929 8.37 49.001 ;
     RECT  1.152 48.973 1.206 49.003 ;
     RECT  59.976 48.965 60.03 49.003 ;
     RECT  60.804 48.839 62.334 49.003 ;
     RECT  1.116 49.003 1.206 49.037 ;
     RECT  64.476 48.937 65.286 49.045 ;
     RECT  0.18 48.653 0.198 49.051 ;
     RECT  67.356 48.523 69.03 49.099 ;
     RECT  0.18 49.051 0.306 49.109 ;
     RECT  0.18 49.109 0.198 49.133 ;
     RECT  1.116 49.037 1.134 49.181 ;
     RECT  64.476 49.045 65.394 49.207 ;
     RECT  4.104 48.929 5.85 49.235 ;
     RECT  58.716 48.767 58.842 49.343 ;
     RECT  4.968 49.235 5.85 49.379 ;
     RECT  59.976 49.003 62.334 49.379 ;
     RECT  4.104 49.235 4.122 49.469 ;
     RECT  4.968 49.379 5.058 49.469 ;
     RECT  5.832 49.379 5.85 49.469 ;
     RECT  64.476 49.207 66.186 49.469 ;
     RECT  6.696 49.001 8.298 49.577 ;
     RECT  63.216 48.839 63.702 49.585 ;
     RECT  63.216 49.585 63.738 49.621 ;
     RECT  64.476 49.469 66.042 49.621 ;
     RECT  6.732 49.577 8.298 49.723 ;
     RECT  6.732 49.723 8.406 49.739 ;
     RECT  9.36 49.351 9.378 49.739 ;
     RECT  59.976 49.379 62.262 49.771 ;
     RECT  6.732 49.739 6.75 49.775 ;
     RECT  7.815 49.739 8.406 49.775 ;
     RECT  63.216 49.621 66.042 49.891 ;
     RECT  58.716 49.343 58.806 50.009 ;
     RECT  63.18 49.891 66.042 50.009 ;
     RECT  7.815 49.775 8.37 50.045 ;
     RECT  59.904 49.771 62.262 50.081 ;
     RECT  10.836 49.981 10.854 50.117 ;
     RECT  7.815 50.045 8.298 50.153 ;
     RECT  9.396 49.891 9.414 50.153 ;
     RECT  60.876 50.081 62.262 50.161 ;
     RECT  60.876 50.161 62.406 50.251 ;
     RECT  63.18 50.009 65.754 50.251 ;
     RECT  67.248 49.099 69.03 50.251 ;
     RECT  59.904 50.081 60.066 50.395 ;
     RECT  66.6 50.251 69.03 50.459 ;
     RECT  59.868 50.395 60.066 50.629 ;
     RECT  59.724 50.629 60.066 50.729 ;
     RECT  60.876 50.251 65.754 50.729 ;
     RECT  60.048 50.729 60.066 50.819 ;
     RECT  58.716 50.009 58.734 50.827 ;
     RECT  60.876 50.729 62.442 50.861 ;
     RECT  60.876 50.861 62.262 50.863 ;
     RECT  63.36 50.729 65.754 50.891 ;
     RECT  58.716 50.827 58.806 50.971 ;
     RECT  60.192 50.863 62.262 50.999 ;
     RECT  64.764 50.891 65.754 50.999 ;
     RECT  60.984 50.999 62.262 51.089 ;
     RECT  67.248 50.459 69.03 51.089 ;
     RECT  58.716 50.971 58.842 51.097 ;
     RECT  60.984 51.089 62.097 51.149 ;
     RECT  58.716 51.097 58.878 51.161 ;
     RECT  60.192 50.999 60.21 51.161 ;
     RECT  58.752 51.161 58.878 51.197 ;
     RECT  63.36 50.891 63.774 51.197 ;
     RECT  65.016 50.999 65.754 51.197 ;
     RECT  67.248 51.089 67.266 51.197 ;
     RECT  63.36 51.197 63.558 51.203 ;
     RECT  58.752 51.197 58.842 51.233 ;
     RECT  65.016 51.197 65.43 51.269 ;
     RECT  65.016 51.269 65.394 51.359 ;
     RECT  66.168 51.241 66.186 51.359 ;
     RECT  68.364 51.089 69.03 51.395 ;
     RECT  69.012 51.395 69.03 51.539 ;
     RECT  63.54 51.203 63.558 51.629 ;
     RECT  65.088 51.359 65.394 51.629 ;
     RECT  66.672 51.367 66.69 51.629 ;
     RECT  61.092 51.149 62.097 51.737 ;
     RECT  58.788 51.233 58.806 51.773 ;
     RECT  65.376 51.629 65.394 51.773 ;
     RECT  18.54 47.461 51.297 63.787 ;
     RECT  18.396 63.787 51.297 64.363 ;
     RECT  18.108 64.363 51.297 64.867 ;
     RECT  17.748 64.867 51.297 65.011 ;
     RECT  17.712 65.011 51.297 65.245 ;
     RECT  17.532 65.245 51.297 66.479 ;
     RECT  2.415 49.001 2.697 66.707 ;
     RECT  7.815 50.153 8.097 66.707 ;
     RECT  13.215 41.648 13.497 66.707 ;
     RECT  39.132 66.479 51.297 66.707 ;
     RECT  56.415 39.389 56.697 66.707 ;
     RECT  61.815 51.737 62.097 66.707 ;
     RECT  17.532 66.479 38.286 66.749 ;
     RECT  39.132 66.707 51.105 66.749 ;
     RECT  29.196 66.749 38.286 66.785 ;
     RECT  29.196 66.785 38.214 66.893 ;
     RECT  2.415 66.707 2.505 66.977 ;
     RECT  7.815 66.707 7.905 66.977 ;
     RECT  13.215 66.707 13.305 66.977 ;
     RECT  39.312 66.749 51.105 66.977 ;
     RECT  56.415 66.707 56.505 66.977 ;
     RECT  61.815 66.707 61.905 66.977 ;
     RECT  39.312 66.977 50.454 67.019 ;
     RECT  17.532 66.749 28.062 67.133 ;
     RECT  39.312 67.019 50.31 67.133 ;
     RECT  29.196 66.893 29.538 67.181 ;
     RECT  50.04 67.133 50.31 67.181 ;
     RECT  17.532 67.133 28.026 67.229 ;
     RECT  30.384 66.893 37.926 67.229 ;
     RECT  39.312 67.133 49.266 67.229 ;
     RECT  50.04 67.181 50.058 67.229 ;
     RECT  17.532 67.229 25.218 67.277 ;
     RECT  26.208 67.229 27.918 67.277 ;
     RECT  29.196 67.181 29.322 67.277 ;
     RECT  30.636 67.229 37.926 67.277 ;
     RECT  39.312 67.229 40.554 67.277 ;
     RECT  41.472 67.229 47.682 67.277 ;
     RECT  48.456 67.229 49.266 67.277 ;
     RECT  27 67.277 27.018 67.325 ;
     RECT  44.892 67.277 44.91 67.325 ;
     RECT  46.44 67.277 46.458 67.325 ;
     RECT  47.196 67.277 47.502 67.325 ;
     RECT  47.196 67.325 47.214 67.373 ;
     RECT  29.304 67.277 29.322 67.421 ;
     RECT  21.708 67.277 21.726 67.805 ;
     RECT  17.568 67.277 19.926 67.853 ;
     RECT  23.688 67.277 23.706 67.853 ;
     RECT  30.672 67.277 31.914 67.853 ;
     RECT  34.704 67.277 35.37 67.853 ;
     RECT  40.536 67.277 40.554 67.853 ;
     RECT  41.472 67.277 41.49 67.853 ;
     RECT  17.568 67.853 18.306 68.429 ;
     RECT  27.828 67.277 27.846 68.429 ;
     RECT  30.672 67.853 31.806 68.429 ;
     RECT  42.552 67.277 42.57 68.429 ;
     RECT  18.108 68.429 18.126 68.477 ;
     RECT  22.068 68.491 22.086 68.669 ;
     RECT  38.088 68.731 38.106 68.779 ;
     RECT  41.796 68.635 41.814 68.813 ;
     RECT  28.692 68.635 28.71 68.875 ;
     RECT  38.088 68.779 38.178 68.875 ;
     RECT  40.572 68.731 40.59 68.909 ;
     RECT  21.96 68.875 21.978 69.005 ;
     RECT  28.476 68.875 28.782 69.005 ;
     RECT  30.924 68.429 31.806 69.005 ;
     RECT  34.524 68.875 34.542 69.005 ;
     RECT  35.352 67.853 35.37 69.005 ;
     RECT  37.908 68.875 38.682 69.005 ;
     RECT  39.816 68.875 39.834 69.005 ;
     RECT  44.424 68.875 44.442 69.005 ;
     RECT  48.96 67.277 48.978 69.005 ;
    LAYER M4 ;
     RECT  0.06 17.712 0.133 49.128 ;
     RECT  0.133 17.712 0.569 49.176 ;
     RECT  0.569 17.808 1.145 49.176 ;
     RECT  1.145 17.808 2.408 49.08 ;
     RECT  2.408 2.148 2.512 66.972 ;
     RECT  2.512 2.418 2.704 66.702 ;
     RECT  2.704 17.76 4.489 49.08 ;
     RECT  4.489 17.616 5.573 49.08 ;
     RECT  5.573 17.616 5.609 29.928 ;
     RECT  5.609 17.616 6.649 25.32 ;
     RECT  5.609 26.304 6.649 29.928 ;
     RECT  6.649 17.616 7.189 29.928 ;
     RECT  5.573 30.912 7.189 49.08 ;
     RECT  7.189 17.616 7.808 49.08 ;
     RECT  7.808 2.148 7.912 66.972 ;
     RECT  7.912 2.418 8.104 66.702 ;
     RECT  8.104 33.552 8.165 44.712 ;
     RECT  8.165 33.552 8.201 33.912 ;
     RECT  8.165 34.896 8.201 44.712 ;
     RECT  8.201 40.56 8.243 44.712 ;
     RECT  8.104 20.352 8.273 24.12 ;
     RECT  8.104 30.144 8.309 32.472 ;
     RECT  8.243 40.56 8.309 43.848 ;
     RECT  8.104 45.984 8.345 48.456 ;
     RECT  8.345 46.08 8.387 48.456 ;
     RECT  8.104 49.728 8.428 50.424 ;
     RECT  8.104 18.768 8.453 18.792 ;
     RECT  8.309 43.824 8.453 43.848 ;
     RECT  8.387 46.08 8.453 48.168 ;
     RECT  8.201 34.896 8.489 39.384 ;
     RECT  8.309 31.488 8.705 32.472 ;
     RECT  8.453 48.144 8.705 48.168 ;
     RECT  8.273 20.352 8.777 23.64 ;
     RECT  8.309 30.144 8.813 30.168 ;
     RECT  8.309 40.56 9.029 42.84 ;
     RECT  8.453 46.08 9.029 47.16 ;
     RECT  8.104 25.44 9.065 27.24 ;
     RECT  8.777 20.352 9.101 21.768 ;
     RECT  9.029 40.608 9.245 42.84 ;
     RECT  8.705 31.968 9.281 32.472 ;
     RECT  8.489 34.896 9.281 39.288 ;
     RECT  9.029 46.464 9.281 47.16 ;
     RECT  9.101 20.352 9.317 21.432 ;
     RECT  8.777 22.8 9.317 23.64 ;
     RECT  9.281 37.056 9.317 39.288 ;
     RECT  9.245 41.616 9.317 42.84 ;
     RECT  9.281 46.56 9.317 47.16 ;
     RECT  9.281 31.968 9.353 31.992 ;
     RECT  9.317 37.056 9.353 38.424 ;
     RECT  9.281 34.896 9.425 35.832 ;
     RECT  9.065 26.304 9.461 27.24 ;
     RECT  9.317 20.352 9.497 21 ;
     RECT  9.317 22.8 9.497 23.352 ;
     RECT  10.717 21.6 10.829 21.624 ;
     RECT  9.317 41.616 10.865 42.072 ;
     RECT  12.901 13.488 12.908 13.512 ;
     RECT  9.497 20.352 12.949 20.376 ;
     RECT  12.908 13.056 13.208 13.512 ;
     RECT  8.104 17.616 13.208 17.64 ;
     RECT  12.949 20.064 13.208 20.376 ;
     RECT  9.497 23.328 13.208 23.352 ;
     RECT  9.461 26.304 13.208 26.328 ;
     RECT  8.201 33.888 13.208 33.912 ;
     RECT  9.425 34.896 13.208 34.92 ;
     RECT  9.353 37.056 13.208 37.08 ;
     RECT  9.353 38.4 13.208 38.424 ;
     RECT  9.245 40.608 13.208 40.632 ;
     RECT  10.865 41.616 13.208 41.976 ;
     RECT  9.317 47.136 13.208 47.16 ;
     RECT  8.428 50.4 13.208 50.424 ;
     RECT  13.208 2.148 13.312 66.972 ;
     RECT  13.312 2.418 13.504 66.702 ;
     RECT  13.504 20.064 14.749 20.088 ;
     RECT  14.749 19.968 14.821 20.088 ;
     RECT  14.821 19.968 14.861 20.184 ;
     RECT  17.521 67.248 17.593 67.272 ;
     RECT  17.557 68.4 17.593 68.424 ;
     RECT  17.593 67.248 17.737 68.424 ;
     RECT  17.737 66.72 18.097 68.424 ;
     RECT  18.097 66.72 18.419 68.472 ;
     RECT  13.504 13.008 18.608 13.032 ;
     RECT  14.861 20.16 18.608 20.184 ;
     RECT  13.504 23.328 18.608 23.352 ;
     RECT  13.504 26.304 18.608 26.328 ;
     RECT  13.504 33.888 18.608 33.912 ;
     RECT  13.504 34.896 18.608 34.92 ;
     RECT  13.504 37.056 18.608 37.08 ;
     RECT  13.504 38.4 18.608 38.424 ;
     RECT  13.504 40.608 18.608 40.632 ;
     RECT  13.504 41.616 18.608 42.072 ;
     RECT  13.504 47.136 18.608 47.16 ;
     RECT  13.504 50.4 18.608 50.424 ;
     RECT  18.421 63.072 18.608 63.096 ;
     RECT  18.419 66.72 18.608 67.848 ;
     RECT  18.608 2.148 18.712 67.848 ;
     RECT  18.421 68.928 18.803 68.952 ;
     RECT  18.712 2.418 18.904 67.848 ;
     RECT  18.904 40.608 19.001 42.072 ;
     RECT  18.904 63.072 19.001 64.056 ;
     RECT  18.904 50.4 19.091 50.712 ;
     RECT  18.904 20.064 19.613 20.184 ;
     RECT  18.904 66.72 20.051 67.848 ;
     RECT  18.904 37.056 20.329 37.08 ;
     RECT  19.001 63.264 20.401 64.056 ;
     RECT  19.091 50.688 20.473 50.712 ;
     RECT  20.473 50.352 20.549 50.712 ;
     RECT  19.001 40.704 21.053 42.072 ;
     RECT  20.401 62.736 21.061 64.056 ;
     RECT  21.053 41.712 21.161 42.072 ;
     RECT  21.061 62.592 21.377 64.056 ;
     RECT  21.161 42.048 21.485 42.072 ;
     RECT  20.051 66.72 21.637 67.272 ;
     RECT  21.637 66.72 21.733 67.8 ;
     RECT  21.733 66.72 21.737 68.424 ;
     RECT  21.737 66.72 21.769 67.272 ;
     RECT  21.737 68.4 21.829 68.424 ;
     RECT  21.377 63.12 21.881 64.056 ;
     RECT  21.829 68.4 22.022 69 ;
     RECT  22.022 68.4 22.067 68.664 ;
     RECT  22.067 68.496 22.097 68.664 ;
     RECT  22.097 68.496 22.115 68.52 ;
     RECT  22.124 65.088 22.211 65.112 ;
     RECT  18.904 38.4 22.381 38.424 ;
     RECT  21.877 39.456 22.381 39.48 ;
     RECT  21.769 66.624 22.693 67.272 ;
     RECT  21.881 63.216 22.94 64.056 ;
     RECT  22.381 38.4 23.065 39.48 ;
     RECT  21.053 40.704 23.065 40.728 ;
     RECT  22.94 63.072 23.065 64.056 ;
     RECT  22.693 66.096 23.677 67.272 ;
     RECT  23.065 38.4 23.713 40.728 ;
     RECT  23.065 62.736 23.821 64.056 ;
     RECT  23.677 66.096 23.987 67.848 ;
     RECT  18.904 13.008 24.008 13.032 ;
     RECT  19.613 20.064 24.008 20.088 ;
     RECT  18.904 23.328 24.008 23.352 ;
     RECT  18.904 26.304 24.008 26.328 ;
     RECT  18.904 33.888 24.008 33.912 ;
     RECT  18.904 34.896 24.008 34.92 ;
     RECT  20.329 36.912 24.008 37.08 ;
     RECT  23.713 38.4 24.008 41.016 ;
     RECT  18.904 47.136 24.008 47.16 ;
     RECT  20.549 50.352 24.008 50.376 ;
     RECT  23.821 62.736 24.008 64.968 ;
     RECT  23.987 66.096 24.008 67.272 ;
     RECT  24.008 2.148 24.112 67.272 ;
     RECT  24.112 2.418 24.304 67.272 ;
     RECT  24.037 68.928 24.419 68.952 ;
     RECT  24.304 63.072 24.689 64.44 ;
     RECT  24.304 26.304 24.761 27.336 ;
     RECT  24.761 27.312 25.283 27.336 ;
     RECT  25.333 28.32 25.427 28.344 ;
     RECT  24.304 65.568 25.453 67.272 ;
     RECT  24.689 64.416 25.513 64.44 ;
     RECT  25.453 65.568 25.513 65.592 ;
     RECT  25.513 64.416 25.625 65.592 ;
     RECT  24.689 63.072 25.669 63.288 ;
     RECT  25.625 64.416 25.669 64.44 ;
     RECT  25.837 28.56 26.053 28.584 ;
     RECT  25.625 65.568 26.345 65.592 ;
     RECT  25.669 63.072 26.737 64.44 ;
     RECT  26.053 28.56 26.773 28.728 ;
     RECT  26.773 28.56 26.813 28.776 ;
     RECT  26.737 63.072 26.828 64.632 ;
     RECT  26.813 28.704 26.885 28.776 ;
     RECT  24.304 23.328 26.953 23.352 ;
     RECT  26.885 28.752 26.957 28.776 ;
     RECT  25.453 66.72 26.989 67.272 ;
     RECT  26.989 66.72 27.073 67.32 ;
     RECT  27.073 66.72 27.205 67.272 ;
     RECT  26.828 62.832 27.313 64.632 ;
     RECT  27.308 10.08 27.349 10.104 ;
     RECT  27.349 10.08 27.395 10.584 ;
     RECT  27.589 68.928 27.817 68.952 ;
     RECT  27.205 65.952 27.929 67.272 ;
     RECT  27.929 65.952 28.037 67.224 ;
     RECT  28.037 65.952 28.073 67.128 ;
     RECT  27.817 68.4 28.115 68.952 ;
     RECT  28.073 65.952 28.181 66.744 ;
     RECT  28.115 68.544 28.261 68.952 ;
     RECT  27.313 62.832 28.321 64.92 ;
     RECT  28.316 3.6 28.357 3.624 ;
     RECT  24.304 13.008 28.403 13.032 ;
     RECT  28.357 5.088 28.444 5.112 ;
     RECT  28.321 62.832 28.501 65.544 ;
     RECT  28.357 2.832 28.681 3.624 ;
     RECT  28.261 68.544 28.691 69 ;
     RECT  28.691 68.64 28.739 69 ;
     RECT  28.681 2.4 28.789 3.624 ;
     RECT  28.739 68.88 28.793 69 ;
     RECT  28.789 2.304 28.825 3.624 ;
     RECT  28.793 68.88 28.835 68.952 ;
     RECT  24.304 33.888 28.933 33.912 ;
     RECT  24.304 34.896 28.933 34.92 ;
     RECT  28.429 0.048 28.969 0.072 ;
     RECT  28.753 1.104 28.969 1.128 ;
     RECT  28.969 0.048 29.041 1.128 ;
     RECT  28.825 2.304 29.041 3.72 ;
     RECT  29.041 43.824 29.113 43.848 ;
     RECT  28.181 66.72 29.125 66.744 ;
     RECT  27.395 10.56 29.149 10.584 ;
     RECT  29.041 0.048 29.185 3.72 ;
     RECT  29.113 4.704 29.185 4.728 ;
     RECT  29.125 66.72 29.221 67.272 ;
     RECT  29.113 43.488 29.257 43.848 ;
     RECT  28.501 62.544 29.269 65.544 ;
     RECT  29.221 66.72 29.269 67.32 ;
     RECT  29.269 62.544 29.276 67.32 ;
     RECT  29.276 62.544 29.363 67.416 ;
     RECT  29.185 0.048 29.408 4.728 ;
     RECT  29.293 5.76 29.408 5.784 ;
     RECT  29.183 7.392 29.408 7.416 ;
     RECT  29.149 10.56 29.408 10.872 ;
     RECT  24.304 20.064 29.408 20.088 ;
     RECT  26.953 23.328 29.408 23.592 ;
     RECT  24.761 26.304 29.408 26.328 ;
     RECT  28.933 33.888 29.408 34.92 ;
     RECT  24.304 36.912 29.408 37.08 ;
     RECT  24.304 38.4 29.408 40.728 ;
     RECT  29.257 43.488 29.408 44.424 ;
     RECT  24.304 47.136 29.408 47.16 ;
     RECT  24.304 50.352 29.408 50.376 ;
     RECT  29.363 62.544 29.408 67.272 ;
     RECT  28.835 68.928 29.651 68.952 ;
     RECT  29.408 0.048 29.704 67.272 ;
     RECT  29.704 62.544 29.765 64.152 ;
     RECT  29.765 63.264 29.837 64.152 ;
     RECT  29.837 63.264 29.98 64.056 ;
     RECT  29.98 63.36 30.197 64.056 ;
     RECT  29.704 26.304 30.449 26.328 ;
     RECT  29.704 0.048 30.46 7.416 ;
     RECT  29.704 66.336 30.733 67.272 ;
     RECT  30.62 68.4 30.733 68.424 ;
     RECT  30.733 66.336 30.757 68.424 ;
     RECT  29.704 36.912 30.805 37.08 ;
     RECT  29.704 38.4 30.805 40.728 ;
     RECT  30.757 66.336 30.853 68.808 ;
     RECT  30.853 66.336 30.898 68.904 ;
     RECT  30.898 66.336 30.899 69 ;
     RECT  30.805 36.912 30.917 40.728 ;
     RECT  29.704 43.104 30.949 44.424 ;
     RECT  30.949 42.768 30.989 44.424 ;
     RECT  30.899 68.784 31.187 69 ;
     RECT  30.989 42.768 31.205 42.792 ;
     RECT  30.197 63.84 31.237 64.056 ;
     RECT  31.187 68.88 31.283 69 ;
     RECT  30.46 0.048 31.349 6.264 ;
     RECT  30.899 66.336 31.385 67.752 ;
     RECT  31.349 0.048 31.475 5.976 ;
     RECT  30.46 7.392 31.489 7.416 ;
     RECT  30.989 44.4 31.525 44.424 ;
     RECT  29.704 45.408 31.525 45.432 ;
     RECT  31.237 63.84 31.525 64.2 ;
     RECT  31.489 7.392 31.529 7.512 ;
     RECT  31.525 63.648 31.813 64.2 ;
     RECT  31.525 44.4 31.817 45.432 ;
     RECT  31.475 1.824 31.859 5.976 ;
     RECT  31.385 66.72 31.885 67.752 ;
     RECT  31.283 68.976 32.051 69 ;
     RECT  31.529 7.44 32.101 7.512 ;
     RECT  31.813 63.264 32.105 64.2 ;
     RECT  31.475 0.048 32.243 0.84 ;
     RECT  31.885 66.72 32.339 67.848 ;
     RECT  31.993 31.392 32.357 31.416 ;
     RECT  32.105 63.264 32.357 64.056 ;
     RECT  31.859 1.872 32.485 5.976 ;
     RECT  32.485 1.872 32.581 6.312 ;
     RECT  32.581 1.872 32.677 6.36 ;
     RECT  32.101 7.44 32.677 7.56 ;
     RECT  32.357 63.264 32.965 63.672 ;
     RECT  32.243 0.048 33.005 0.168 ;
     RECT  32.677 1.872 33.037 7.56 ;
     RECT  33.005 0.144 33.049 0.168 ;
     RECT  33.037 1.872 33.181 7.992 ;
     RECT  33.181 1.872 33.433 8.088 ;
     RECT  32.965 63.216 33.445 63.672 ;
     RECT  33.433 1.728 33.517 8.088 ;
     RECT  32.929 32.304 33.653 32.328 ;
     RECT  34.309 68.928 34.469 68.952 ;
     RECT  33.445 63.216 34.508 63.816 ;
     RECT  34.469 68.928 34.508 69 ;
     RECT  34.508 68.88 34.595 69 ;
     RECT  34.595 68.928 34.691 69 ;
     RECT  32.339 66.72 34.693 67.272 ;
     RECT  33.517 2.256 34.808 8.088 ;
     RECT  29.704 20.064 34.808 20.088 ;
     RECT  29.704 23.328 34.808 23.592 ;
     RECT  29.704 33.888 34.808 34.92 ;
     RECT  30.917 36.912 34.808 37.08 ;
     RECT  30.917 38.4 34.808 40.728 ;
     RECT  31.817 44.4 34.808 45.192 ;
     RECT  29.704 47.136 34.808 47.16 ;
     RECT  29.704 50.352 34.808 50.376 ;
     RECT  34.508 63.168 34.808 63.816 ;
     RECT  34.693 66.72 34.808 67.848 ;
     RECT  34.808 2.148 34.885 67.848 ;
     RECT  34.789 0.336 34.981 0.36 ;
     RECT  34.885 1.728 35.104 67.848 ;
     RECT  35.104 66.912 35.123 67.848 ;
     RECT  35.104 33.888 35.267 34.92 ;
     RECT  34.981 0.144 35.363 0.36 ;
     RECT  35.549 0.096 35.633 0.12 ;
     RECT  35.104 1.728 35.701 8.52 ;
     RECT  35.701 1.152 35.891 8.52 ;
     RECT  35.891 1.68 36.097 8.52 ;
     RECT  34.691 68.976 36.179 69 ;
     RECT  35.104 36.912 36.353 40.632 ;
     RECT  35.104 63.12 36.421 64.44 ;
     RECT  35.123 66.912 36.764 67.272 ;
     RECT  36.353 38.304 36.785 40.632 ;
     RECT  36.764 66.72 36.851 67.272 ;
     RECT  36.785 38.352 36.929 40.632 ;
     RECT  36.851 67.2 36.929 67.272 ;
     RECT  36.929 38.496 36.965 40.632 ;
     RECT  36.965 38.688 37.073 40.632 ;
     RECT  37.169 0.144 37.213 0.168 ;
     RECT  36.421 62.64 37.285 64.44 ;
     RECT  37.189 68.928 37.381 68.952 ;
     RECT  36.097 1.68 37.429 8.568 ;
     RECT  37.429 1.152 37.541 8.568 ;
     RECT  37.285 62.304 37.613 64.44 ;
     RECT  37.541 1.152 37.619 8.472 ;
     RECT  37.619 2.208 37.721 8.472 ;
     RECT  37.381 68.832 37.765 68.952 ;
     RECT  37.073 38.784 37.793 40.632 ;
     RECT  37.213 0.048 37.82 0.168 ;
     RECT  37.619 1.152 37.82 1.176 ;
     RECT  37.765 68.688 37.853 68.952 ;
     RECT  36.929 67.248 37.937 67.272 ;
     RECT  37.793 39.36 37.973 40.632 ;
     RECT  37.853 68.688 38.099 69 ;
     RECT  38.099 68.736 38.195 69 ;
     RECT  37.721 2.256 38.225 8.472 ;
     RECT  37.82 0.048 38.236 1.176 ;
     RECT  38.225 2.256 38.261 8.28 ;
     RECT  37.973 39.36 38.621 40.2 ;
     RECT  38.195 68.832 38.723 69 ;
     RECT  38.621 39.36 38.765 39.912 ;
     RECT  37.613 62.64 38.78 64.44 ;
     RECT  38.261 2.304 38.837 8.28 ;
     RECT  38.78 62.592 38.867 64.44 ;
     RECT  38.236 1.152 39.109 1.176 ;
     RECT  38.837 2.304 39.125 7.8 ;
     RECT  39.109 1.152 39.251 1.272 ;
     RECT  38.236 0.048 39.301 0.12 ;
     RECT  39.251 1.152 39.301 1.176 ;
     RECT  39.301 0.048 39.347 1.176 ;
     RECT  38.867 63.024 39.877 64.44 ;
     RECT  39.301 67.248 39.877 67.272 ;
     RECT  38.723 68.88 39.877 69 ;
     RECT  39.877 68.784 39.923 69 ;
     RECT  39.125 2.352 40.208 7.8 ;
     RECT  35.104 20.064 40.208 20.088 ;
     RECT  35.104 23.328 40.208 23.592 ;
     RECT  35.267 33.888 40.208 33.912 ;
     RECT  35.267 34.896 40.208 34.92 ;
     RECT  36.353 36.912 40.208 37.08 ;
     RECT  38.765 39.36 40.208 39.816 ;
     RECT  35.104 44.4 40.208 45.192 ;
     RECT  35.104 47.136 40.208 47.16 ;
     RECT  35.104 50.352 40.208 50.376 ;
     RECT  39.877 62.736 40.208 64.44 ;
     RECT  39.877 66.432 40.208 67.272 ;
     RECT  40.208 2.148 40.316 67.272 ;
     RECT  40.316 2.016 40.453 67.272 ;
     RECT  40.453 1.968 40.504 67.272 ;
     RECT  40.504 66.72 40.525 67.272 ;
     RECT  39.923 68.784 40.525 68.904 ;
     RECT  40.525 66.72 40.601 68.904 ;
     RECT  40.601 66.72 40.643 68.856 ;
     RECT  39.347 0.048 41.029 0.84 ;
     RECT  40.504 1.968 41.029 7.128 ;
     RECT  40.643 66.72 41.075 67.848 ;
     RECT  40.504 63.12 41.573 64.44 ;
     RECT  41.075 67.248 41.651 67.848 ;
     RECT  40.643 68.832 41.701 68.856 ;
     RECT  41.701 68.832 41.749 68.952 ;
     RECT  41.029 0.048 41.821 7.128 ;
     RECT  41.749 68.4 41.891 68.952 ;
     RECT  41.651 67.248 42.044 67.272 ;
     RECT  42.044 67.2 42.073 67.272 ;
     RECT  41.573 64.416 42.253 64.44 ;
     RECT  42.037 62.112 42.277 62.136 ;
     RECT  41.573 63.12 42.277 63.24 ;
     RECT  41.821 0.048 42.293 7.464 ;
     RECT  42.277 62.112 42.323 63.24 ;
     RECT  40.504 23.328 42.505 23.592 ;
     RECT  42.323 62.592 42.515 63.24 ;
     RECT  42.073 67.104 42.62 67.272 ;
     RECT  42.515 62.736 42.725 63.24 ;
     RECT  41.891 68.4 42.803 68.424 ;
     RECT  42.62 66.72 42.829 67.272 ;
     RECT  42.253 64.416 42.865 64.632 ;
     RECT  42.865 64.416 42.905 64.968 ;
     RECT  42.905 64.608 43.157 64.968 ;
     RECT  42.829 66.672 43.189 67.272 ;
     RECT  42.293 7.44 43.331 7.464 ;
     RECT  43.189 66.144 43.553 67.272 ;
     RECT  43.553 66.144 43.571 66.168 ;
     RECT  42.293 0.048 43.837 6.024 ;
     RECT  42.505 23.328 43.949 23.88 ;
     RECT  43.837 0.048 43.985 6.12 ;
     RECT  43.333 68.928 44.005 68.952 ;
     RECT  42.725 63.024 44.053 63.24 ;
     RECT  40.504 44.4 44.089 45.192 ;
     RECT  44.005 68.832 44.291 68.952 ;
     RECT  43.985 0.048 44.309 0.408 ;
     RECT  44.309 0.048 44.345 0.312 ;
     RECT  44.345 0.048 44.381 0.216 ;
     RECT  44.291 68.88 44.386 68.952 ;
     RECT  44.053 62.832 44.389 63.24 ;
     RECT  44.389 62.832 44.476 63.768 ;
     RECT  44.386 68.88 44.531 69 ;
     RECT  43.985 1.776 44.561 6.12 ;
     RECT  44.561 1.776 44.741 4.296 ;
     RECT  43.553 67.152 44.837 67.272 ;
     RECT  44.837 67.152 44.946 67.32 ;
     RECT  44.476 63.264 45.157 63.768 ;
     RECT  45.157 63.264 45.253 63.864 ;
     RECT  43.157 64.848 45.253 64.968 ;
     RECT  44.089 44.4 45.277 45.768 ;
     RECT  44.531 68.88 45.397 68.952 ;
     RECT  45.253 63.264 45.445 64.968 ;
     RECT  45.397 68.832 45.587 68.952 ;
     RECT  44.741 2.148 45.608 4.296 ;
     RECT  44.561 5.616 45.608 6.12 ;
     RECT  40.504 20.064 45.608 20.088 ;
     RECT  43.949 23.568 45.608 23.88 ;
     RECT  40.504 33.888 45.608 33.912 ;
     RECT  40.504 34.896 45.608 34.92 ;
     RECT  40.504 36.912 45.608 37.08 ;
     RECT  40.504 39.36 45.608 39.816 ;
     RECT  45.277 44.4 45.608 46.728 ;
     RECT  40.504 50.352 45.608 50.376 ;
     RECT  45.445 63.072 45.608 64.968 ;
     RECT  44.946 67.152 45.608 67.272 ;
     RECT  45.608 2.148 45.712 67.272 ;
     RECT  45.712 2.418 45.904 67.272 ;
     RECT  44.381 0.048 46.001 0.072 ;
     RECT  45.904 6 46.019 6.552 ;
     RECT  45.904 19.392 46.045 20.232 ;
     RECT  45.904 66.912 46.109 67.272 ;
     RECT  45.587 68.928 46.115 68.952 ;
     RECT  46.019 6.096 46.181 6.552 ;
     RECT  45.904 63.216 46.181 64.92 ;
     RECT  46.109 67.056 46.181 67.272 ;
     RECT  46.181 67.104 46.385 67.272 ;
     RECT  46.045 20.208 46.691 20.232 ;
     RECT  45.904 36.912 46.793 37.08 ;
     RECT  46.385 67.104 47.141 67.32 ;
     RECT  47.141 67.104 47.18 67.368 ;
     RECT  47.18 67.056 47.185 67.368 ;
     RECT  47.185 66.864 47.225 67.368 ;
     RECT  47.225 66.864 47.365 67.32 ;
     RECT  45.904 50.352 47.513 50.376 ;
     RECT  47.365 66.72 47.513 67.32 ;
     RECT  46.181 63.216 47.555 64.872 ;
     RECT  45.904 48.192 47.801 48.216 ;
     RECT  45.904 33.888 47.941 34.92 ;
     RECT  47.555 63.792 48.053 64.872 ;
     RECT  47.513 66.72 48.449 67.272 ;
     RECT  48.449 66.816 48.467 67.272 ;
     RECT  48.053 64.848 48.517 64.872 ;
     RECT  47.941 33.888 48.553 35.304 ;
     RECT  48.553 33.888 48.697 35.544 ;
     RECT  48.697 33.888 48.737 35.88 ;
     RECT  48.737 34.416 48.769 35.88 ;
     RECT  46.793 37.008 48.769 37.08 ;
     RECT  48.769 34.416 48.989 37.08 ;
     RECT  48.949 68.976 49.043 69 ;
     RECT  48.053 63.792 49.097 63.816 ;
     RECT  48.467 66.912 49.277 67.272 ;
     RECT  48.517 64.848 49.561 65.832 ;
     RECT  49.561 63.84 49.619 65.832 ;
     RECT  49.619 65.808 49.637 65.832 ;
     RECT  49.277 66.912 49.637 67.224 ;
     RECT  49.619 63.84 49.66 64.248 ;
     RECT  49.021 50.688 49.667 50.712 ;
     RECT  48.989 35.52 49.673 37.08 ;
     RECT  49.66 63.84 49.681 64.152 ;
     RECT  49.673 35.52 49.781 35.88 ;
     RECT  49.781 35.856 49.853 35.88 ;
     RECT  49.673 36.912 49.997 37.08 ;
     RECT  49.637 67.152 50.069 67.224 ;
     RECT  50.069 67.152 50.321 67.176 ;
     RECT  49.997 36.912 50.641 37.032 ;
     RECT  46.181 6.528 51.008 6.552 ;
     RECT  45.904 21.504 51.008 21.528 ;
     RECT  45.904 23.568 51.008 23.88 ;
     RECT  50.641 36.624 51.008 37.032 ;
     RECT  45.904 39.36 51.008 39.816 ;
     RECT  45.904 44.4 51.008 45.192 ;
     RECT  49.621 49.488 51.008 49.512 ;
     RECT  49.681 64.128 51.008 64.152 ;
     RECT  51.008 2.148 51.112 66.972 ;
     RECT  51.112 2.418 51.304 66.702 ;
     RECT  51.304 6.528 56.408 6.552 ;
     RECT  51.304 21.504 56.408 21.528 ;
     RECT  51.304 23.568 56.408 23.88 ;
     RECT  51.304 36.912 56.408 36.936 ;
     RECT  51.304 39.36 56.408 39.816 ;
     RECT  51.304 44.4 56.408 45.192 ;
     RECT  51.304 49.488 56.408 49.512 ;
     RECT  56.408 2.148 56.512 66.972 ;
     RECT  56.512 2.418 56.704 66.702 ;
     RECT  56.704 23.568 57.125 23.88 ;
     RECT  56.704 39.36 58.705 39.816 ;
     RECT  56.704 36.912 58.741 36.936 ;
     RECT  56.704 44.4 58.741 45.192 ;
     RECT  58.705 34.512 58.853 34.536 ;
     RECT  58.705 38.832 58.853 39.816 ;
     RECT  58.741 36.912 58.889 37.176 ;
     RECT  58.741 43.584 58.889 45.192 ;
     RECT  58.705 47.04 58.889 47.064 ;
     RECT  58.741 51.168 58.889 51.192 ;
     RECT  58.705 27.456 58.925 27.48 ;
     RECT  58.741 30.384 58.997 30.408 ;
     RECT  58.741 42.48 59.569 42.504 ;
     RECT  59.569 42.48 59.641 43.32 ;
     RECT  58.889 44.4 59.713 45.192 ;
     RECT  56.704 21.504 59.785 21.528 ;
     RECT  57.125 23.568 59.852 23.688 ;
     RECT  59.785 21.504 59.857 22.296 ;
     RECT  59.713 44.4 59.857 45.768 ;
     RECT  59.677 33.264 59.893 33.288 ;
     RECT  56.704 49.488 59.893 49.512 ;
     RECT  56.704 6.528 59.939 6.552 ;
     RECT  59.852 23.28 59.939 23.688 ;
     RECT  58.853 39.504 59.965 39.816 ;
     RECT  59.857 44.4 59.965 46.536 ;
     RECT  59.821 29.376 60.037 29.4 ;
     RECT  59.641 42.288 60.037 43.32 ;
     RECT  59.965 44.4 60.037 47.304 ;
     RECT  60.037 29.376 60.083 30.216 ;
     RECT  59.785 24.816 60.113 24.84 ;
     RECT  60.037 42.288 60.113 47.304 ;
     RECT  60.083 29.424 60.124 30.216 ;
     RECT  59.749 31.344 60.325 31.368 ;
     RECT  59.893 33.12 60.325 33.288 ;
     RECT  59.749 27.936 60.361 27.96 ;
     RECT  60.325 31.344 60.397 33.288 ;
     RECT  59.893 49.488 60.505 49.8 ;
     RECT  60.361 27.168 60.541 27.96 ;
     RECT  59.713 26.112 60.793 26.136 ;
     RECT  60.541 27.12 60.793 27.96 ;
     RECT  60.397 30.624 60.793 33.288 ;
     RECT  60.793 26.112 60.865 27.96 ;
     RECT  60.505 49.008 60.865 49.8 ;
     RECT  60.865 26.064 60.973 27.96 ;
     RECT  58.889 36.912 60.973 36.936 ;
     RECT  60.865 49.008 60.997 50.136 ;
     RECT  60.973 51.12 60.997 51.144 ;
     RECT  59.939 23.568 61.081 23.688 ;
     RECT  60.113 43.92 61.081 45.192 ;
     RECT  60.793 30.624 61.1 34.104 ;
     RECT  59.965 39.216 61.117 39.816 ;
     RECT  60.113 42.288 61.117 42.6 ;
     RECT  60.973 24.96 61.153 27.96 ;
     RECT  61.1 30.624 61.225 34.536 ;
     RECT  60.937 35.808 61.225 35.832 ;
     RECT  61.153 24.912 61.477 27.96 ;
     RECT  60.124 29.424 61.477 29.448 ;
     RECT  61.477 24.912 61.513 29.448 ;
     RECT  61.225 30.624 61.513 35.832 ;
     RECT  61.513 24.912 61.585 35.832 ;
     RECT  60.973 36.912 61.585 37.896 ;
     RECT  61.117 39.216 61.765 42.6 ;
     RECT  61.081 43.632 61.765 45.192 ;
     RECT  60.997 49.008 61.765 51.144 ;
     RECT  59.857 20.592 61.808 22.296 ;
     RECT  61.081 23.568 61.808 23.928 ;
     RECT  61.585 24.912 61.808 37.896 ;
     RECT  61.765 39.216 61.808 45.192 ;
     RECT  60.113 46.368 61.808 47.304 ;
     RECT  61.765 48.672 61.808 51.144 ;
     RECT  61.808 2.148 61.912 66.972 ;
     RECT  61.912 2.418 62.104 66.702 ;
     RECT  62.104 20.496 62.165 23.928 ;
     RECT  62.104 39.312 62.243 49.032 ;
     RECT  62.104 34.992 62.453 37.512 ;
     RECT  62.453 34.992 62.867 35.832 ;
     RECT  62.243 39.312 62.867 42.312 ;
     RECT  62.867 34.992 62.885 35.736 ;
     RECT  62.453 36.816 62.921 37.512 ;
     RECT  62.104 25.344 63.277 33.96 ;
     RECT  62.885 34.992 63.277 35.016 ;
     RECT  62.165 20.496 63.317 23.688 ;
     RECT  62.104 50.352 63.349 50.856 ;
     RECT  63.317 21.36 63.353 23.688 ;
     RECT  62.867 39.312 63.353 39.816 ;
     RECT  62.243 43.296 63.353 49.032 ;
     RECT  63.277 25.344 63.461 35.016 ;
     RECT  63.353 39.312 63.497 39.528 ;
     RECT  63.461 34.512 63.605 35.016 ;
     RECT  63.353 43.296 63.749 48.264 ;
     RECT  63.749 43.872 63.785 48.264 ;
     RECT  63.349 50.352 63.785 51.192 ;
     RECT  63.353 21.6 63.893 23.688 ;
     RECT  63.461 25.344 63.893 33.144 ;
     RECT  63.785 45.6 63.893 48.264 ;
     RECT  62.921 36.912 63.929 37.512 ;
     RECT  62.867 40.896 64.141 42.312 ;
     RECT  63.893 21.6 64.259 21.672 ;
     RECT  64.259 21.6 64.357 21.624 ;
     RECT  63.893 25.344 64.393 31.272 ;
     RECT  63.785 50.352 64.573 51 ;
     RECT  63.785 43.872 64.577 44.472 ;
     RECT  64.357 20.832 64.649 21.624 ;
     RECT  64.393 25.056 64.721 31.272 ;
     RECT  63.893 22.8 64.757 23.688 ;
     RECT  64.649 20.832 64.865 21.576 ;
     RECT  64.721 28.656 64.865 31.272 ;
     RECT  64.141 40.896 64.865 42.744 ;
     RECT  64.865 28.656 64.901 29.976 ;
     RECT  64.865 31.008 64.933 31.272 ;
     RECT  63.893 32.352 64.933 33.144 ;
     RECT  64.757 23.664 64.973 23.688 ;
     RECT  63.497 39.504 64.973 39.528 ;
     RECT  64.577 44.208 64.973 44.472 ;
     RECT  64.865 41.856 65.009 42.744 ;
     RECT  64.973 44.352 65.009 44.472 ;
     RECT  64.573 50.256 65.045 51 ;
     RECT  64.933 31.008 65.077 33.144 ;
     RECT  65.045 50.256 65.081 50.28 ;
     RECT  64.721 25.056 65.113 27.144 ;
     RECT  65.113 24.48 65.153 27.144 ;
     RECT  63.893 46.416 65.153 48.264 ;
     RECT  65.009 44.352 65.189 44.424 ;
     RECT  64.901 29.808 65.297 29.976 ;
     RECT  65.009 42.72 65.297 42.744 ;
     RECT  65.153 46.416 65.473 47.496 ;
     RECT  63.929 36.912 65.797 37.128 ;
     RECT  65.153 26.016 66.049 27.144 ;
     RECT  65.153 24.48 66.121 24.504 ;
     RECT  66.049 26.016 66.229 27.528 ;
     RECT  65.189 44.352 66.269 44.376 ;
     RECT  64.865 21.552 66.341 21.576 ;
     RECT  66.229 25.872 66.373 27.528 ;
     RECT  65.077 31.008 66.373 33.192 ;
     RECT  66.121 42.864 66.373 42.888 ;
     RECT  66.373 30.912 66.553 33.192 ;
     RECT  65.869 22.704 66.697 22.728 ;
     RECT  65.797 36.672 66.697 37.128 ;
     RECT  65.473 46.32 66.697 47.496 ;
     RECT  66.697 45.936 66.733 47.496 ;
     RECT  66.157 41.712 67.201 41.736 ;
     RECT  66.697 21.36 67.237 21.48 ;
     RECT  67.201 35.472 67.237 35.496 ;
     RECT  66.697 36.672 67.237 37.512 ;
     RECT  66.697 39.408 67.237 40.392 ;
     RECT  67.201 41.52 67.237 41.736 ;
     RECT  66.733 45.744 67.237 47.496 ;
     RECT  67.237 20.784 67.273 21.48 ;
     RECT  66.697 22.512 67.273 22.728 ;
     RECT  66.121 23.952 67.273 24.504 ;
     RECT  66.373 25.872 67.273 28.488 ;
     RECT  65.297 29.808 67.273 29.832 ;
     RECT  66.553 30.864 67.273 33.192 ;
     RECT  67.237 34.224 67.273 34.248 ;
     RECT  67.237 35.376 67.273 35.496 ;
     RECT  67.237 36.528 67.273 37.512 ;
     RECT  67.237 39.408 67.273 41.736 ;
     RECT  66.373 42.864 67.273 43.848 ;
     RECT  67.237 45.168 67.273 48.072 ;
     RECT  67.273 44.88 67.309 48.072 ;
     RECT  67.237 49.104 67.309 50.856 ;
     RECT  67.273 20.4 67.345 21.48 ;
     RECT  67.273 22.512 67.345 37.8 ;
     RECT  67.345 20.4 67.741 37.8 ;
     RECT  67.741 20.4 67.777 38.184 ;
     RECT  67.273 39.312 67.777 43.848 ;
     RECT  67.309 44.88 67.777 50.856 ;
     RECT  67.777 39.312 67.813 51.048 ;
     RECT  67.777 19.92 68.353 38.184 ;
     RECT  67.813 39.216 68.353 51.048 ;
     RECT  68.353 19.92 69.084 51.336 ;
    LAYER M5 ;
     RECT  29.136 0.016 42.12 1.187 ;
     RECT  2.4 2.137 2.52 2.151 ;
     RECT  7.8 2.137 7.92 2.151 ;
     RECT  13.2 2.137 13.32 2.151 ;
     RECT  18.6 2.137 18.72 2.151 ;
     RECT  24 2.137 24.12 2.151 ;
     RECT  45.6 2.137 45.72 2.151 ;
     RECT  51 2.137 51.12 2.151 ;
     RECT  56.4 2.137 56.52 2.151 ;
     RECT  61.8 2.137 61.92 2.151 ;
     RECT  43.44 2.389 43.464 2.627 ;
     RECT  29.28 1.187 42.12 2.821 ;
     RECT  28.368 2.821 42.12 3.299 ;
     RECT  28.368 3.299 41.544 4.019 ;
     RECT  29.4 4.019 41.544 4.067 ;
     RECT  29.4 4.067 41.448 5.459 ;
     RECT  29.4 5.459 41.016 5.747 ;
     RECT  31.632 5.747 41.016 5.843 ;
     RECT  42.768 5.029 42.792 5.845 ;
     RECT  42.768 5.845 43.32 5.891 ;
     RECT  45.6 2.151 45.912 5.989 ;
     RECT  32.112 5.843 41.016 6.371 ;
     RECT  41.52 6.421 41.544 6.755 ;
     RECT  29.4 5.747 29.88 6.805 ;
     RECT  32.112 6.371 40.512 6.851 ;
     RECT  40.08 6.851 40.512 6.899 ;
     RECT  32.112 6.851 38.856 6.995 ;
     RECT  32.112 6.995 38.52 7.235 ;
     RECT  38.448 7.235 38.52 7.379 ;
     RECT  28.368 4.019 28.392 7.381 ;
     RECT  29.4 6.805 30.408 7.381 ;
     RECT  28.368 7.381 30.408 7.427 ;
     RECT  32.112 7.235 37.464 7.475 ;
     RECT  43.296 5.891 43.32 7.475 ;
     RECT  32.112 7.475 32.136 7.571 ;
     RECT  33.264 7.475 33.288 7.907 ;
     RECT  34.8 7.475 37.464 7.907 ;
     RECT  34.8 7.907 36.36 8.003 ;
     RECT  38.448 7.379 38.472 8.003 ;
     RECT  34.8 8.003 35.976 8.435 ;
     RECT  34.8 8.435 35.208 8.531 ;
     RECT  37.44 7.907 37.464 8.579 ;
     RECT  27.36 10.069 27.384 10.595 ;
     RECT  28.368 7.427 29.712 10.883 ;
     RECT  28.368 10.883 28.392 13.043 ;
     RECT  13.2 2.151 13.512 13.045 ;
     RECT  12.96 13.045 13.512 13.477 ;
     RECT  12.912 13.477 13.512 17.651 ;
     RECT  2.4 2.151 2.712 19.717 ;
     RECT  7.8 2.151 8.112 20.005 ;
     RECT  34.8 8.531 35.112 20.053 ;
     RECT  45.6 5.989 46.008 20.197 ;
     RECT  2.4 19.717 3.096 20.387 ;
     RECT  7.44 20.005 8.112 20.387 ;
     RECT  12.96 17.651 13.512 20.387 ;
     RECT  45.6 20.197 46.68 21.539 ;
     RECT  0.192 21.925 0.216 22.115 ;
     RECT  0.144 22.501 0.168 22.787 ;
     RECT  2.4 20.387 2.712 23.125 ;
     RECT  59.904 6.517 59.928 23.315 ;
     RECT  2.304 23.125 2.712 23.363 ;
     RECT  7.68 20.387 8.112 25.859 ;
     RECT  24 2.151 24.312 27.301 ;
     RECT  2.4 23.363 2.712 27.493 ;
     RECT  2.304 27.493 2.712 27.683 ;
     RECT  24 27.301 25.272 28.309 ;
     RECT  64.224 21.637 64.248 28.357 ;
     RECT  63.456 28.357 64.248 28.403 ;
     RECT  7.8 25.859 8.112 30.181 ;
     RECT  7.44 30.181 8.112 30.851 ;
     RECT  60.048 29.365 60.072 31.379 ;
     RECT  4.272 24.805 4.296 31.381 ;
     RECT  4.272 31.381 4.392 31.427 ;
     RECT  63.456 28.403 63.48 31.619 ;
     RECT  2.4 27.683 2.712 31.765 ;
     RECT  61.8 2.151 62.112 31.765 ;
     RECT  2.304 31.765 2.712 31.955 ;
     RECT  61.8 31.765 62.232 32.483 ;
     RECT  4.368 31.427 4.392 33.107 ;
     RECT  63.408 31.861 63.432 33.683 ;
     RECT  61.8 32.483 62.112 34.501 ;
     RECT  29.4 10.883 29.712 34.645 ;
     RECT  61.152 34.501 62.112 35.797 ;
     RECT  0.144 36.229 0.168 36.851 ;
     RECT  7.8 30.851 8.112 36.901 ;
     RECT  51 2.151 51.312 36.901 ;
     RECT  50.352 36.901 51.312 37.043 ;
     RECT  7.056 36.901 8.112 37.859 ;
     RECT  2.4 31.955 2.712 38.965 ;
     RECT  0.144 38.773 0.168 39.059 ;
     RECT  61.152 35.797 62.856 39.251 ;
     RECT  2.4 38.965 2.808 39.347 ;
     RECT  7.68 37.859 8.112 39.973 ;
     RECT  6.816 39.973 8.112 40.211 ;
     RECT  4.32 37.477 4.344 40.259 ;
     RECT  5.76 39.253 5.784 40.595 ;
     RECT  2.4 39.347 2.712 42.997 ;
     RECT  2.064 42.997 2.712 43.187 ;
     RECT  7.68 40.211 8.112 43.285 ;
     RECT  61.8 39.251 62.856 44.101 ;
     RECT  60.912 44.101 63.144 44.147 ;
     RECT  30.72 43.861 30.744 44.243 ;
     RECT  5.76 42.709 5.784 44.627 ;
     RECT  7.44 43.285 8.112 44.677 ;
     RECT  7.44 44.677 8.232 44.723 ;
     RECT  0.144 44.725 0.168 45.109 ;
     RECT  0.144 45.109 0.216 45.445 ;
     RECT  0.144 45.445 0.312 45.587 ;
     RECT  63.12 44.147 63.144 45.635 ;
     RECT  0.144 45.587 0.168 46.067 ;
     RECT  4.656 45.781 4.68 46.067 ;
     RECT  7.8 44.723 8.232 48.421 ;
     RECT  4.272 48.421 4.296 48.995 ;
     RECT  60.912 44.147 62.112 49.043 ;
     RECT  0.144 48.997 0.168 49.187 ;
     RECT  7.8 48.421 8.376 49.763 ;
     RECT  61.8 49.043 62.112 50.101 ;
     RECT  34.8 20.053 35.256 50.387 ;
     RECT  18.6 2.151 18.912 50.389 ;
     RECT  7.8 49.763 8.232 50.435 ;
     RECT  61.008 50.101 62.112 50.867 ;
     RECT  42.288 62.101 42.312 62.581 ;
     RECT  37.296 62.293 37.32 62.629 ;
     RECT  38.832 62.581 38.856 62.629 ;
     RECT  21.072 62.581 21.096 62.725 ;
     RECT  24 28.309 25.416 62.725 ;
     RECT  40.2 6.899 40.512 62.725 ;
     RECT  28.944 34.645 29.712 62.821 ;
     RECT  36.48 62.629 38.856 63.013 ;
     RECT  39.888 62.725 40.512 63.013 ;
     RECT  44.064 62.821 44.424 63.013 ;
     RECT  18.6 50.389 19.08 63.061 ;
     RECT  23.184 62.725 25.416 63.061 ;
     RECT  45.6 21.539 45.912 63.061 ;
     RECT  20.448 62.725 21.096 63.109 ;
     RECT  34.8 50.387 35.112 63.109 ;
     RECT  36.48 63.013 40.512 63.109 ;
     RECT  42.288 62.581 42.504 63.109 ;
     RECT  34.8 63.109 42.504 63.157 ;
     RECT  20.448 63.109 21.384 63.205 ;
     RECT  22.992 63.061 25.416 63.205 ;
     RECT  34.56 63.157 42.504 63.205 ;
     RECT  43.632 63.013 44.424 63.205 ;
     RECT  45.456 63.061 45.912 63.205 ;
     RECT  18.432 63.061 19.08 63.253 ;
     RECT  20.448 63.205 25.608 63.253 ;
     RECT  26.88 62.821 29.712 63.253 ;
     RECT  34.032 63.205 44.424 63.253 ;
     RECT  45.456 63.205 46.104 63.253 ;
     RECT  47.232 63.205 47.544 63.253 ;
     RECT  18.432 63.253 25.608 63.637 ;
     RECT  31.824 63.253 31.848 63.637 ;
     RECT  32.976 63.205 33 63.637 ;
     RECT  34.032 63.253 47.544 63.637 ;
     RECT  31.536 63.637 47.544 63.781 ;
     RECT  26.88 63.253 29.928 63.829 ;
     RECT  31.536 63.781 48.36 63.829 ;
     RECT  49.632 49.477 49.656 63.875 ;
     RECT  18.432 63.637 25.704 64.019 ;
     RECT  49.584 64.213 49.608 64.883 ;
     RECT  26.88 63.829 48.36 65.797 ;
     RECT  18.432 64.019 18.912 66.709 ;
     RECT  19.92 64.019 25.704 66.709 ;
     RECT  26.88 65.797 48.552 66.709 ;
     RECT  18 66.709 48.552 66.901 ;
     RECT  2.4 43.187 2.712 66.969 ;
     RECT  7.8 50.435 8.112 66.969 ;
     RECT  13.2 20.387 13.512 66.969 ;
     RECT  51 37.043 51.312 66.969 ;
     RECT  56.4 2.151 56.712 66.969 ;
     RECT  61.8 50.867 62.112 66.969 ;
     RECT  2.4 66.969 2.52 66.983 ;
     RECT  7.8 66.969 7.92 66.983 ;
     RECT  13.2 66.969 13.32 66.983 ;
     RECT  51 66.969 51.12 66.983 ;
     RECT  56.4 66.969 56.52 66.983 ;
     RECT  61.8 66.969 61.92 66.983 ;
     RECT  18 66.901 48.648 67.141 ;
     RECT  18 67.141 48.936 67.237 ;
     RECT  18 67.237 49.128 67.813 ;
     RECT  17.712 67.813 49.128 69.072 ;
  END
END ot_hbm_host_cfg_leaf_nw
END LIBRARY
